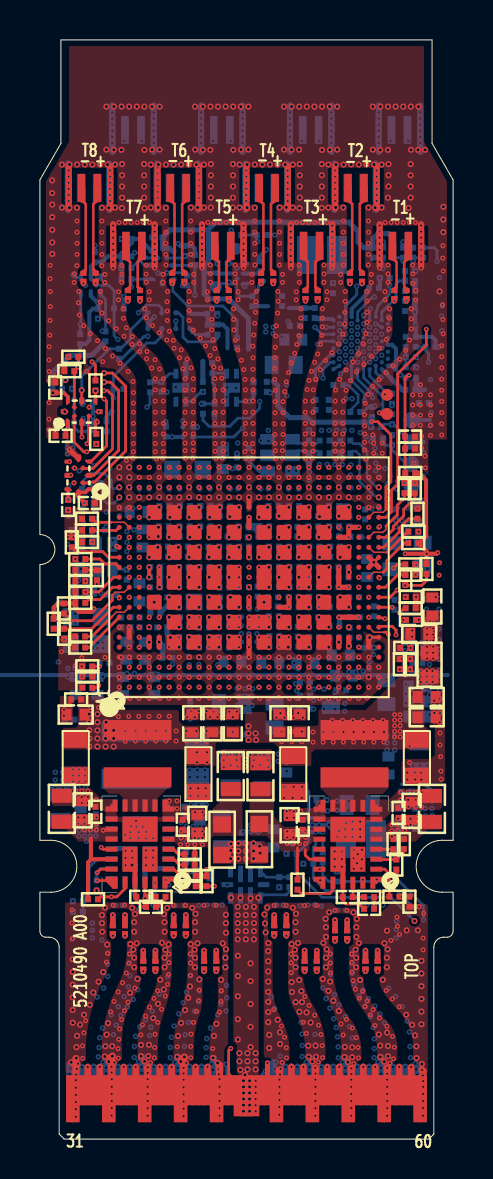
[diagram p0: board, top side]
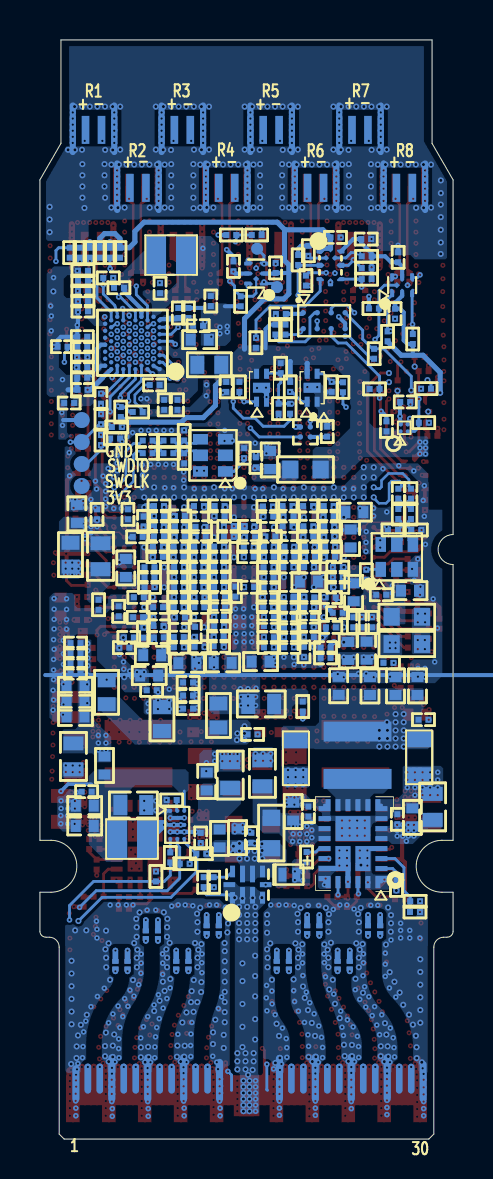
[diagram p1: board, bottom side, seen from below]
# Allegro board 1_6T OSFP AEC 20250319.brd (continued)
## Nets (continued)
LTX_P4: C922.1 U1.T23
LTX_P5: C924.1 U1.N23
LTX_P6: C926.1 U1.K23
LTX_P7: C928.1 U1.G23
LTX_P8: C930.1 U1.D23
LTXN1: C917.2 J2.3
LTXN2: C919.2 J6.3
LTXN3: C921.2 J10.3
LTXN4: C923.2 J14.3
LTXN5: C925.2 J3.3
LTXN6: C927.2 J7.3
LTXN7: C929.2 J11.3
LTXN8: C931.2 J15.3
LTXP1: C916.2 J2.2
LTXP2: C918.2 J6.2
LTXP3: C920.2 J10.2
LTXP4: C922.2 J14.2
LTXP5: C924.2 J3.2
LTXP6: C926.2 J7.2
LTXP7: C928.2 J11.2
LTXP8: C930.2 J15.2
M_INT: R31.2 U2.B4
M_LPWN: R29.2 U2.B6 U24.1
M_RSTN: C60.2 R28.2 R599.2 U2.A5 U4.1
MCU33: C42.2 C43.2 C169.2 C170.2 C173.2 C342.1 C419.2 C476.2 C891.2 C892.2 C933.2 L81.1 U2.A1 U2.A7 U2.B2 U2.B10 U2.G1 U2.H10 U2.R1 U2.R3 U2.T8
MCU_SPI_CLK: R15.2 R41.1 U17.10 U22.C1
MCU_SPI_CSB: R10.2 R40.1 U17.8 U22.A2
MCU_SPI_MISO: R11.2 U17.7 U22.B2
MCU_SPI_MOSI: R12.2 U17.9 U22.D1
MISO_SLV: U2.E5 U46.5
MISO_SLV_18: R829.2 R830.2 U46.7
MODE_SEL0: R404.1 R769.2 U1.C12 U2.N5
MOSI_SLV: U2.F6 U46.4
MOSI_SLV_18: U1.B14 U46.8
NRST: C455.2 R599.1 R603.2 U2.F8
OSFP_SCL: J1.14 R647.2 TP1.1(\TP\) U2.P4 U48.1
OSFP_SDA: J1.47 R648.2 TP2.1(\TP\) U2.C5 U48.3
PHY_I2C_LS_EN: R73.1 U2.J1 U10.8
PHY_I2C_SCL_33: R579.2 U2.E7 U10.1
PHY_I2C_SDA_33: R580.2 U2.C7 U10.3
PHY_INTR_N_18: R583.2 U1.C6 U38.7
PHY_INTR_N_33: R233.1 U2.A3 U38.5
PHY_RST_N_0_18: R856.2 U1.B10 U38.10
PHY_RST_N_0_33: R581.1 U2.R5 U38.2
PHY_RST_N_1_18: R855.2 U1.AF7 U38.9
PHY_RST_N_1_33: R582.1 U2.M4 U38.3
PHY_SELF_INIT_18: R783.1 U1.B8 U38.8
PHY_SELF_INIT_33: R849.1 U2.T6 U38.4
PMIC_SCL: R62.2 U2.G3 U20.20 U26.20 U37.E3
PMIC_SDA: R64.2 U2.F2 U20.19 U26.19 U37.E2
PMIC_SYNC1: U20.17 U21.18
PMIC_SYNC2: R685.1 U21.17
RXN1: C216.1 J1.28
RXN2: C218.1 J1.33
RXN3: C220.1 J1.25
RXN4: C222.1 J1.36
RXN5: C224.1 J1.22
RXN6: C226.1 J1.39
RXN7: C228.1 J1.19
RXN8: C230.1 J1.42
RXP1: C215.1 J1.29
RXP2: C217.1 J1.32
RXP3: C219.1 J1.26
RXP4: C221.1 J1.35
RXP5: C223.1 J1.23
RXP6: C225.1 J1.38
RXP7: C227.1 J1.20
RXP8: C229.1 J1.41
SCK_SLV: U2.C3 U46.2
SCK_SLV_18: U1.A15 U46.10
SPI_OE_DSP_EEPROM: U2.E9 U17.12
SS_N_SLV: U2.D4 U46.3
SS_N_SLV1: U1.AG10 U47.B2(\Y\)
SS_N_SLV_18: U1.C13 U46.9 U47.A1
SWCLK: J18.3 R5.2 R6.2 R648.1 U2.E3
SWDIO: J18.2 R3.1 R4.2 R647.1 U2.F4
TEMP_SENSOR: C40.2 R22.2 R25.1 U2.H6
TXN1: C200.2 J1.58
TXN2: C202.2 J1.3
TXN3: C204.2 J1.55
TXN4: C206.2 J1.6
TXN5: C208.2 J1.52
TXN6: C210.2 J1.9
TXN7: C212.2 J1.49
TXN8: C214.2 J1.12
TXP1: C199.2 J1.59
TXP2: C201.2 J1.2
TXP3: C203.2 J1.56
TXP4: C205.2 J1.5
TXP5: C207.2 J1.53
TXP6: C209.2 J1.8
TXP7: C211.2 J1.50
TXP8: C213.2 J1.11
VCAP: C174.2 C478.2 C479.2 C480.2 L27.2 U2.A9 U2.T2
VLXSMPS: C477.2 L27.1 U2.T4
N16845549: R760.1 R787.2 Y2.5
N16845553: R759.1 R788.2 Y2.4
N17308149: C649.1 C652.1 L95.1 Y2.6(\VCC\)
N17319056: R755.1 U1.A14
N17320165: R718.1 U1.C5
N17320275: R719.1 U1.AF8
N17322132: R770.1 R771.1 U1.C7
N17324604: R75.1 R767.1 U1.A9
N17324668: R105.1 R411.1 U1.C8
N17332280: R693.1 U1.AF12
N17332314: R694.1 U1.A11
N17340476: L4.1 U20.9 U20.10 U20.11 U20.12
N17340636: R46.2 R629.2 U20.3
N17341396: L88.1 U26.9 U26.10 U26.11 U26.12
N17341552: C501.1 R712.1 U26.23
N17341615: R710.2 U26.2
N17342760: L89.1 U37.C1 U37.C2 U37.C3
N17421630: C651.1 R787.1
N17421668: C650.1 R788.1
N17477873: C939.1 R735.2 U32.9
N17495631: C48.1 C49.1 L84.1 Y1.6(\VCC\)
N17495710: R35.1 R789.2 Y1.5
N17495716: C50.1 R789.1
N17495751: R36.1 R790.2 Y1.4
N17495757: C51.1 R790.1
N17508857: R690.1 U1.AE6
N17508860: R691.1 U1.B11
N17522369: R618.2 U20.4(\VSEL\)
N17525795: R711.2 R779.2 U26.3
N17525820: R748.2 U26.4(\VSEL\)
N17538591: R852.2 U37.E1
N17552273: C79.2 R649.1
N17552308: C346.2 R650.1
N17587092: L87.1 U21.9 U21.10 U21.11 U21.12
N17587354: R610.2 R778.2 U21.3
N17609312: R10.1 U2.L3
N17609315: R15.1 U2.M2
N17609318: R11.1 U2.N1
N17609321: R12.1 U2.L1
N17614675: R841.1 R842.1 U2.R9
N17630589: R829.1 U1.A13
N17630592: R830.1 U1.AE12
N17634649: R761.2 U1.P12
N17634729: R762.2 U1.P13
N17634818: R764.1 U1.B9
N17634883: R765.1 U1.AE5
N17635276: R833.1 U1.AF15
N17635432: R834.1 U1.AG15
N17635549: R835.1 U1.A17
N17635552: R838.1 U1.B17
N17635615: R836.1 U1.B15
N17635680: R815.1 U1.AF16
N17635747: R837.1 U1.AG16
N17635816: R839.1 U1.AE10
N17636368: R766.1 U1.A8
N17636718: R758.1 R783.2 U1.AG11
N17636870: R758.2 R854.1 U1.B12
N17689668: R845.2 U21.2
N17728804: C78.1 R608.2
N17738812: C492.1 R712.2
N17896792: R32.1 U22.B1
N17922824: TP3.1(\TP\) U1.AE19 U1.C19
N17922836: TP4.1(\TP\) U1.AE18 U1.C18

Pads without a net: U1 A5 A6 A18 AE7 AE9 AE13 AE14 AE15 AE16 AF9 AF11 AG4 AG5 C9 C10 C11; U2 C9 D10 F10 J9 K6 K10 M10; U26 17; Y1 2; Y2 2

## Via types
v1: diameter 0.254, hole 0.102, TOP to L2_GND, 1555 vias
v2: diameter 0.305, hole 0.152, TOP to BOTTOM, 617 vias
v3: diameter 0.279, hole 0.114, L2_GND to L3_GND, 1317 vias
v4: diameter 0.279, hole 0.114, L3_GND to L4_SIG1, 1273 vias
v5: diameter 0.279, hole 0.114, L4_SIG1 to L5_GND, 1113 vias
v6: diameter 0.279, hole 0.114, L11_GND to BOTTOM, 999 vias
v7: diameter 0.279, hole 0.114, L9_SIG2 to L10_GND, 1309 vias
v8: diameter 0.279, hole 0.114, L10_GND to L11_GND, 933 vias
v9: diameter 0.305, hole 0.152, L4_SIG1 to L9_SIG2, 278 vias
v10: diameter 0.279, hole 0.114, L7_PWR2 to L8_GND, 730 vias
v11: diameter 0.279, hole 0.114, L8_GND to L9_SIG2, 1077 vias
v12: diameter 0.279, hole 0.114, L5_GND to L6_PWR1, 953 vias

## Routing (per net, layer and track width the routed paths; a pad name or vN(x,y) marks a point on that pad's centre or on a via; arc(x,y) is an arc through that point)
3V3_IN_DDM: length 6
  L10_GND w0.081: v6(16.52,40.27) 16.52,40.92 16.83,41.22 16.83,41.42 17.13,41.73 18.3,41.73 18.49,41.92 18.49,42.69 18.39,42.79 18.39,43.6 v6(18.7,43.91)
  BOTTOM w0.14: R600.1 R601.1 v6(18.7,43.91)
AVDDH_1P2:
  vias: v2(6.48,30.11) v2(6.98,30.61) v2(7.48,27.11) v2(7.98,26.61) v2(12.98,27.11) v2(13.48,26.61) v2(13.98,30.11) v2(14.49,30.61) v6(17.39,20.2) v6(17.39,19.82) v6(17.39,19.47) v6(17.77,20.2) v6(17.77,19.82) v6(17.77,19.47) v6(18.3,24.8) v6(18.3,24.44) v6(18.3,24.07) v6(18.3,23.69) v6(18.32,23.22) v6(18.32,22.29) v6(18.33,21.81) v6(18.33,22.75) v7(17.39,20.2) v7(17.39,19.82) v7(17.39,19.47) v7(17.77,20.2) v7(17.77,19.82) v7(17.77,19.47) v7(18.3,24.8) v7(18.3,24.44) v7(18.3,24.07) v7(18.3,23.69) v7(18.32,23.22) v7(18.32,22.29) v7(18.33,21.81) v7(18.33,22.75) v8(17.39,20.2) v8(17.39,19.82) v8(17.39,19.47) v8(17.77,20.2) v8(17.77,19.82) v8(17.77,19.47) v8(18.3,24.8) v8(18.3,24.44) v8(18.3,24.07) v8(18.3,23.69) v8(18.32,23.22) v8(18.32,22.29) v8(18.33,21.81) v8(18.33,22.75)
AVDDLPLL_0P94: length 2.4
  TOP w0.254: U1.E5 v2(5.98,24.87) U1.E6 ; U1.AC6 v2(14.98,24.86) U1.AC5
  BOTTOM w0.203: C866.1 5.88,27.02 v2(5.73,26.86)
  BOTTOM w0.254: v2(5.98,24.87) 6.14,24.71 C786.1 C785.1 ; C819.1 14.99,24.88 v2(14.98,24.86)
  vias: v2(9.54,27.11) v2(9.98,26.61) v2(11.23,26.86) v2(15.04,27.11) v2(15.48,26.61) v6(9.88,22.56) v6(9.89,22.13) v6(9.89,21.7) v6(10.09,26.12) v6(10.09,25.69) v6(10.09,25.28) v6(10.09,24.88) v6(10.27,22.53) v6(10.27,22.15) v6(10.27,21.7) v6(10.49,26.53) v6(10.49,26.12) v6(10.49,25.69) v6(10.47,25.28) v6(10.47,24.88) v6(10.63,22.13) v6(10.63,21.7) v6(10.65,22.53) v6(10.9,26.53) v6(10.9,26.12) v6(10.9,25.69) v6(10.88,25.28) v6(10.88,24.88)
AVDDLPLLLINE_0P94: length 0.7
  BOTTOM w0.14: 16.21,30.1 16.18,30.13 C788.1
  BOTTOM w0.254: v2(15.48,31.61) 15.41,31.68 15,31.68
  vias: v2(5.48,31.11) v2(5.98,31.61) v2(9.51,31.14) v2(9.98,31.61) v2(10.98,31.11) v2(11.41,31.61) v2(14.98,31.17) v6(17.84,30.95) v6(17.84,30.64) v6(18.14,30.95) v6(18.14,30.64) v6(18.14,30.34) v6(18.45,30.95) v6(18.45,30.64) v6(18.45,30.34) v6(18.44,30.04) v7(17.84,30.95) v7(17.84,30.64) v7(18.14,30.95) v7(18.14,30.64) v7(18.14,30.34) v7(18.45,30.95) v7(18.45,30.64) v7(18.45,30.34) v7(18.44,30.04) v8(17.84,30.95) v8(17.84,30.64) v8(18.14,30.95) v8(18.14,30.64) v8(18.14,30.34) v8(18.45,30.95) v8(18.45,30.64) v8(18.45,30.34) v8(18.44,30.04) v10(17.84,30.95) v10(17.84,30.64) v10(18.14,30.95) v10(18.14,30.64) v10(18.14,30.34) v10(18.45,30.95) v10(18.45,30.64) v10(18.45,30.34) v10(18.44,30.04) v11(17.84,30.95) v11(17.84,30.64) v11(18.14,30.95) v11(18.14,30.64) v11(18.14,30.34) v11(18.45,30.95) v11(18.45,30.64) v11(18.45,30.34) v11(18.44,30.04)
AVDDLTXRX_0P94: length 1.1
  BOTTOM w0.203: v2(9.48,25.11) 9.48,24.6 C883.1
  BOTTOM w0.254: v2(11.48,24.61) 11.49,24.63 C881.1 C882.1
  vias: v1(9.98,25.11) v1(9.98,24.61) v1(10.98,25.11) v1(11.48,25.11) v1(19.4,25.86) v1(19.4,25.55) v1(19.4,25.25) v1(19.4,24.94) v1(19.4,24.64) v1(19.4,24.33) v1(19.4,24.05) v1(19.7,25.86) v1(19.7,25.55) v1(19.7,25.25) v1(19.7,24.94) v1(19.7,24.64) v1(19.7,24.33) v1(19.7,24.04) v2(6.48,26.11) v2(6.98,25.61) v2(7.48,25.11) v2(7.97,24.61) v2(8.48,30.11) v2(8.48,26.11) v2(8.98,30.61) v2(8.98,25.61) v2(11.98,30.11) v2(11.98,26.11) v2(12.48,30.61) v2(12.48,25.61) v2(12.98,25.11) v2(13.48,24.61) v2(13.98,26.11) v2(14.48,25.61) v3(9.98,25.11) v3(9.98,24.61) v3(10.98,25.11) v3(11.48,25.11) v3(19.4,25.86) v3(19.4,25.55) v3(19.4,25.25) v3(19.4,24.94) v3(19.4,24.64) v3(19.4,24.33) v3(19.4,24.05) v3(19.7,25.86) v3(19.7,25.55) v3(19.7,25.25) v3(19.7,24.94) v3(19.7,24.64) v3(19.7,24.33) v3(19.7,24.04) v4(9.98,25.11) v4(9.98,24.61) v4(10.98,25.11) v4(11.48,25.11) v4(19.4,25.86) v4(19.4,25.55) v4(19.4,25.25) v4(19.4,24.94) v4(19.4,24.64) v4(19.4,24.33) v4(19.4,24.05) v4(19.7,25.86) v4(19.7,25.55) v4(19.7,25.25) v4(19.7,24.94) v4(19.7,24.64) v4(19.7,24.33) v4(19.7,24.04) v5(9.98,25.11) v5(9.98,24.61) v5(10.98,25.11) v5(11.48,25.11)
AVDDTXDRV_0P94:
  vias: v2(7.48,31.11) v2(7.98,31.61) v2(12.98,31.11) v2(13.48,31.61) v6(10.45,30.66) v6(10.98,30.66) v6(10.98,30.15) v6(13.71,22.51) v6(13.71,21.95) v6(13.71,21.52) v6(14.22,22.51) v6(14.22,21.95) v6(14.22,21.52) v6(14.78,22.36) v6(14.78,21.95) v6(14.79,21.52) v6(15.28,21.79) v6(15.27,21.4)
GND: length 209.7
  TOP w0.127: U26.24 16.18,12.95 16.18,12.95 v1(16.18,12.97)
  TOP w0.14: C78.2 5.11,11.62 4.83,11.9 C81.2 4.77,12.18 U20.22 ; C492.2 16,11.76 15.35,11.76 15.18,11.93 C501.2 15.18,12.11 U26.22
  TOP w0.152: U1.AG6 U1.AF6 ; U1.AG14 v2(16.73,28.86)
  TOP w0.203: v1(2.85,27.77) 2.85,27.77 R404.2 ; R711.1 17.86,13.2 v1(17.85,13.2) ; R715.2 v3(19,11.63) ; v3(8.35,13.48) R635.2 8.32,13.18 R46.1
  TOP w0.254: U20.27 4.52,13.99 4.77,13.74 U20.22 ; v3(18.85,27.13) 18.84,27.12 v3(18.84,26.79) 18.84,26.56 ; U1.P17 v4(10.48,31.11) ; U46.6 v1(1.48,34.51) ; v1(0.77,35.56) 0.77,35.56 0.77,35.19 ; v1(12.48,27.11) v3(12.48,26.61) U1.U9 ; v1(18.27,32.84) 18.78,32.84 v1(18.78,32.83) ; U26.22 15.18,13.74 14.93,13.99 U26.27 ; v2(9.98,30.61) U1.M17 ; v1(14.98,28.61) U1.AC12 v1(14.98,27.61) v1(15.48,27.61) ; U1.AC16 v3(15.48,30.11) v1(15.48,30.61) v1(15.98,30.61) ; v3(10.48,26.61) v1(10.48,27.11) ; v8(10.48,24.11) v3(10.48,24.61) v3(10.48,25.11) ; U1.E11 v1(5.98,28.11) v1(5.98,28.61) ; U1.AG13 v2(16.73,28.86) ; v2(16.73,28.86) U1.AF14 ; v2(16.73,28.86) U1.AF13 ; U1.P15 v2(10.48,29.11) ; U1.B6 v1(4.48,25.61) ; v3(15.98,26.11) U1.AD8 v3(14.98,26.11) ; 1.22,38.43 v1(1.22,38.72) ; 0.77,37.87 0.77,38.13 v1(0.77,38.13) ; U1.AF5 U1.AF6 ; U1.P19 v2(10.48,32.11)
  TOP w0.305: 3.67,45.78 v12(3.67,45.72) v12(3.67,45.41) v12(3.67,45.11) v12(3.67,44.8) J11.4 v12(3.67,44.5) v12(3.67,44.19) v12(3.67,43.89) 3.67,43.66 ; 12.42,48.68 v12(12.42,48.46) v12(12.42,48.16) v12(12.42,47.85) J14.1 v12(12.42,47.55) v12(12.42,47.24) v12(12.42,46.94) 12.42,46.56 ; 16.88,48.68 v12(16.88,48.46) v12(16.88,48.16) v12(16.88,47.85) J6.1 v12(16.88,47.55) v12(16.88,47.24) v12(16.88,46.94) 16.88,46.56 ; 8.12,45.78 v12(8.12,45.72) v12(8.12,45.41) v12(8.12,45.11) v12(8.12,44.8) J3.4 v12(8.12,44.5) v12(8.12,44.19) v12(8.12,43.89) 8.12,43.66 ; 17.02,45.78 v12(17.02,45.72) v12(17.02,45.41) v12(17.02,45.11) v12(17.02,44.8) J2.4 v12(17.02,44.5) v12(17.02,44.19) v12(17.02,43.89) 17.02,43.66 ; 1.45,46.56 v12(1.45,46.94) v12(1.45,47.24) v12(1.45,47.55) J15.4 v12(1.45,47.85) v12(1.45,48.16) v12(1.45,48.46) 1.45,48.68 ; 19.1,43.66 v12(19.1,43.89) v12(19.1,44.19) v12(19.1,44.5) J2.1 v12(19.1,44.8) v12(19.1,45.11) v12(19.1,45.41) v12(19.1,45.72) 19.1,45.78 ; 7.97,48.68 v12(7.97,48.62) v12(7.97,48.31) v12(7.97,48.01) v12(7.97,47.7) J7.1 v12(7.97,47.4) v12(7.97,47.09) 7.97,46.56 ; 14.65,45.78 v12(14.65,45.72) v12(14.65,45.41) v12(14.65,45.11) v12(14.65,44.8) J10.1 v12(14.65,44.5) v12(14.65,44.19) v12(14.65,43.89) 14.65,43.66 ; 14.8,48.68 v12(14.8,48.46) v12(14.8,48.16) v12(14.8,47.85) J6.4 v12(14.8,47.55) v12(14.8,47.24) v12(14.8,46.94) 14.8,46.56 ; 5.9,48.68 v12(5.9,48.62) v12(5.9,48.31) v12(5.9,48.01) v12(5.9,47.7) J7.4 v12(5.9,47.4) v12(5.9,47.09) 5.9,46.56 ; 3.53,48.68 v12(3.53,48.46) v12(3.53,48.16) v12(3.53,47.85) J15.1 v12(3.53,47.55) v12(3.53,47.24) v12(3.53,46.94) 3.53,46.56 ; 10.2,45.78 v12(10.2,45.72) v12(10.2,45.41) v12(10.2,45.11) v12(10.2,44.8) J3.1 v12(10.2,44.5) v12(10.2,44.19) v12(10.2,43.89) 10.2,43.66 ; 5.75,43.66 v12(5.75,43.89) v12(5.75,44.19) v12(5.75,44.5) J11.1 v12(5.75,44.8) v12(5.75,45.11) v12(5.75,45.41) v12(5.75,45.72) 5.75,45.78 ; 12.57,43.66 v12(12.57,43.89) v12(12.57,44.19) v12(12.57,44.5) J10.4 v12(12.57,44.8) v12(12.57,45.11) v12(12.57,45.41) v12(12.57,45.72) 12.57,45.78 ; 10.35,48.68 v12(10.35,48.46) v12(10.35,48.16) v12(10.35,47.85) J14.4 v12(10.35,47.55) v12(10.35,47.24) v12(10.35,46.94) 10.35,46.56
  TOP w0.356: J1.54 15.6,3.53 v12(15.6,3.53) ; 12,3.45 v12(12,2.97) v12(12,2.61) v12(12,2.28) J1.48 ; J1.34 3.6,4.12 v2(3.63,4.15) ; J1.43 v12(9,2.26) v12(9,2.61) v12(9,2.99) 9,3.71 ; J1.40 7.2,4.07 v2(7.24,4.11) ; J1.57 v12(17.4,2.26) v12(17.4,2.61) v12(17.4,2.97) 17.4,3.56 v12(17.4,3.56) ; J1.51 13.8,3.56 ; v12(5.4,3.59) 5.4,3.59 v12(5.4,2.99) v12(5.4,2.61) v12(5.4,2.26) J1.37 ; J1.60 19.2,3.4 v12(19.15,3.45) ; J1.31 1.8,4.03
  L2_GND w0.064: 13.01,8.7 14.15,8.7 ; 14.54,10.23 15.67,10.23 ; 16.06,8.7 17.19,8.7 ; 11.49,10.48 12.62,10.48 ; 6.45,10.48 7.58,10.48 ; 3.4,10.48 4.54,10.48 ; 4.93,8.7 6.06,8.7 ; 7.98,8.7 9.11,8.7
  L2_GND w0.127: v1(5.76,12.83) 5.46,13.14 3.61,13.14 0.93,15.81 0.93,20.33 1.64,21.04 1.64,21.27 v4(1.83,21.46) ; v1(16.18,12.97) 16.43,12.97 19.45,15.99 19.45,18.79 19.12,19.12 18.8,19.12 v1(18.52,18.84) ; v4(5.29,26.88) 5.29,26.97 5.56,27.23 6.11,27.23 6.99,28.11 v2(7.48,28.11)
  L2_GND w0.254: v3(16.48,28.03) 16.48,28.24
  L4_SIG1 w0.127: v4(5.29,26.88) 4.89,26.47 4.89,25.98 4.64,25.73 3.52,25.73 2.91,25.12 2.91,23.22 1.92,22.23 1.92,21.55 v4(1.83,21.46)
  L10_GND w0.254: v6(4.8,15.56) v7(4.95,15.51)
  L11_GND w0.064: 11.49,10.48 12.62,10.48 ; 13.01,8.7 14.15,8.7 ; 6.45,10.48 7.58,10.48 ; 16.06,8.7 17.19,8.7 ; 7.98,8.7 9.11,8.7 ; 14.54,10.23 15.67,10.23 ; 3.4,10.48 4.54,10.48 ; 4.93,8.7 6.06,8.7
  L11_GND w0.203: v6(15.01,40.8) 14.67,40.8 v8(14.67,40.8)
  BOTTOM w0.127: U2.N3 15.3,40.65 15.04,40.81 v6(15.01,40.8) ; v6(16.83,40.8) 16.88,40.8 17.12,40.62 U2.N9 ; R63.1 15.55,36.47 15.94,36.87 15.94,37.24 15.45,37.74 C892.1
  BOTTOM w0.152: v6(17.08,38.1) 16.83,38.36 U2.B8
  BOTTOM w0.178: U37.A1 v6(14.42,16.42)
  BOTTOM w0.196: v6(14.17,16.07) U37.B2 v6(13.47,16.07)
  BOTTOM w0.203: J18.1 19.53,35.98 19.53,35.99 ; v6(18.79,41.38) 18.79,40.76 v6(18.83,40.73) C933.1 19.65,40.14 19.82,39.98 C60.1 v6(20.02,39.65) ; v6(6.92,44.81) 7.03,44.7 R581.2 7.63,44.7 7.76,44.56 R582.2 ; U22.D2 5.41,40.83 v6(5.73,41.15) ; C648.2 v6(12.64,14.76) ; C910.1 11,44.17 v6(11.34,44.51) ; C173.1 C891.1 12.48,41.59 12.47,41.58 ; R601.2 R24.2 ; C477.1 17.03,42.63 v6(17.03,43.09) ; v6(3.61,36.42) 3.34,36.15 C82.1 ; R849.2 v6(7.15,42.71) ; C886.2 C885.2 ; R411.2 v6(11.77,45.24) ; R850.2 v6(14.89,13.39) ; U8.B2 v6(2.17,36.06) ; R840.2 11.43,41.68 ; C425.1 v6(2.75,44.72) ; R73.2 v6(4.22,42.16)
  BOTTOM w0.254: v2(6.54,25.1) 6.37,25.27 C863.2 ; 16.74,24.59 16.73,24.59 v6(16.72,24.58) ; v2(5.99,27.61) 6.04,27.66 v6(6.04,28.11) v6(6.04,28.61) ; v6(8.9,41.2) 8.88,41.21 C45.2 ; v6(11.54,37.34) 11.49,37.39 C172.1 ; C830.2 11.48,30.61 v2(11.48,30.61) 11.48,30.65 C831.2 ; v6(9.88,34.32) 9.88,34.31 9.88,34.13 ; R649.2 7.53,21.03 v6(7.53,21.03) ; U47.B1 7.88,35.63 v6(7.88,35.63) ; 6.31,35.67 6.31,35.89 v6(6.31,35.89) ; v6(18.79,41.91) v6(18.79,41.38) ; v6(14.94,27.63) 14.94,27.61 ; U21.22 5.27,13.79 ; 19.29,37.49 18.85,37.49 18.85,38.1 ; C864.2 v6(15.01,26.11) 15.01,26.11 C805.2 ; U21.19 5.79,13.54 5.68,13.64 ; U4.5 9.35,37.35 U4.2 ; 6.39,26.7 6.39,26.7 C815.2 ; v6(18.2,44.89) 18.2,44.81 18.2,44.81 R24.2 ; 4.12,14.54 U21.4 ; U21.14 6.24,16.04 6.23,16.03 ; v2(11.48,25.61) 11.48,25.66 C855.2 C854.2 ; C857.2 C860.2 C809.2 ; v6(17.19,44.89) 17.19,44.8 R623.1 ; C169.1 v6(17.64,36.7)
  BOTTOM w0.305: 10.15,49.39 v6(10.15,49.85) v6(10.15,50.15) v6(10.15,50.46) J5.1 v6(10.15,50.76) v6(10.15,51.07) v6(10.15,51.37) 10.15,51.72 ; 3.62,51.72 v6(3.62,51.37) v6(3.62,51.07) v6(3.62,50.76) J13.4 v6(3.62,50.46) v6(3.62,50.15) v6(3.62,49.85) 3.62,49.39 ; 14.6,51.72 v6(14.6,51.37) v6(14.6,51.07) v6(14.6,50.76) J12.1 v6(14.6,50.46) v6(14.6,50.15) v6(14.6,49.85) 14.6,49.39 ; 7.93,48.82 v6(7.93,48.47) v6(7.93,48.17) v6(7.93,47.86) J9.1 v6(7.93,47.56) v6(7.93,47.25) v6(7.93,46.95) 7.93,46.49 ; 8.07,49.39 v6(8.07,49.85) v6(8.07,50.15) v6(8.07,50.46) J5.4 v6(8.07,50.76) v6(8.07,51.07) v6(8.07,51.37) 8.07,51.72 ; 5.85,46.49 v6(5.85,46.95) v6(5.85,47.25) v6(5.85,47.56) J9.4 v6(5.85,47.86) v6(5.85,48.17) v6(5.85,48.47) 5.85,48.82 ; 16.83,48.82 v6(16.83,48.47) v6(16.83,48.17) v6(16.83,47.86) J8.1 v6(16.83,47.56) v6(16.83,47.25) v6(16.83,46.95) 16.83,46.49 ; 1.4,46.49 v6(1.4,46.95) v6(1.4,47.25) v6(1.4,47.56) J17.4 v6(1.4,47.86) v6(1.4,48.17) v6(1.4,48.47) 1.4,48.82 ; 19.05,51.72 v6(19.05,51.37) v6(19.05,51.07) v6(19.05,50.76) J4.1 v6(19.05,50.46) v6(19.05,50.15) v6(19.05,49.85) 19.05,49.39 ; 5.7,51.72 v6(5.7,51.37) v6(5.7,51.07) v6(5.7,50.76) J13.1 v6(5.7,50.46) v6(5.7,50.15) v6(5.7,49.85) 5.7,49.39 ; 16.97,51.72 v6(16.97,51.37) v6(16.97,51.07) v6(16.97,50.76) J4.4 v6(16.97,50.46) v6(16.97,50.15) v6(16.97,49.85) 16.97,49.39 ; 10.3,46.49 v6(10.3,46.95) v6(10.3,47.25) v6(10.3,47.56) J16.4 v6(10.3,47.86) v6(10.3,48.17) v6(10.3,48.47) 10.3,48.82 ; 3.48,48.82 v6(3.48,48.47) v6(3.48,48.17) v6(3.48,47.86) J17.1 v6(3.48,47.56) v6(3.48,47.25) v6(3.48,46.95) 3.48,46.49 ; 12.52,51.72 v6(12.52,51.37) v6(12.52,51.07) v6(12.52,50.76) J12.4 v6(12.52,50.46) v6(12.52,50.15) v6(12.52,49.85) 12.52,49.39 ; 14.75,46.49 v6(14.75,46.95) v6(14.75,47.25) v6(14.75,47.56) J8.4 v6(14.75,47.86) v6(14.75,48.17) v6(14.75,48.47) 14.75,48.82 ; 12.38,46.49 v6(12.38,46.95) v6(12.38,47.25) v6(12.38,47.56) J16.1 v6(12.38,47.86) v6(12.38,48.17) v6(12.38,48.47) 12.38,48.82
  BOTTOM w0.356: J1.27 3.3,4.08 ; 17.1,4.06 v6(17.1,2.97) v6(17.1,2.61) v6(17.1,2.26) J1.4 ; J1.21 6.9,4.09 ; J1.24 v6(5.1,2.23) v6(5.1,2.59) v6(5.1,2.97) 5.1,4.11 ; J1.1 18.9,3.52 ; J1.10 13.5,4.09 ; J1.13 v6(11.7,2.28) v6(11.7,2.64) v6(11.7,2.99) 11.7,3.83 ; J1.7 15.3,4.06 ; J1.30 1.5,3.72 ; 8.7,4.04 v6(8.7,2.99) v6(8.7,2.61) v6(8.7,2.26) J1.18
  vias: v1(0.51,43.72) v1(0.51,43.05) v1(0.52,42.41) v1(0.52,41.66) v1(0.5,40.97) v1(0.49,40.23) v1(0.46,39.65) v1(0.46,38.99) v1(0.47,38.41) v1(0.46,37.95) v1(0.46,36.85) v1(0.45,36.02) v1(0.46,35.5) v1(1.08,24.39) v1(1.21,24.99) v1(1.21,21.49) v1(1.2,21.18) v1(1.41,31.47) v1(1.4,30.13) v1(1.49,21.73) v1(1.55,30.39) v1(1.61,11.46) v1(1.6,10.81) v1(1.62,10.01) v1(1.72,42.87) v1(1.69,30.12) v1(1.66,18.5) v1(1.66,18.19) v1(1.66,17.89) v1(1.73,43.3) v1(1.77,23.69) v1(1.79,17.42) v1(1.79,17.11) v1(1.79,16.81) v1(1.82,3.23) v1(1.8,2.94) v1(1.8,2.56) v1(1.8,2.21) v1(1.8,1.85) v1(1.8,1.5) v1(1.8,1.11) v1(1.86,45.94) v1(1.86,45.38) v1(1.86,44.82) v1(1.86,44.27) v1(1.85,43.71) v1(1.93,41.85) v1(1.84,30.38) v1(1.9,3.77) v1(1.85,3.51) v1(1.94,42.41) v1(1.98,41.24) v1(1.96,18.5) v1(1.96,18.19) v1(1.96,17.89) v1(2.09,24.09) v1(2.09,23.65) v1(2.1,17.42) v1(2.1,17.11) v1(2.1,16.81) v1(2.2,40.7) v1(2.2,5.31) v1(2.14,4.66) v1(2.14,4.03) v1(2.27,18.5) v1(2.27,18.19) v1(2.27,17.89) v1(2.29,5.92) v1(2.34,38.42) v1(2.4,17.42) v1(2.4,17.11) v1(2.4,16.81) v1(2.52,40.3) v1(2.77,32.12) v1(2.82,16.99) v1(2.89,39.95) v1(3.03,42.41) v1(3.03,41.87) v1(2.94,36.4) v1(3.1,45.94) v1(3.1,45.38) v1(3.1,44.82) v1(3.1,44.27) v1(3.11,43.7) v1(3.11,41.33) v1(3.15,38.91) v1(3.25,43.27) v1(3.25,42.87) v1(3.28,39.56) v1(3.26,24.11) v1(3.39,9.28) v1(3.34,8.85) v1(3.45,40.95) v1(3.54,6.37) v1(3.59,3.62) v1(3.59,3.33) v1(3.6,2.99) v1(3.6,2.61) v1(3.6,2.26) v1(3.6,1.9) v1(3.6,1.55) v1(3.59,1.17) v1(3.67,43.58) v1(3.64,39.18) v1(3.66,11.7) v1(3.71,6.89) v1(3.73,3.83) v1(3.82,40.55) v1(3.92,7.36) v1(3.92,4.52) v1(3.96,45.87) v1(3.94,42.4) v1(3.94,42) v1(4.02,38.82) v1(3.98,31.61) v1(3.98,30.11) v1(3.98,27.07) v1(3.98,25.61) v1(3.98,23.61) v1(3.98,23.11) v1(3.98,22.61) v1(4,5.51) v1(3.95,4.99) v1(3.93,4.05) v1(4.1,43.72) v1(4.1,43.28) v1(4.09,42.87) v1(4.07,24.11) v1(4.09,5.98) v1(4.17,41.55) v1(4.19,41.07) v1(4.22,40.17) v1(4.15,22.08) v1(4.14,7.82) v1(4.27,45.87) v1(4.33,40.6) v1(4.33,33.96) v1(4.28,15.22) v1(4.29,14.42) v1(4.29,14.06) v1(4.29,13.71) v1(4.24,11.71) v1(4.33,8.31) v1(4.23,6.43) v1(4.42,38.41) v1(4.41,6.85) v1(4.48,31.61) v1(4.48,24.61) v1(4.48,24.11) v1(4.48,23.11) v1(4.51,22.05) v1(4.52,15.35) v1(4.52,15.05) v1(4.5,9.26) v1(4.45,8.79) v1(4.57,45.87) v1(4.61,39.77) v1(4.57,15.65) v1(4.61,14.42) v1(4.62,14.08) v1(4.63,40.16) v1(4.67,37.91) v1(4.69,37.36) v1(4.68,36.83) v1(4.68,36.37) v1(4.68,35.81) v1(4.69,35.28) v1(4.69,34.8) v1(4.69,34.4) v1(4.65,34.08) v1(4.82,15.92) v1(4.76,7.56) v1(4.88,45.87) v1(4.83,15.63) v1(4.99,39.8) v1(5.01,39.41) v1(4.98,33.11) v1(4.98,30.61) v1(4.98,29.11) v1(4.98,24.11) v1(4.98,23.11) v1(4.96,22.05) v1(4.94,15.36) v1(4.94,15.05) v1(5.06,5.21) v1(5.18,45.87) v1(5.15,15.63) v1(5.14,5.71) v1(5.33,43.72) v1(5.32,43.28) v1(5.33,42.87) v1(5.25,41.55) v1(5.33,41.09) v1(5.32,15.37) v1(5.32,15.04) v1(5.31,14.45) v1(5.31,14.09) v1(5.31,13.71) v1(5.3,6.15) v1(5.36,39.41) v1(5.35,39.05) v1(5.4,3.31) v1(5.4,1.9) v1(5.4,1.55) v1(5.4,1.17) v1(5.49,45.87) v1(5.48,42.4) v1(5.48,42) v1(5.48,33.11) v1(5.48,30.11) v1(5.48,27.61) v1(5.48,26.11) v1(5.48,24.11) v1(5.48,23.61) v1(5.48,23.11) v1(5.48,22.61) v1(5.47,22.05) v1(5.49,6.6) v1(5.6,38.58) v1(5.54,3.82) v1(5.64,40.71) v1(5.66,15.05) v1(5.66,14.45) v1(5.66,14.09) v1(5.66,13.71) v1(5.72,7.04) v1(5.75,43.58) v1(5.77,38.99) v1(5.78,38.05) v1(5.78,37.49) v1(5.78,36.93) v1(5.78,36.37) v1(5.78,35.81) v1(5.78,35.28) v1(5.78,34.8) v1(5.78,34.4) v1(5.77,5.24) v1(5.75,4.58) v1(5.74,4.07) v1(5.84,34.05) v1(5.9,7.42) v1(5.9,5.83) v1(5.98,40.35) v1(6,38.54) v1(5.98,33.61) v1(5.98,33.11) v1(5.98,26.11) v1(5.98,25.61) v1(5.98,24.11) v1(5.98,23.11) v1(6.01,22.05) v1(6.09,6.49) v1(6.17,43.27) v1(6.17,42.87) v1(6.18,38.05) v1(6.18,37.49) v1(6.18,36.93) v1(6.18,36.37) v1(6.18,35.81) v1(6.18,35.28) v1(6.18,34.8) v1(6.18,34.4) v1(6.14,34.07) v1(6.31,45.94) v1(6.31,45.38) v1(6.31,44.82) v1(6.31,44.27) v1(6.32,43.74) v1(6.28,7.15) v1(6.39,42.41) v1(6.37,41.9) v1(6.38,41.44) v1(6.38,40.96) v1(6.36,39.99) v1(6.4,7.74) v1(6.48,40.42) v1(6.48,33.11) v1(6.48,24.61) v1(6.48,24.11) v1(6.48,23.11) v1(6.46,22.05) v1(6.49,16.92) v1(6.47,9.26) v1(6.46,8.83) v1(6.45,8.23) v1(6.69,39.97) v1(6.72,39.57) v1(6.68,11.7) v1(6.87,16.92) v1(6.87,16.54) v1(6.88,4.62) v1(6.99,39.1) v1(6.98,33.11) v1(6.98,25.11) v1(6.98,24.11) v1(6.98,23.61) v1(6.98,23.11) v1(6.98,22.61) v1(6.97,22.08) v1(7.08,39.5) v1(7.17,38.54) v1(7.2,3.56) v1(7.2,3.28) v1(7.2,2.97) v1(7.2,2.59) v1(7.2,2.23) v1(7.2,1.88) v1(7.2,1.52) v1(7.2,1.14) v1(7.27,38.05) v1(7.27,37.49) v1(7.27,36.93) v1(7.27,36.37) v1(7.27,35.81) v1(7.28,35.28) v1(7.28,34.83) v1(7.28,34.45) v1(7.3,34.07) v1(7.29,11.7) v1(7.37,39.03) v1(7.38,21.11) v1(7.38,16.54) v1(7.38,16.16) v1(7.33,3.81) v1(7.48,42.41) v1(7.48,41.91) v1(7.47,41.46) v1(7.48,40.96) v1(7.48,33.61) v1(7.48,33.11) v1(7.48,25.61) v1(7.48,24.11) v1(7.48,23.11) v1(7.51,22.05) v1(7.55,45.94) v1(7.55,45.38) v1(7.55,44.82) v1(7.55,44.27) v1(7.55,43.74) v1(7.58,38.59) v1(7.58,21.42) v1(7.55,17.55) v1(7.55,17.17) v1(7.54,9.27) v1(7.55,8.81) v1(7.55,8.19) v1(7.57,5.25) v1(7.55,4.63) v1(7.56,4.07) v1(7.7,43.27) v1(7.7,42.87) v1(7.69,40.48) v1(7.68,38.05) v1(7.68,37.49) v1(7.68,36.93) v1(7.68,36.37) v1(7.68,35.81) v1(7.68,35.28) v1(7.68,34.83) v1(7.68,34.45) v1(7.65,34.08) v1(7.69,5.84) v1(7.76,21.11) v1(7.77,16.36) v1(7.93,17.55) v1(7.93,17.17) v1(7.85,6.39) v1(7.98,33.11) v1(7.98,26.11) v1(7.98,23.11) v1(7.96,22.05) v1(7.96,21.42) v1(7.97,7.45) v1(7.96,6.92) v1(8.12,43.58) v1(8.03,40.08) v1(8.14,21.11) v1(8.15,16.36) v1(8.23,11.7) v1(8.3,39.69) v1(8.31,17.55) v1(8.31,17.17) v1(8.42,45.87) v1(8.39,42.4) v1(8.39,42) v1(8.34,21.42) v1(8.53,39.21) v1(8.48,33.11) v1(8.48,24.61) v1(8.48,24.11) v1(8.48,23.61) v1(8.48,23.11) v1(8.48,22.61) v1(8.5,22.08) v1(8.52,21.11) v1(8.54,43.73) v1(8.54,43.3) v1(8.54,42.87) v1(8.62,41.55) v1(8.61,41.01) v1(8.61,40.5) v1(8.72,45.87) v1(8.67,40) v1(8.71,38.63) v1(8.7,21.39) v1(8.66,4.53) v1(8.76,39.55) v1(8.77,38.05) v1(8.77,37.49) v1(8.77,36.93) v1(8.77,36.37) v1(8.77,35.81) v1(8.77,35.28) v1(8.77,34.8) v1(8.77,34.42) v1(8.82,34.06) v1(8.91,39.04) v1(8.9,21.11) v1(8.84,11.7) v1(8.92,3.49) v1(9.03,45.87) v1(8.98,33.61) v1(8.98,33.11) v1(8.98,25.11) v1(8.98,24.11) v1(8.98,23.11) v1(9.01,22.05) v1(9,6.35) v1(8.97,3.24) v1(9,1.9) v1(9,1.55) v1(9,1.17) v1(9.05,38.58) v1(9.11,38.07) v1(9.08,21.39) v1(9.09,7.43) v1(9.07,6.89) v1(9.18,37.49) v1(9.18,36.93) v1(9.18,36.37) v1(9.18,35.81) v1(9.18,35.28) v1(9.18,34.8) v1(9.18,34.42) v1(9.14,34.08) v1(9.22,19.31) v1(9.22,18.96) v1(9.22,18.62) v1(9.28,21.11) v1(9.33,45.87) v1(9.48,33.11) v1(9.48,25.61) v1(9.48,24.11) v1(9.48,23.11) v1(9.46,22.05) v1(9.49,21.39) v1(9.56,19.26) v1(9.56,18.7) v1(9.64,45.87) v1(9.7,41.55) v1(9.71,41.01) v1(9.72,40.49) v1(9.66,21.11) v1(9.78,43.73) v1(9.78,43.3) v1(9.78,42.87) v1(9.8,39.97) v1(9.93,42.4) v1(9.93,42) v1(9.92,39.49) v1(9.87,21.39) v1(9.85,18.97) v1(9.91,18.65) v1(9.94,45.87) v1(9.98,33.11) v1(9.98,28.61) v1(9.98,28.11) v1(9.98,27.61) v1(9.98,26.11) v1(9.98,25.61) v1(9.98,24.11) v1(9.98,23.61) v1(9.98,23.11) v1(9.98,22.61) v1(9.97,22.1) v1(10.09,38.97) v1(10.05,19.25) v1(10.2,43.58) v1(10.21,38.51) v1(10.28,38.01) v1(10.3,37.49) v1(10.3,36.93) v1(10.3,36.37) v1(10.3,35.81) v1(10.3,35.28) v1(10.3,34.8) v1(10.27,34.4) v1(10.33,34.05) v1(10.3,18.99) v1(10.29,18.65) v1(10.48,33.61) v1(10.48,33.11) v1(10.48,26.11) v1(10.48,25.61) v1(10.48,23.61) v1(10.48,23.11) v1(10.48,22.61) v1(10.48,22.1) v1(10.62,43.27) v1(10.62,42.87) v1(10.54,19.23) v1(10.71,40.24) v1(10.67,39.68) v1(10.67,39.09) v1(10.67,38.52) v1(10.67,38) v1(10.68,37.49) v1(10.68,36.93) v1(10.68,36.37) v1(10.68,35.81) v1(10.68,35.28) v1(10.65,34.8) v1(10.68,34.4) v1(10.63,34.07) v1(10.72,18.96) v1(10.67,18.65) v1(10.76,45.94) v1(10.76,45.38) v1(10.76,44.82) v1(10.76,44.27) v1(10.77,43.74) v1(10.83,41.91) v1(10.81,41.37) v1(10.76,40.82) v1(10.84,42.41) v1(10.98,33.11) v1(10.98,28.61) v1(10.98,26.11) v1(10.98,25.61) v1(10.98,24.11) v1(10.98,23.11) v1(11.01,22.05) v1(11.04,19.23) v1(11.04,18.72) v1(11.48,33.11) v1(11.48,26.11) v1(11.48,24.11) v1(11.48,23.11) v1(11.46,22.05) v1(11.44,19.3) v1(11.44,18.96) v1(11.44,18.62) v1(11.71,6.47) v1(11.82,40.19) v1(11.79,39.62) v1(11.77,39.11) v1(11.77,38.55) v1(11.77,38.02) v1(11.8,37.46) v1(11.78,36.9) v1(11.78,36.34) v1(11.77,35.79) v1(11.77,35.26) v1(11.77,34.8) v1(11.8,34.45) v1(11.82,34.06) v1(11.73,11.69) v1(11.93,42.41) v1(11.91,41.33) v1(11.85,40.7) v1(11.85,21.09) v1(12,45.94) v1(12,45.38) v1(12,44.82) v1(12,44.27) v1(12,43.74) v1(11.94,41.93) v1(11.98,33.61) v1(11.98,33.11) v1(11.98,27.11) v1(11.98,24.61) v1(11.98,24.11) v1(11.98,23.61) v1(11.98,23.11) v1(11.98,22.61) v1(11.98,22.1) v1(12.03,3.23) v1(12,1.95) v1(12,1.6) v1(12,1.22) v1(12.05,21.31) v1(12.1,5.65) v1(12.06,3.51) v1(12.15,43.27) v1(12.15,42.87) v1(12.18,36.9) v1(12.18,36.35) v1(12.18,35.79) v1(12.18,35.26) v1(12.15,34.8) v1(12.15,34.45) v1(12.15,34.08) v1(12.23,17.07) v1(12.13,3.83) v1(12.26,37.4) v1(12.25,21.09) v1(12.25,17.63) v1(12.25,5.09) v1(12.34,37.89) v1(12.36,16.4) v1(12.38,16.07) v1(12.34,11.69) v1(12.34,4.57) v1(12.36,4.06) v1(12.45,38.36) v1(12.48,33.11) v1(12.48,25.11) v1(12.48,24.11) v1(12.48,23.11) v1(12.51,22.05) v1(12.48,21.31) v1(12.57,43.58) v1(12.59,38.84) v1(12.58,9.26) v1(12.59,8.81) v1(12.58,8.34) v1(12.71,21.09) v1(12.71,17.63) v1(12.66,17.07) v1(12.71,16.4) v1(12.76,39.32) v1(12.74,16.08) v1(12.86,45.87) v1(12.84,42.4) v1(12.84,42) v1(12.87,39.76) v1(12.99,43.73) v1(12.99,43.3) v1(12.99,42.87) v1(12.98,40.2) v1(12.98,33.11) v1(12.98,27.61) v1(12.98,24.11) v1(12.98,23.11) v1(12.96,22.05) v1(12.94,21.31) v1(13.07,41.55) v1(13.07,41.08) v1(13.07,40.66) v1(13.12,17.07) v1(13.07,16.4) v1(13.16,45.87) v1(13.17,21.09) v1(13.14,17.63) v1(13.2,5.85) v1(13.29,36.93) v1(13.29,36.37) v1(13.29,35.81) v1(13.3,35.28) v1(13.3,34.78) v1(13.27,34.42) v1(13.31,34.06) v1(13.26,11.69) v1(13.27,7.13) v1(13.39,37.5) v1(13.35,5.29) v1(13.47,45.87) v1(13.48,37.96) v1(13.48,33.61) v1(13.48,33.11) v1(13.48,28.11) v1(13.48,24.11) v1(13.48,23.61) v1(13.48,23.11) v1(13.48,22.61) v1(13.47,22.08) v1(13.49,6.68) v1(13.61,38.42) v1(13.63,34.08) v1(13.7,37.49) v1(13.68,36.93) v1(13.68,36.37) v1(13.68,35.81) v1(13.68,35.28) v1(13.68,34.78) v1(13.68,34.42) v1(13.77,45.87) v1(13.76,38.87) v1(13.82,38) v1(13.77,6.2) v1(13.8,3.56) v1(13.81,3.27) v1(13.8,2.97) v1(13.8,2.61) v1(13.8,2.26) v1(13.8,1.9) v1(13.8,1.55) v1(13.8,1.17) v1(13.92,39.28) v1(13.87,11.69) v1(13.98,33.11) v1(13.98,26.61) v1(13.98,24.11) v1(13.98,23.11) v1(14.01,22.05) v1(13.96,5.7) v1(13.94,3.85) v1(14.08,45.87) v1(14.13,40.22) v1(14.06,39.77) v1(14.04,38.5) v1(14.08,5.23) v1(14.23,43.73) v1(14.23,42.87) v1(14.15,41.55) v1(14.15,41.08) v1(14.15,40.65) v1(14.14,4.68) v1(14.16,4.07) v1(14.24,43.3) v1(14.31,38.96) v1(14.38,45.87) v1(14.38,42.4) v1(14.38,42) v1(14.48,33.11) v1(14.48,24.11) v1(14.48,23.11) v1(14.46,22.05) v1(14.63,39.36) v1(14.55,9.27) v1(14.55,8.82) v1(14.56,8.32) v1(14.65,43.58) v1(14.82,37.48) v1(14.79,36.93) v1(14.79,36.37) v1(14.79,35.81) v1(14.79,35.28) v1(14.79,34.78) v1(14.79,34.42) v1(14.77,14.39) v1(14.77,14.01) v1(14.77,13.63) v1(14.78,11.44) v1(14.84,34.05) v1(14.9,15.12) v1(14.95,39.8) v1(15.01,38.02) v1(14.98,33.61) v1(14.98,33.11) v1(14.98,30.61) v1(14.98,25.61) v1(14.98,24.11) v1(14.98,23.61) v1(14.98,23.11) v1(14.98,22.61) v1(14.97,22.05) v1(14.98,15.41) v1(15.07,43.27) v1(15.07,42.87) v1(15.13,14.39) v1(15.13,14.01) v1(15.13,13.63) v1(15.09,5.76) v1(15.21,45.94) v1(15.21,45.38) v1(15.21,44.82) v1(15.21,44.27) v1(15.22,43.74) v1(15.18,40.28) v1(15.21,36.94) v1(15.17,36.37) v1(15.17,35.81) v1(15.18,35.28) v1(15.18,34.78) v1(15.15,34.42) v1(15.16,34.08) v1(15.19,5.21) v1(15.29,42.41) v1(15.29,41.92) v1(15.28,41.36) v1(15.27,40.79) v1(15.28,15.5) v1(15.28,15.12) v1(15.35,38.49) v1(15.33,37.46) v1(15.35,15.81) v1(15.39,11.44) v1(15.36,5.99) v1(15.48,33.11) v1(15.48,24.11) v1(15.48,23.11) v1(15.51,22.05) v1(15.56,37.95) v1(15.62,9.26) v1(15.61,3.26) v1(15.6,2.97) v1(15.6,2.61) v1(15.6,2.26) v1(15.6,1.9) v1(15.6,1.55) v1(15.6,1.17) v1(15.69,38.89) v1(15.66,15.88) v1(15.66,15.5) v1(15.66,15.12) v1(15.73,14.48) v1(15.72,14.06) v1(15.72,13.52) v1(15.63,8.84) v1(15.64,8.36) v1(15.69,7.93) v1(15.65,5.56) v1(15.72,3.78) v1(15.81,7.5) v1(15.85,38.4) v1(15.92,14.25) v1(15.89,13.8) v1(15.85,5.07) v1(15.97,39.31) v1(15.98,33.11) v1(15.98,32.11) v1(15.98,24.11) v1(15.98,23.11) v1(15.96,22.05) v1(16.01,7.04) v1(15.94,4.59) v1(15.96,4.06) v1(16.04,15.88) v1(16.04,15.5) v1(16.04,15.12) v1(16.11,13.54) v1(16.19,39.81) v1(16.23,38.77) v1(16.13,14.48) v1(16.13,13.99) v1(16.16,7.39) v1(16.33,40.31) v1(16.3,36.82) v1(16.27,36.25) v1(16.26,35.7) v1(16.27,35.29) v1(16.27,34.87) v1(16.27,34.49) v1(16.28,6.62) v1(16.38,42.41) v1(16.38,41.93) v1(16.38,41.38) v1(16.38,40.87) v1(16.33,34.04) v1(16.39,22.08) v1(16.39,6.91) v1(16.46,45.94) v1(16.46,45.38) v1(16.46,44.82) v1(16.46,44.27) v1(16.45,43.74) v1(16.45,37.26) v1(16.48,33.61) v1(16.48,33.11) v1(16.48,32.61) v1(16.48,32.11) v1(16.48,31.61) v1(16.48,27.11) v1(16.48,24.11) v1(16.48,23.61) v1(16.48,22.61) v1(16.6,43.27) v1(16.6,42.87) v1(16.61,39.16) v1(16.55,6.22) v1(16.67,37.66) v1(16.68,35.24) v1(16.72,34.83) v1(16.72,34.32) v1(16.69,6.47) v1(16.79,5.68) v1(17.02,43.58) v1(17.01,39.57) v1(16.99,38) v1(16.98,33.61) v1(16.98,33.11) v1(16.98,31.65) v1(16.98,23.61) v1(16.98,23.11) v1(16.98,22.61) v1(17.01,6.05) v1(17.16,34.83) v1(17.16,34.32) v1(17.29,45.86) v1(17.29,42.4) v1(17.29,42) v1(17.35,40.01) v1(17.35,38.35) v1(17.35,7.43) v1(17.38,5.64) v1(17.4,3.27) v1(17.4,1.9) v1(17.4,1.55) v1(17.4,1.17) v1(17.44,43.73) v1(17.44,43.3) v1(17.44,42.87) v1(17.52,41.55) v1(17.51,41.07) v1(17.5,40.54) v1(17.6,45.86) v1(17.59,9.94) v1(17.53,3.8) v1(17.69,38.69) v1(17.65,7.01) v1(17.66,5.14) v1(17.71,4.01) v1(17.76,4.59) v1(17.9,45.86) v1(17.89,11.1) v1(17.92,10.65) v1(18.03,39.02) v1(18.02,10.24) v1(18,6.61) v1(18.07,17.36) v1(18.07,16.97) v1(18.08,16.63) v1(18.21,45.86) v1(18.14,24.04) v1(18.33,39.47) v1(18.41,18.34) v1(18.41,17.99) v1(18.51,45.86) v1(18.52,39.98) v1(18.45,17.36) v1(18.45,16.97) v1(18.46,16.63) v1(18.6,41.55) v1(18.61,41.04) v1(18.6,40.54) v1(18.54,24.03) v1(18.68,43.73) v1(18.68,43.3) v1(18.68,42.82) v1(18.68,37.24) v1(18.68,36.73) v1(18.68,36.22) v1(18.68,35.72) v1(18.66,25.44) v1(18.65,25.14) v1(18.82,45.86) v1(18.83,42) v1(18.75,33.81) v1(18.79,18.34) v1(18.8,17.99) v1(18.83,17.36) v1(18.83,16.97) v1(18.84,42.46) v1(18.92,31.56) v1(18.84,16.63) v1(18.98,30.4) v1(19.1,43.58) v1(19.06,37.75) v1(19.06,37.24) v1(19.06,36.73) v1(19.06,36.22) v1(19.06,35.72) v1(19.12,35.17) v1(19.13,34.57) v1(19.1,18.33) v1(19.11,17.98) v1(19.12,17.35) v1(19.12,16.97) v1(19.13,16.62) v1(19.23,11.3) v1(19.2,10.05) v1(19.2,9.47) v1(19.19,3.18) v1(19.2,2.9) v1(19.2,2.61) v1(19.2,2.26) v1(19.2,1.9) v1(19.2,1.55) v1(19.2,1.17) v1(19.3,34.18) v1(19.31,33.59) v1(19.57,37.24) v1(19.57,36.73) v1(19.57,36.22) v1(19.57,35.72) v1(19.57,35.21) v1(19.75,21.94) v1(19.74,21.67) v1(19.76,21.32) v1(19.83,27.12) v1(20.02,28.84) v1(20,28.22) v1(20.13,39.71) v1(20.13,39.15) v1(20.13,38.59) v1(20.13,38.03) v1(20.13,37.47) v1(20.13,36.91) v1(20.13,36.35) v1(20.13,35.79) v1(20.13,35.23) v1(20.03,22.04) v1(20.03,21.66) v1(20.05,21.32) v1(20.04,20.85) v1(20.05,20.32) v1(20.05,19.71) v1(20.07,19.14) v1(20.09,18.41) v1(20.1,18.01) v1(20.19,44.7) v1(20.18,44.09) v1(20.2,43.44) v1(20.18,41.75) v1(20.19,41) v1(20.2,40.29) v2(0.61,47.97) v2(0.61,47.34) v2(0.62,46.76) v2(0.62,46.14) v2(0.62,45.5) v2(0.62,44.87) v2(0.62,44.29) v2(1.1,48.77) v2(1.1,46.61) v2(1.48,48.77) v2(1.48,46.6) v2(1.57,3.84) v2(1.64,9) v2(1.64,8.36) v2(1.64,7.73) v2(1.64,7.09) v2(1.64,6.46) v2(1.64,5.82) v2(1.83,4.59) v2(1.82,4.05) v2(1.86,48.77) v2(1.85,46.6) v2(1.86,5.17) v2(2.01,5.72) v2(2.21,6.22) v2(2.25,48.77) v2(2.5,6.72) v2(2.63,48.77) v2(2.68,7.33) v2(3.01,48.77) v2(2.94,7.87) v2(3.1,46.6) v2(3.11,11.21) v2(3.11,10.8) v2(3.12,10.38) v2(3.18,8.35) v2(3.33,51.67) v2(3.33,49.51) v2(3.25,11.59) v2(3.28,4.64) v2(3.25,4.13) v2(3.39,48.77) v2(3.36,9.73) v2(3.41,5.8) v2(3.34,5.23) v2(3.44,46.6) v2(3.45,3.87) v2(3.62,4.64) v2(3.71,51.67) v2(3.7,49.5) v2(3.77,48.77) v2(3.77,46.61) v2(3.98,33.61) v2(3.98,33.11) v2(4.09,51.67) v2(4.08,49.5) v2(4.11,48.79) v2(4.11,48.23) v2(4.11,47.67) v2(4.11,47.11) v2(4.11,46.59) v2(4.47,51.67) v2(4.48,33.61) v2(4.48,33.11) v2(4.48,32.61) v2(4.48,32.11) v2(4.51,7.32) v2(4.62,13.71) v2(4.63,11.57) v2(4.53,9.76) v2(4.72,10.85) v2(4.72,10.37) v2(4.68,9.48) v2(4.72,9.08) v2(4.72,8.6) v2(4.76,11.26) v2(4.85,51.67) v2(4.85,9.79) v2(4.89,8.02) v2(4.98,32.11) v2(5.07,4.71) v2(5.06,4.15) v2(5.22,48.79) v2(5.22,48.23) v2(5.22,47.67) v2(5.22,47.11) v2(5.23,51.67) v2(5.24,49.5) v2(5.24,46.58) v2(5.25,3.89) v2(5.48,32.11) v2(5.47,4.72) v2(5.43,4.15) v2(5.61,51.67) v2(5.62,49.51) v2(5.55,48.77) v2(5.55,46.61) v2(5.68,6.05) v2(5.93,46.62) v2(5.93,30.15) v2(5.92,6.77) v2(5.99,51.67) v2(5.99,49.51) v2(5.93,48.77) v2(5.98,32.61) v2(5.98,32.11) v2(5.94,30.61) v2(6.03,7.97) v2(6.12,9.82) v2(6.22,11.25) v2(6.21,7.48) v2(6.31,48.77) v2(6.31,46.6) v2(6.24,10.85) v2(6.25,10.37) v2(6.29,9.47) v2(6.24,9.08) v2(6.25,8.6) v2(6.37,11.57) v2(6.48,32.11) v2(6.51,31.11) v2(6.48,29.11) v2(6.48,27.11) v2(6.45,9.74) v2(6.7,48.77) v2(6.92,5.16) v2(6.88,4.12) v2(6.98,32.11) v2(6.98,31.61) v2(6.94,29.61) v2(6.98,26.61) v2(6.98,24.61) v2(7.08,48.77) v2(7.08,5.81) v2(7.05,3.88) v2(7.27,6.45) v2(7.46,48.77) v2(7.48,32.61) v2(7.48,32.11) v2(7.51,30.11) v2(7.48,26.11) v2(7.52,7.64) v2(7.43,7.07) v2(7.56,46.61) v2(7.55,9.75) v2(7.64,11.57) v2(7.78,51.67) v2(7.78,49.51) v2(7.79,11.27) v2(7.77,10.85) v2(7.77,10.37) v2(7.74,9.48) v2(7.77,9.08) v2(7.77,8.6) v2(7.84,48.77) v2(7.9,46.62) v2(7.9,9.79) v2(7.98,32.11) v2(7.98,30.61) v2(7.98,28.61) v2(7.98,27.61) v2(7.98,25.61) v2(7.98,24.11) v2(7.99,7.99) v2(8.16,51.67) v2(8.16,49.49) v2(8.22,48.77) v2(8.22,46.61) v2(8.48,32.11) v2(8.51,31.11) v2(8.48,29.11) v2(8.48,27.11) v2(8.48,25.11) v2(8.54,51.67) v2(8.53,49.5) v2(8.56,48.79) v2(8.56,48.23) v2(8.56,47.67) v2(8.56,47.11) v2(8.56,46.61) v2(8.72,5.16) v2(8.68,4.06) v2(8.92,51.67) v2(8.84,5.77) v2(8.9,3.81) v2(8.98,32.61) v2(8.98,32.11) v2(9.01,31.61) v2(8.98,29.61) v2(8.98,26.61) v2(8.98,24.61) v2(9.08,7.97) v2(9.16,9.79) v2(9.3,51.67) v2(9.32,11.23) v2(9.32,10.8) v2(9.32,10.32) v2(9.32,9.49) v2(9.29,9.08) v2(9.29,8.6) v2(9.48,32.11) v2(9.48,30.11) v2(9.48,28.11) v2(9.48,26.11) v2(9.68,51.67) v2(9.69,49.5) v2(9.67,48.79) v2(9.67,48.23) v2(9.67,47.67) v2(9.67,47.11) v2(9.67,46.61) v2(10,48.77) v2(10,46.61) v2(9.98,32.11) v2(10.06,51.67) v2(10.07,49.51) v2(10.38,48.77) v2(10.38,46.61) v2(10.44,51.67) v2(10.44,49.51) v2(10.48,32.61) v2(10.76,48.77) v2(10.76,46.61) v2(10.98,32.11) v2(11.15,48.77) v2(11.25,11.24) v2(11.27,10.79) v2(11.31,10.34) v2(11.39,11.59) v2(11.53,48.77) v2(11.48,32.11) v2(11.48,28.61) v2(11.48,27.61) v2(11.45,9.81) v2(11.44,9.4) v2(11.44,8.89) v2(11.44,8.39) v2(11.44,7.88) v2(11.44,7.37) v2(11.44,6.86) v2(11.44,6.35) v2(11.44,5.85) v2(11.49,5.21) v2(11.49,4.56) v2(11.91,48.77) v2(11.91,5.97) v2(12.01,46.61) v2(11.98,32.61) v2(11.98,32.11) v2(11.98,31.17) v2(11.98,29.11) v2(11.98,25.11) v2(12.03,5.34) v2(12.03,4.75) v2(12.23,51.67) v2(12.23,49.51) v2(12.29,48.77) v2(12.34,46.62) v2(12.48,32.11) v2(12.48,31.61) v2(12.48,29.61) v2(12.44,24.61) v2(12.61,51.67) v2(12.61,49.51) v2(12.61,9.76) v2(12.61,7.85) v2(12.62,7.36) v2(12.67,48.77) v2(12.67,46.61) v2(12.67,11.58) v2(12.83,11.28) v2(12.8,10.85) v2(12.81,10.37) v2(12.76,9.47) v2(12.8,9.08) v2(12.81,8.6) v2(12.81,6.85) v2(12.93,9.81) v2(12.99,51.67) v2(12.98,49.51) v2(13.01,48.79) v2(13.01,48.23) v2(13.01,47.67) v2(13.01,47.11) v2(13.01,46.58) v2(12.98,32.11) v2(12.98,30.11) v2(12.98,28.11) v2(12.98,26.11) v2(12.99,7.96) v2(13,6.37) v2(13.1,7.4) v2(13.13,6.85) v2(13.37,51.67) v2(13.36,6.34) v2(13.48,32.61) v2(13.48,32.11) v2(13.48,30.61) v2(13.48,28.61) v2(13.48,27.61) v2(13.48,25.61) v2(13.45,4.67) v2(13.47,4.12) v2(13.56,5.83) v2(13.65,3.88) v2(13.75,51.67) v2(13.81,4.67) v2(13.83,4.12) v2(13.98,32.11) v2(14.01,31.14) v2(14.01,29.11) v2(13.98,27.11) v2(14.12,48.79) v2(14.12,48.23) v2(14.12,47.67) v2(14.12,47.11) v2(14.12,46.6) v2(14.13,51.67) v2(14.13,49.5) v2(14.2,9.82) v2(14.17,8.01) v2(14.31,11.02) v2(14.33,10.6) v2(14.33,10.12) v2(14.33,9.08) v2(14.33,8.6) v2(14.37,9.49) v2(14.51,51.67) v2(14.52,49.5) v2(14.45,48.77) v2(14.45,46.61) v2(14.48,32.11) v2(14.48,31.61) v2(14.48,29.61) v2(14.48,24.61) v2(14.49,11.35) v2(14.45,7.41) v2(14.54,7.88) v2(14.7,6.92) v2(14.82,46.62) v2(14.89,51.67) v2(14.89,49.51) v2(14.83,48.77) v2(14.98,32.61) v2(14.98,32.11) v2(14.97,6.41) v2(15.21,48.77) v2(15.2,46.61) v2(15.28,4.61) v2(15.25,4.11) v2(15.43,3.84) v2(15.48,32.11) v2(15.6,48.77) v2(15.71,11.34) v2(15.64,4.59) v2(15.65,4.09) v2(15.82,9.48) v2(15.87,11.02) v2(15.85,10.6) v2(15.85,10.12) v2(15.85,9.07) v2(15.84,8.6) v2(15.98,48.77) v2(15.98,9.81) v2(16.04,7.96) v2(16.36,48.77) v2(16.46,46.61) v2(16.52,25.09) v2(16.48,23.11) v2(16.68,51.67) v2(16.68,49.51) v2(16.74,48.77) v2(16.79,46.61) v2(16.98,5.23) v2(17.06,51.67) v2(17.05,49.49) v2(17.12,48.77) v2(17.12,46.61) v2(17.05,4.67) v2(17.05,4.11) v2(17.19,7.97) v2(17.26,9.79) v2(17.26,3.87) v2(17.39,10.43) v2(17.42,9.5) v2(17.38,9.08) v2(17.38,8.6) v2(17.39,5.33) v2(17.44,51.67) v2(17.43,49.5) v2(17.46,48.79) v2(17.46,48.23) v2(17.46,47.67) v2(17.43,47.11) v2(17.44,4.65) v2(17.44,4.14) v2(17.82,51.67) v2(18.2,51.67) v2(18.38,10.44) v2(18.35,6.22) v2(18.47,46.59) v2(18.58,51.67) v2(18.59,49.51) v2(18.57,48.79) v2(18.57,48.23) v2(18.57,47.67) v2(18.57,47.11) v2(18.65,5.71) v2(18.79,5.18) v2(18.86,4.64) v2(18.87,4.06) v2(18.96,51.67) v2(18.95,49.5) v2(18.93,10.44) v2(19.12,8.92) v2(19.12,8.28) v2(19.12,7.65) v2(19.12,7.01) v2(19.12,6.38) v2(19.12,5.74) v2(19.14,3.75) v2(19.29,49.5) v2(20.03,42.42) v2(20.21,46.65) v2(20.21,46.02) v2(20.21,45.38) v3(0.51,43.72) v3(0.51,43.05) v3(0.52,42.41) v3(0.52,41.66) v3(0.5,40.97) v3(0.49,40.23) v3(0.46,39.65) v3(0.46,38.99) v3(0.47,38.41) v3(0.46,37.95) v3(0.46,36.85) v3(0.45,36.02) v3(0.46,35.5) v3(0.45,35.14) v3(0.5,31.21) v3(0.5,28.31) v3(0.5,27.26) v3(0.5,26.32) v3(0.48,25.17) v3(0.5,24.04) v3(0.51,22.91) v3(0.51,21.67) v3(0.47,19.89) v3(0.47,18.99) v3(0.47,18) v3(0.47,17.06) v3(0.48,16.15) v3(0.81,15.41) v3(0.86,30.59) v3(1.21,21.49) v3(1.2,21.18) v3(1.49,21.73) v3(1.72,42.87) v3(1.66,18.5) v3(1.66,18.19) v3(1.66,17.89) v3(1.66,10.06) v3(1.73,43.3) v3(1.77,23.69) v3(1.79,17.42) v3(1.79,17.11) v3(1.79,16.81) v3(1.82,3.23) v3(1.8,2.94) v3(1.8,2.56) v3(1.8,2.21) v3(1.8,1.85) v3(1.8,1.5) v3(1.8,1.11) v3(1.86,45.94) v3(1.86,45.38) v3(1.86,44.82) v3(1.86,44.27) v3(1.85,43.71) v3(1.93,41.85) v3(1.88,30.78) v3(1.92,20.22) v3(1.92,19.71) v3(1.9,3.77) v3(1.85,3.51) v3(1.94,42.41) v3(1.98,41.24) v3(1.97,39.98) v3(1.94,22.19) v3(1.96,18.5) v3(1.96,18.19) v3(1.96,17.89) v3(2.09,24.09) v3(2.09,23.65) v3(2.1,17.42) v3(2.1,17.11) v3(2.1,16.81) v3(2.2,40.7) v3(2.2,5.31) v3(2.14,4.66) v3(2.14,4.03) v3(2.17,1.03) v3(2.31,39.63) v3(2.27,18.5) v3(2.27,18.19) v3(2.27,17.89) v3(2.29,5.92) v3(2.39,22.77) v3(2.4,17.42) v3(2.4,17.11) v3(2.4,16.81) v3(2.52,40.3) v3(2.53,1.03) v3(2.78,37.86) v3(2.8,36.98) v3(2.82,16.99) v3(2.89,39.95) v3(2.89,1.03) v3(3.03,42.41) v3(3.03,41.87) v3(2.96,25.73) v3(3.1,45.94) v3(3.1,45.38) v3(3.1,44.82) v3(3.1,44.27) v3(3.11,43.7) v3(3.11,41.33) v3(3.22,1.03) v3(3.25,43.27) v3(3.25,42.87) v3(3.28,39.56) v3(3.39,9.28) v3(3.34,8.85) v3(3.45,40.95) v3(3.47,25.73) v3(3.54,6.37) v3(3.59,3.62) v3(3.59,3.33) v3(3.6,2.99) v3(3.6,2.61) v3(3.6,2.26) v3(3.6,1.9) v3(3.6,1.55) v3(3.59,1.17) v3(3.67,43.58) v3(3.64,39.18) v3(3.71,6.89) v3(3.73,3.83) v3(3.82,40.55) v3(3.81,30.73) v3(3.77,29.01) v3(3.92,7.36) v3(3.92,4.52) v3(3.96,45.87) v3(3.94,42.4) v3(3.94,42) v3(4.02,38.82) v3(3.98,31.61) v3(3.98,23.61) v3(3.98,23.11) v3(3.98,22.61) v3(4,5.51) v3(3.95,4.99) v3(3.93,4.05) v3(3.97,1.03) v3(4.1,43.72) v3(4.1,43.28) v3(4.09,42.87) v3(4.09,30.39) v3(4.07,24.11) v3(4.09,5.98) v3(4.17,41.55) v3(4.19,41.07) v3(4.22,40.17) v3(4.15,22.08) v3(4.14,7.82) v3(4.27,45.87) v3(4.33,40.6) v3(4.33,33.96) v3(4.28,15.2) v3(4.29,14.4) v3(4.29,14.05) v3(4.29,13.69) v3(4.33,8.31) v3(4.23,6.43) v3(4.33,1.03) v3(4.42,38.41) v3(4.41,6.85) v3(4.48,31.61) v3(4.48,24.61) v3(4.48,24.11) v3(4.48,23.11) v3(4.51,22.05) v3(4.52,15.34) v3(4.52,15.03) v3(4.5,9.26) v3(4.45,8.79) v3(4.57,45.87) v3(4.61,39.77) v3(4.57,15.63) v3(4.61,14.4) v3(4.62,14.06) v3(4.63,40.16) v3(4.67,37.91) v3(4.69,37.36) v3(4.68,36.83) v3(4.68,36.37) v3(4.68,35.81) v3(4.69,35.28) v3(4.69,34.8) v3(4.69,34.4) v3(4.65,34.08) v3(4.69,1.03) v3(4.82,15.9) v3(4.76,7.56) v3(4.88,45.87) v3(4.87,27.52) v3(4.87,26.75) v3(4.83,15.61) v3(4.99,39.8) v3(5.01,39.41) v3(4.98,33.11) v3(4.98,30.61) v3(4.98,29.11) v3(4.98,24.11) v3(4.98,23.11) v3(4.96,22.05) v3(4.94,15.34) v3(4.94,15.04) v3(5.01,1.03) v3(5.06,5.21) v3(5.18,45.87) v3(5.15,15.62) v3(5.14,5.71) v3(5.33,43.72) v3(5.32,43.28) v3(5.33,42.87) v3(5.25,41.55) v3(5.33,41.09) v3(5.32,15.36) v3(5.32,15.03) v3(5.31,14.43) v3(5.31,14.07) v3(5.31,13.69) v3(5.3,6.15) v3(5.36,39.41) v3(5.35,39.05) v3(5.4,3.31) v3(5.4,1.9) v3(5.4,1.55) v3(5.4,1.17) v3(5.49,45.87) v3(5.48,42.4) v3(5.48,42) v3(5.48,33.11) v3(5.48,30.11) v3(5.48,26.11) v3(5.48,24.11) v3(5.48,23.61) v3(5.48,23.11) v3(5.48,22.61) v3(5.47,22.05) v3(5.49,6.6) v3(5.6,38.58) v3(5.54,3.82) v3(5.64,40.71) v3(5.66,15.03) v3(5.66,14.43) v3(5.66,14.07) v3(5.66,13.69) v3(5.72,7.04) v3(5.75,43.58) v3(5.77,38.99) v3(5.78,38.05) v3(5.78,37.49) v3(5.78,36.93) v3(5.78,36.37) v3(5.78,35.81) v3(5.78,35.28) v3(5.78,34.8) v3(5.78,34.4) v3(5.77,5.24) v3(5.75,4.58) v3(5.74,4.07) v3(5.77,1.03) v3(5.84,34.05) v3(5.9,7.42) v3(5.9,5.83) v3(5.98,40.35) v3(6,38.54) v3(5.98,33.61) v3(5.98,33.11) v3(5.98,26.11) v3(5.98,25.61) v3(5.98,24.11) v3(5.98,23.11) v3(6.01,22.05) v3(6.09,6.49) v3(6.13,1.03) v3(6.17,43.27) v3(6.17,42.87) v3(6.18,38.05) v3(6.18,37.49) v3(6.18,36.93) v3(6.18,36.37) v3(6.18,35.81) v3(6.18,35.28) v3(6.18,34.8) v3(6.18,34.4) v3(6.14,34.07) v3(6.17,18.43) v3(6.31,45.94) v3(6.31,45.38) v3(6.31,44.82) v3(6.31,44.27) v3(6.32,43.74) v3(6.28,7.15) v3(6.39,42.41) v3(6.37,41.9) v3(6.38,41.44) v3(6.38,40.96) v3(6.36,39.99) v3(6.42,25.64) v3(6.4,7.74) v3(6.48,40.42) v3(6.48,33.11) v3(6.48,24.61) v3(6.48,24.11) v3(6.48,23.11) v3(6.46,22.05) v3(6.49,18.67) v3(6.47,9.26) v3(6.46,8.83) v3(6.45,8.23) v3(6.49,1.03) v3(6.69,39.97) v3(6.72,39.57) v3(6.82,1.03) v3(6.87,16.92) v3(6.87,16.54) v3(6.88,4.62) v3(6.99,39.1) v3(6.98,33.11) v3(6.98,25.11) v3(6.98,24.11) v3(6.98,23.61) v3(6.98,23.11) v3(6.98,22.61) v3(6.97,22.08) v3(7.08,39.5) v3(7.17,38.54) v3(7.2,3.56) v3(7.2,3.28) v3(7.2,2.97) v3(7.2,2.59) v3(7.2,2.23) v3(7.2,1.88) v3(7.2,1.52) v3(7.2,1.14) v3(7.27,38.05) v3(7.27,37.49) v3(7.27,36.93) v3(7.27,36.37) v3(7.27,35.81) v3(7.28,35.28) v3(7.28,34.83) v3(7.28,34.45) v3(7.3,34.07) v3(7.37,39.03) v3(7.38,21.11) v3(7.33,3.81) v3(7.48,42.41) v3(7.48,41.91) v3(7.47,41.46) v3(7.48,40.96) v3(7.48,33.61) v3(7.48,33.11) v3(7.48,25.61) v3(7.48,24.11) v3(7.48,23.11) v3(7.51,22.05) v3(7.55,45.94) v3(7.55,45.38) v3(7.55,44.82) v3(7.55,44.27) v3(7.55,43.74) v3(7.58,38.59) v3(7.58,21.42) v3(7.54,9.27) v3(7.55,8.81) v3(7.55,8.19) v3(7.57,5.25) v3(7.55,4.63) v3(7.56,4.07) v3(7.57,1.03) v3(7.7,43.27) v3(7.7,42.87) v3(7.69,40.48) v3(7.68,38.05) v3(7.68,37.49) v3(7.68,36.93) v3(7.68,36.37) v3(7.68,35.81) v3(7.68,35.28) v3(7.68,34.83) v3(7.68,34.45) v3(7.65,34.08) v3(7.71,12.25) v3(7.69,5.84) v3(7.76,21.11) v3(7.85,6.39) v3(7.93,1.03) v3(7.98,33.11) v3(7.98,26.11) v3(7.98,23.11) v3(7.96,22.05) v3(7.96,21.42) v3(8.01,18.17) v3(7.97,7.45) v3(7.96,6.92) v3(8.12,43.58) v3(8.03,40.08) v3(8.14,21.11) v3(8.3,39.69) v3(8.29,1.03) v3(8.42,45.87) v3(8.39,42.4) v3(8.39,42) v3(8.34,21.42) v3(8.53,39.21) v3(8.48,33.11) v3(8.48,24.61) v3(8.48,24.11) v3(8.48,23.61) v3(8.48,23.11) v3(8.48,22.61) v3(8.5,22.08) v3(8.52,21.11) v3(8.54,43.73) v3(8.54,43.3) v3(8.54,42.87) v3(8.62,41.55) v3(8.61,41.01) v3(8.61,40.5) v3(8.72,45.87) v3(8.67,40) v3(8.71,38.63) v3(8.7,21.39) v3(8.66,4.53) v3(8.64,1.03) v3(8.76,39.55) v3(8.77,38.05) v3(8.77,37.49) v3(8.77,36.93) v3(8.77,36.37) v3(8.77,35.81) v3(8.77,35.28) v3(8.77,34.8) v3(8.77,34.42) v3(8.82,34.06) v3(8.91,39.04) v3(8.9,21.11) v3(8.92,3.49) v3(9.03,45.87) v3(8.98,33.61) v3(8.98,33.11) v3(8.98,25.11) v3(8.98,24.11) v3(8.98,23.11) v3(9.01,22.05) v3(9,6.35) v3(8.97,3.24) v3(9,1.9) v3(9,1.55) v3(9,1.17) v3(9.05,38.58) v3(9.11,38.07) v3(9.08,21.39) v3(9.05,18.18) v3(9.05,17.57) v3(9.05,16.96) v3(9.09,7.43) v3(9.07,6.89) v3(9.18,37.49) v3(9.18,36.93) v3(9.18,36.37) v3(9.18,35.81) v3(9.18,35.28) v3(9.18,34.8) v3(9.18,34.42) v3(9.14,34.08) v3(9.28,21.11) v3(9.33,45.87) v3(9.43,3.1) v3(9.43,2.6) v3(9.41,2.01) v3(9.41,1.5) v3(9.41,0.99) v3(9.48,33.11) v3(9.48,25.61) v3(9.48,24.11) v3(9.48,23.11) v3(9.46,22.05) v3(9.49,21.39) v3(9.56,19.26) v3(9.56,18.7) v3(9.64,45.87) v3(9.7,41.55) v3(9.71,41.01) v3(9.72,40.49) v3(9.66,21.11) v3(9.78,43.73) v3(9.78,43.3) v3(9.78,42.87) v3(9.8,39.97) v3(9.82,16.01) v3(9.74,15.27) v3(9.93,42.4) v3(9.93,42) v3(9.92,39.49) v3(9.87,21.39) v3(9.85,18.97) v3(9.89,17.99) v3(9.89,17.35) v3(9.87,16.69) v3(9.94,45.87) v3(9.98,33.11) v3(9.98,26.11) v3(9.98,25.61) v3(9.98,24.11) v3(9.98,23.61) v3(9.98,23.11) v3(9.98,22.61) v3(9.97,22.1) v3(10.09,38.97) v3(10.2,43.58) v3(10.21,38.51) v3(10.28,38.01) v3(10.3,37.49) v3(10.3,36.93) v3(10.3,36.37) v3(10.3,35.81) v3(10.3,35.28) v3(10.3,34.8) v3(10.27,34.4) v3(10.33,34.05) v3(10.27,19.38) v3(10.48,33.61) v3(10.48,33.11) v3(10.48,26.11) v3(10.48,25.61) v3(10.48,23.61) v3(10.48,23.11) v3(10.48,22.61) v3(10.48,22.1) v3(10.62,43.27) v3(10.62,42.87) v3(10.58,18.04) v3(10.55,17.3) v3(10.55,16.62) v3(10.55,15.98) v3(10.63,15.29) v3(10.71,40.24) v3(10.67,39.68) v3(10.67,39.09) v3(10.67,38.52) v3(10.67,38) v3(10.68,37.49) v3(10.68,36.93) v3(10.68,36.37) v3(10.68,35.81) v3(10.68,35.28) v3(10.65,34.8) v3(10.68,34.4) v3(10.63,34.07) v3(10.72,18.96) v3(10.76,45.94) v3(10.76,45.38) v3(10.76,44.82) v3(10.76,44.27) v3(10.77,43.74) v3(10.83,41.91) v3(10.81,41.37) v3(10.76,40.82) v3(10.84,42.41) v3(10.98,33.11) v3(10.98,26.11) v3(10.98,25.61) v3(10.98,24.11) v3(10.98,23.11) v3(11.01,22.05) v3(10.98,18.19) v3(11.04,19.23) v3(11.04,18.72) v3(11.48,33.11) v3(11.48,24.11) v3(11.48,23.11) v3(11.46,22.05) v3(11.52,19.11) v3(11.52,18.5) v3(11.52,17.89) v3(11.44,3.03) v3(11.44,2.52) v3(11.44,2.01) v3(11.44,1.5) v3(11.44,0.99) v3(11.71,6.47) v3(11.82,40.19) v3(11.79,39.62) v3(11.77,39.11) v3(11.77,38.55) v3(11.77,38.02) v3(11.8,37.46) v3(11.78,36.9) v3(11.78,36.34) v3(11.77,35.79) v3(11.77,35.26) v3(11.77,34.8) v3(11.8,34.45) v3(11.82,34.06) v3(11.93,42.41) v3(11.91,41.33) v3(11.85,40.7) v3(11.85,21.09) v3(12,45.94) v3(12,45.38) v3(12,44.82) v3(12,44.27) v3(12,43.74) v3(11.94,41.93) v3(11.98,33.61) v3(11.98,33.11) v3(11.98,24.61) v3(11.98,24.11) v3(11.98,23.61) v3(11.98,23.11) v3(11.98,22.61) v3(11.98,22.1) v3(12.03,3.23) v3(12,1.95) v3(12,1.6) v3(12,1.22) v3(12.05,21.31) v3(12.1,5.65) v3(12.06,3.51) v3(12.15,43.27) v3(12.15,42.87) v3(12.18,36.9) v3(12.18,36.35) v3(12.18,35.79) v3(12.18,35.26) v3(12.15,34.8) v3(12.15,34.45) v3(12.15,34.08) v3(12.13,3.83) v3(12.26,37.4) v3(12.25,21.09) v3(12.25,5.09) v3(12.34,37.89) v3(12.34,4.57) v3(12.36,4.06) v3(12.37,1.03) v3(12.45,38.36) v3(12.48,33.11) v3(12.48,25.11) v3(12.48,24.11) v3(12.48,23.11) v3(12.51,22.05) v3(12.48,21.31) v3(12.57,43.58) v3(12.59,38.84) v3(12.58,9.26) v3(12.59,8.81) v3(12.58,8.34) v3(12.71,21.09) v3(12.73,1.03) v3(12.76,39.32) v3(12.86,45.87) v3(12.84,42.4) v3(12.84,42) v3(12.87,39.76) v3(12.99,43.73) v3(12.99,43.3) v3(12.99,42.87) v3(12.98,40.2) v3(12.98,33.11) v3(12.98,24.11) v3(12.98,23.11) v3(12.96,22.05) v3(12.94,21.31) v3(13.07,41.55) v3(13.07,41.08) v3(13.07,40.66) v3(13.05,18.09) v3(13.09,1.03) v3(13.16,45.87) v3(13.17,21.09) v3(13.2,5.85) v3(13.29,36.93) v3(13.29,36.37) v3(13.29,35.81) v3(13.3,35.28) v3(13.3,34.78) v3(13.27,34.42) v3(13.31,34.06) v3(13.27,7.13) v3(13.39,37.5) v3(13.35,5.29) v3(13.42,1.03) v3(13.47,45.87) v3(13.48,37.96) v3(13.48,33.61) v3(13.48,33.11) v3(13.48,24.11) v3(13.48,23.61) v3(13.48,23.11) v3(13.48,22.61) v3(13.47,22.08) v3(13.49,6.68) v3(13.61,38.42) v3(13.63,34.08) v3(13.7,37.49) v3(13.68,36.93) v3(13.68,36.37) v3(13.68,35.81) v3(13.68,35.28) v3(13.68,34.78) v3(13.68,34.42) v3(13.77,45.87) v3(13.76,38.87) v3(13.82,38) v3(13.77,6.2) v3(13.8,3.56) v3(13.81,3.27) v3(13.8,2.97) v3(13.8,2.61) v3(13.8,2.26) v3(13.8,1.9) v3(13.8,1.55) v3(13.8,1.17) v3(13.92,39.28) v3(13.98,33.11) v3(13.98,26.61) v3(13.98,24.11) v3(13.98,23.11) v3(14.01,22.05) v3(13.96,5.7) v3(13.94,3.85) v3(14.08,45.87) v3(14.13,40.22) v3(14.06,39.77) v3(14.04,38.5) v3(14.08,5.23) v3(14.23,43.73) v3(14.23,42.87) v3(14.15,41.55) v3(14.15,41.08) v3(14.15,40.65) v3(14.14,4.68) v3(14.16,4.07) v3(14.17,1.03) v3(14.24,43.3) v3(14.31,38.96) v3(14.38,45.87) v3(14.38,42.4) v3(14.38,42) v3(14.48,33.11) v3(14.48,24.11) v3(14.48,23.11) v3(14.46,22.05) v3(14.53,1.03) v3(14.63,39.36) v3(14.55,18.96) v3(14.57,18.32) v3(14.55,9.27) v3(14.55,8.82) v3(14.56,8.32) v3(14.65,43.58) v3(14.82,37.48) v3(14.79,36.93) v3(14.79,36.37) v3(14.79,35.81) v3(14.79,35.28) v3(14.79,34.78) v3(14.79,34.42) v3(14.8,26.77) v3(14.77,14.37) v3(14.77,13.99) v3(14.77,13.61) v3(14.84,34.05) v3(14.9,15.1) v3(14.89,1.03) v3(14.95,39.8) v3(15.01,38.02) v3(14.98,33.61) v3(14.98,33.11) v3(14.98,25.61) v3(14.98,24.11) v3(14.98,23.61) v3(14.98,23.11) v3(14.98,22.61) v3(14.97,22.05) v3(15.07,43.27) v3(15.07,42.87) v3(15.13,14.37) v3(15.13,13.99) v3(15.13,13.61) v3(15.09,5.76) v3(15.21,45.94) v3(15.21,45.38) v3(15.21,44.82) v3(15.21,44.27) v3(15.22,43.74) v3(15.18,40.28) v3(15.21,36.94) v3(15.17,36.37) v3(15.17,35.81) v3(15.18,35.28) v3(15.18,34.78) v3(15.15,34.42) v3(15.16,34.08) v3(15.19,5.21) v3(15.21,1.02) v3(15.29,42.41) v3(15.29,41.92) v3(15.28,41.36) v3(15.27,40.79) v3(15.28,15.48) v3(15.28,15.1) v3(15.35,38.49) v3(15.33,37.46) v3(15.36,5.99) v3(15.48,33.11) v3(15.48,24.11) v3(15.48,23.11) v3(15.51,22.05) v3(15.56,37.95) v3(15.62,9.26) v3(15.61,3.26) v3(15.6,2.97) v3(15.6,2.61) v3(15.6,2.26) v3(15.6,1.9) v3(15.6,1.55) v3(15.6,1.17) v3(15.69,38.89) v3(15.66,15.87) v3(15.66,15.48) v3(15.66,15.1) v3(15.73,14.46) v3(15.72,14.04) v3(15.72,13.51) v3(15.63,8.84) v3(15.64,8.36) v3(15.69,7.93) v3(15.65,5.56) v3(15.72,3.78) v3(15.81,7.5) v3(15.85,38.4) v3(15.92,14.23) v3(15.89,13.78) v3(15.85,5.07) v3(15.97,39.31) v3(15.98,33.11) v3(15.98,32.11) v3(15.98,24.11) v3(15.98,23.11) v3(15.96,22.05) v3(16.01,7.04) v3(15.94,4.59) v3(15.96,4.06) v3(15.97,1.03) v3(16.09,18.93) v3(16.04,15.87) v3(16.04,15.48) v3(16.04,15.1) v3(16.11,13.52) v3(16.19,39.81) v3(16.23,38.77) v3(16.13,14.46) v3(16.13,13.98) v3(16.16,7.39) v3(16.33,40.31) v3(16.3,36.82) v3(16.27,36.25) v3(16.26,35.7) v3(16.27,35.29) v3(16.27,34.87) v3(16.27,34.49) v3(16.28,6.62) v3(16.33,1.03) v3(16.38,42.41) v3(16.38,41.93) v3(16.38,41.38) v3(16.38,40.87) v3(16.33,34.04) v3(16.39,22.08) v3(16.39,6.91) v3(16.46,45.94) v3(16.46,45.38) v3(16.46,44.82) v3(16.46,44.27) v3(16.45,43.74) v3(16.45,37.26) v3(16.48,33.61) v3(16.48,33.11) v3(16.48,32.61) v3(16.48,32.11) v3(16.48,27.11) v3(16.48,24.11) v3(16.48,23.61) v3(16.48,22.61) v3(16.6,43.27) v3(16.6,42.87) v3(16.61,39.16) v3(16.55,6.22) v3(16.67,37.66) v3(16.71,30.2) v3(16.69,6.47) v3(16.69,1.03) v3(16.79,5.68) v3(16.9,26.27) v3(17.02,43.58) v3(17.01,39.57) v3(16.99,38) v3(16.98,23.61) v3(16.98,23.11) v3(16.98,22.61) v3(17.01,6.05) v3(17,1.03) v3(17.13,18.92) v3(17.19,21.88) v3(17.29,45.86) v3(17.29,42.4) v3(17.29,42) v3(17.35,40.01) v3(17.35,38.35) v3(17.35,7.43) v3(17.38,5.64) v3(17.4,3.27) v3(17.4,1.9) v3(17.4,1.55) v3(17.4,1.17) v3(17.44,43.73) v3(17.44,43.3) v3(17.44,42.87) v3(17.52,41.55) v3(17.51,41.07) v3(17.5,40.54) v3(17.6,45.86) v3(17.61,18.6) v3(17.59,9.94) v3(17.53,3.8) v3(17.69,38.69) v3(17.65,7.01) v3(17.66,5.14) v3(17.71,4.01) v3(17.8,29.71) v3(17.76,4.59) v3(17.77,1.03) v3(17.9,45.86) v3(17.91,22.65) v3(18.03,39.02) v3(18.02,10.24) v3(18,6.61) v3(18.07,17.36) v3(18.07,16.97) v3(18.08,16.63) v3(18.05,9.81) v3(18.13,1.03) v3(18.21,45.86) v3(18.22,24.36) v3(18.2,23.03) v3(18.33,39.47) v3(18.41,18.34) v3(18.43,9.55) v3(18.51,45.86) v3(18.52,39.98) v3(18.49,1.03) v3(18.6,41.55) v3(18.61,41.04) v3(18.6,40.54) v3(18.55,9.94) v3(18.68,43.73) v3(18.68,43.3) v3(18.68,42.82) v3(18.82,45.86) v3(18.83,42) v3(18.81,1.04) v3(18.84,42.46) v3(18.99,25.59) v3(18.94,24.9) v3(18.97,24.08) v3(18.93,9.68) v3(19.1,43.58) v3(19.19,3.18) v3(19.2,2.9) v3(19.2,2.61) v3(19.2,2.26) v3(19.2,1.9) v3(19.2,1.55) v3(19.2,1.17) v3(20.02,28.84) v3(20,28.22) v3(20.13,39.71) v3(20.13,39.15) v3(20.13,38.59) v3(20.13,38.03) v3(20.13,37.47) v3(20.13,36.91) v3(20.13,36.35) v3(20.13,35.79) v3(20.13,35.23) v3(20.19,44.7) v3(20.18,44.09) v3(20.2,43.44) v3(20.18,41.75) v3(20.19,41) v3(20.2,40.29) v4(0.49,40.23) v4(0.51,34.55) v4(0.51,33.87) v4(0.51,33.23) v4(0.51,32.53) v4(0.51,31.81) v4(0.5,31.21) v4(0.61,20.35) v4(0.61,19.45) v4(0.61,18.54) v4(0.61,17.53) v4(0.61,16.64) v4(0.62,15.69) v4(0.68,11.74) v4(0.67,10.82) v4(0.76,28.13) v4(0.76,27.5) v4(0.75,26.89) v4(0.86,30.59) v4(0.89,28.64) v4(0.92,21.73) v4(0.89,21.32) v4(1.03,26.06) v4(1.03,25.43) v4(1.03,24.67) v4(1.03,24.03) v4(1.03,23.4) v4(1,22.76) v4(1.39,15.28) v4(1.72,42.87) v4(1.66,18.5) v4(1.66,18.19) v4(1.66,17.89) v4(1.66,10.06) v4(1.79,17.42) v4(1.79,17.11) v4(1.79,16.81) v4(1.82,3.23) v4(1.8,2.94) v4(1.8,2.56) v4(1.8,2.21) v4(1.8,1.85) v4(1.8,1.5) v4(1.8,1.11) v4(1.92,25.3) v4(1.92,20.22) v4(1.92,19.71) v4(1.9,3.77) v4(1.85,3.51) v4(1.94,42.41) v4(1.96,18.5) v4(1.96,18.19) v4(1.96,17.89) v4(2.1,17.42) v4(2.1,17.11) v4(2.1,16.81) v4(2.07,14.59) v4(2.14,43.22) v4(2.14,4.03) v4(2.17,1.03) v4(2.3,42.4) v4(2.27,18.5) v4(2.27,18.19) v4(2.27,17.89) v4(2.4,23.5) v4(2.4,17.42) v4(2.4,17.11) v4(2.4,16.81) v4(2.34,3.19) v4(2.52,43.22) v4(2.53,1.03) v4(2.65,42.4) v4(2.69,12) v4(2.79,3.19) v4(2.88,43.22) v4(2.89,1.03) v4(3.03,42.41) v4(2.93,18.83) v4(2.93,18.32) v4(2.93,17.68) v4(2.99,14.02) v4(2.99,13.51) v4(2.99,13) v4(3.12,27.73) v4(3.06,16.16) v4(3.06,15.27) v4(3.22,1.03) v4(3.25,43.27) v4(3.25,42.87) v4(3.26,3.19) v4(3.41,13.48) v4(3.43,13.01) v4(3.42,12.53) v4(3.42,12.09) v4(3.44,22.64) v4(3.44,18.83) v4(3.44,18.32) v4(3.53,16.34) v4(3.47,15.74) v4(3.44,15.13) v4(3.45,14.51) v4(3.43,14.02) v4(3.57,24.41) v4(3.57,23.78) v4(3.57,23.27) v4(3.61,16.94) v4(3.57,10.62) v4(3.59,3.62) v4(3.59,3.33) v4(3.6,2.99) v4(3.6,2.61) v4(3.6,2.26) v4(3.6,1.9) v4(3.6,1.55) v4(3.59,1.17) v4(3.67,43.58) v4(3.71,17.55) v4(3.73,3.83) v4(3.77,29.01) v4(3.82,27.2) v4(3.83,18.15) v4(3.77,9.76) v4(3.88,28.23) v4(3.92,10.62) v4(3.96,45.87) v4(3.94,42.4) v4(3.94,42) v4(3.98,23.61) v4(3.98,23.11) v4(3.98,22.61) v4(4.02,19.25) v4(3.94,18.75) v4(3.93,4.05) v4(3.97,1.03) v4(4.1,43.72) v4(4.09,42.87) v4(4.07,24.11) v4(4.12,20.2) v4(4.09,19.74) v4(4.13,9.76) v4(4.17,41.55) v4(4.15,22.08) v4(4.2,21.7) v4(4.19,21.21) v4(4.16,20.71) v4(4.14,3.19) v4(4.27,45.87) v4(4.32,42.4) v4(4.33,33.96) v4(4.28,10.62) v4(4.33,1.03) v4(4.52,41.54) v4(4.48,24.61) v4(4.48,24.11) v4(4.48,23.11) v4(4.52,15.34) v4(4.52,15.03) v4(4.5,14.61) v4(4.49,14.09) v4(4.48,13.28) v4(4.49,12.63) v4(4.49,11.88) v4(4.57,45.87) v4(4.6,16.47) v4(4.55,15.91) v4(4.59,3.19) v4(4.68,42.4) v4(4.69,34.4) v4(4.65,34.08) v4(4.65,16.94) v4(4.69,1.03) v4(4.74,17.44) v4(4.88,45.87) v4(4.88,41.54) v4(4.87,18.04) v4(5.03,42.4) v4(4.98,33.11) v4(4.98,24.11) v4(4.98,23.11) v4(4.97,18.64) v4(4.99,17.1) v4(4.95,16.53) v4(4.95,15.93) v4(4.94,15.34) v4(4.94,15.04) v4(4.95,14.68) v4(4.95,14.2) v4(4.96,13.73) v4(4.96,13.23) v4(4.95,12.66) v4(4.97,11.92) v4(4.96,11.51) v4(4.96,11.04) v4(4.96,10.61) v4(4.96,10.11) v4(5.01,1.03) v4(5.07,34.17) v4(5.07,19.2) v4(5.1,18.31) v4(5.04,17.71) v4(5.09,8.84) v4(5.07,3.19) v4(5.18,45.87) v4(5.22,20.79) v4(5.2,20.3) v4(5.15,19.78) v4(5.2,18.91) v4(5.33,43.72) v4(5.33,42.87) v4(5.25,41.55) v4(5.27,21.72) v4(5.25,21.27) v4(5.3,19.48) v4(5.29,7.98) v4(5.42,34.17) v4(5.43,20) v4(5.4,3.31) v4(5.4,1.9) v4(5.4,1.55) v4(5.4,1.17) v4(5.49,45.87) v4(5.48,42.4) v4(5.48,42) v4(5.48,33.11) v4(5.48,24.11) v4(5.48,23.61) v4(5.48,23.11) v4(5.48,22.61) v4(5.47,22.05) v4(5.52,20.5) v4(5.45,8.84) v4(5.56,30.35) v4(5.6,20.97) v4(5.54,3.82) v4(5.7,21.87) v4(5.67,21.49) v4(5.65,7.98) v4(5.75,43.58) v4(5.78,34.4) v4(5.8,8.84) v4(5.74,4.07) v4(5.77,1.03) v4(5.84,34.05) v4(5.98,33.61) v4(5.98,33.11) v4(5.98,24.11) v4(5.98,23.11) v4(6.01,16.61) v4(6.01,16.01) v4(6.01,15.4) v4(6.01,14.79) v4(5.98,14.38) v4(6.01,13.57) v4(6.01,12.96) v4(6.01,12.35) v4(6.01,11.74) v4(6,11.05) v4(6.01,10.61) v4(6.01,10.14) v4(5.95,3.19) v4(6.1,17.83) v4(6.05,17.22) v4(6.13,1.03) v4(6.17,43.27) v4(6.17,42.87) v4(6.18,34.4) v4(6.14,34.07) v4(6.17,18.43) v4(6.32,43.74) v4(6.26,18.9) v4(6.39,42.41) v4(6.42,25.64) v4(6.35,19.33) v4(6.39,3.19) v4(6.48,33.11) v4(6.48,24.11) v4(6.48,23.11) v4(6.46,19.84) v4(6.51,19.07) v4(6.49,18.67) v4(6.49,18.02) v4(6.49,17.42) v4(6.49,16.81) v4(6.49,16.2) v4(6.49,15.59) v4(6.49,14.98) v4(6.49,14.37) v4(6.46,13.64) v4(6.49,13.15) v4(6.49,12.54) v4(6.49,11.93) v4(6.49,1.03) v4(6.54,43.27) v4(6.54,34.17) v4(6.58,20.35) v4(6.59,19.55) v4(6.62,10.62) v4(6.68,20.89) v4(6.71,20.04) v4(6.75,42.4) v4(6.74,37.62) v4(6.74,37.11) v4(6.75,21.85) v4(6.75,21.39) v4(6.82,9.76) v4(6.82,1.03) v4(6.9,43.27) v4(6.9,34.17) v4(6.87,20.5) v4(6.87,3.19) v4(6.98,33.11) v4(6.98,24.11) v4(6.98,23.61) v4(6.98,23.11) v4(6.98,22.61) v4(6.97,22.08) v4(6.97,10.62) v4(7.1,42.4) v4(7.05,21) v4(7.17,21.59) v4(7.17,9.76) v4(7.2,3.56) v4(7.2,3.28) v4(7.2,2.97) v4(7.2,2.59) v4(7.2,2.23) v4(7.2,1.88) v4(7.2,1.52) v4(7.2,1.14) v4(7.26,43.27) v4(7.28,34.45) v4(7.3,34.07) v4(7.33,10.62) v4(7.33,3.81) v4(7.48,42.41) v4(7.48,33.61) v4(7.48,33.11) v4(7.48,24.11) v4(7.48,23.11) v4(7.53,18.63) v4(7.52,18.02) v4(7.52,17.41) v4(7.52,16.8) v4(7.52,16.19) v4(7.52,15.58) v4(7.52,14.97) v4(7.52,14.37) v4(7.52,13.76) v4(7.52,13.15) v4(7.52,12.54) v4(7.52,11.93) v4(7.55,43.74) v4(7.59,19.24) v4(7.57,5.25) v4(7.56,4.07) v4(7.57,1.03) v4(7.7,43.27) v4(7.7,42.87) v4(7.68,34.45) v4(7.65,34.08) v4(7.69,5.84) v4(7.73,3.19) v4(7.74,19.84) v4(7.85,6.39) v4(7.93,1.03) v4(7.98,33.11) v4(7.98,23.11) v4(7.97,20.4) v4(8,18.91) v4(8.01,18.17) v4(8.01,17.57) v4(8.01,16.96) v4(8.01,16.35) v4(8.01,15.74) v4(8.01,15.13) v4(8.01,14.52) v4(8.01,13.91) v4(8.01,13.3) v4(8.01,12.69) v4(8.01,12.08) v4(7.97,11.66) v4(8.01,11.06) v4(8.01,10.6) v4(8,10.1) v4(7.97,7.45) v4(7.96,6.92) v4(8.12,43.58) v4(8.04,34.17) v4(8.04,19.55) v4(8.15,20.98) v4(8.16,20.06) v4(8.14,8.84) v4(8.17,3.19) v4(8.27,38.13) v4(8.27,37.62) v4(8.27,37.11) v4(8.24,21.59) v4(8.29,1.03) v4(8.42,45.87) v4(8.39,42.4) v4(8.39,42) v4(8.39,34.17) v4(8.39,20.63) v4(8.34,7.98) v4(8.48,33.11) v4(8.48,24.11) v4(8.48,23.61) v4(8.48,23.11) v4(8.48,22.61) v4(8.5,22.08) v4(8.5,8.84) v4(8.54,43.73) v4(8.54,42.87) v4(8.62,41.55) v4(8.6,21.13) v4(8.72,45.87) v4(8.69,21.73) v4(8.7,7.98) v4(8.65,3.19) v4(8.64,1.03) v4(8.77,42.4) v4(8.77,34.42) v4(8.82,34.06) v4(8.85,8.84) v4(8.92,3.49) v4(9.03,45.87) v4(8.97,41.54) v4(8.98,33.61) v4(8.98,33.11) v4(8.98,24.11) v4(8.98,23.11) v4(9,6.35) v4(8.97,3.24) v4(9,1.9) v4(9,1.55) v4(9,1.17) v4(9.13,42.4) v4(9.09,19.38) v4(9.06,18.81) v4(9.05,18.18) v4(9.05,17.57) v4(9.05,16.96) v4(9.05,16.35) v4(9.05,15.74) v4(9.06,15.13) v4(9.05,14.56) v4(9.05,13.91) v4(9.05,13.3) v4(9.05,12.69) v4(9.05,12.08) v4(9.06,11.61) v4(9.06,11.09) v4(9.05,10.6) v4(9.05,10.1) v4(9.09,7.43) v4(9.07,6.89) v4(9.18,34.42) v4(9.14,34.08) v4(9.33,41.54) v4(9.24,19.98) v4(9.33,45.87) v4(9.43,3.1) v4(9.43,2.6) v4(9.41,2.01) v4(9.41,1.5) v4(9.41,0.99) v4(9.48,42.4) v4(9.48,33.11) v4(9.48,24.11) v4(9.48,23.11) v4(9.51,20.53) v4(9.54,34.17) v4(9.54,18.32) v4(9.54,17.68) v4(9.54,17.05) v4(9.54,16.41) v4(9.54,15.65) v4(9.64,45.87) v4(9.7,41.55) v4(9.66,38.13) v4(9.66,37.62) v4(9.66,37.11) v4(9.69,21.11) v4(9.66,13.36) v4(9.66,12.6) v4(9.78,43.73) v4(9.78,42.87) v4(9.76,21.72) v4(9.79,19.97) v4(9.93,42.4) v4(9.93,42) v4(9.89,34.17) v4(9.94,45.87) v4(9.98,33.11) v4(9.98,24.11) v4(9.98,23.61) v4(9.98,23.11) v4(9.98,22.61) v4(9.97,22.1) v4(10.2,43.58) v4(10.17,18.32) v4(10.17,17.68) v4(10.17,16.92) v4(10.17,16.29) v4(10.17,15.65) v4(10.27,34.4) v4(10.33,34.05) v4(10.3,13.36) v4(10.3,12.6) v4(10.43,18.7) v4(10.48,33.61) v4(10.48,33.11) v4(10.48,23.61) v4(10.48,23.11) v4(10.48,22.61) v4(10.48,22.1) v4(10.62,43.27) v4(10.62,42.87) v4(10.68,34.4) v4(10.63,34.07) v4(10.7,21.84) v4(10.73,21.46) v4(10.77,43.74) v4(10.83,21.06) v4(10.81,13.36) v4(10.81,12.6) v4(10.84,42.41) v4(11,43.27) v4(10.98,33.11) v4(10.98,24.11) v4(10.98,23.11) v4(11,20.66) v4(10.93,17.68) v4(10.93,16.92) v4(10.93,16.29) v4(10.93,15.65) v4(10.96,8.36) v4(10.93,7.32) v4(10.93,6.15) v4(10.96,5.13) v4(11.04,34.17) v4(11.2,42.4) v4(11.19,38.13) v4(11.19,37.62) v4(11.19,37.11) v4(11.3,20.18) v4(11.35,43.27) v4(11.39,34.17) v4(11.48,33.11) v4(11.48,24.11) v4(11.48,23.11) v4(11.49,19.7) v4(11.52,19.11) v4(11.52,18.5) v4(11.52,17.89) v4(11.52,17.28) v4(11.52,16.67) v4(11.52,16.06) v4(11.52,15.45) v4(11.52,14.84) v4(11.52,14.23) v4(11.52,13.62) v4(11.52,13.01) v4(11.52,12.46) v4(11.51,11.93) v4(11.44,3.03) v4(11.44,2.52) v4(11.44,2.01) v4(11.44,1.5) v4(11.44,0.99) v4(11.55,42.4) v4(11.71,43.27) v4(11.67,10.62) v4(11.8,34.45) v4(11.82,34.06) v4(11.75,21.85) v4(11.93,42.41) v4(11.85,21.4) v4(11.87,9.76) v4(12,43.74) v4(11.98,33.61) v4(11.98,33.11) v4(11.98,24.11) v4(11.98,23.61) v4(11.98,23.11) v4(11.98,22.61) v4(11.98,22.1) v4(12.03,10.62) v4(12.03,3.23) v4(12,1.95) v4(12,1.6) v4(12,1.22) v4(12.06,3.51) v4(12.15,43.27) v4(12.15,42.87) v4(12.15,34.45) v4(12.15,34.08) v4(12.22,21.6) v4(12.15,20.82) v4(12.23,9.76) v4(12.13,3.83) v4(12.31,21.13) v4(12.43,20.29) v4(12.38,10.62) v4(12.36,4.06) v4(12.37,1.03) v4(12.48,33.11) v4(12.48,24.11) v4(12.48,23.11) v4(12.49,20.66) v4(12.57,43.58) v4(12.56,34.19) v4(12.53,19.7) v4(12.56,19.11) v4(12.56,18.5) v4(12.56,17.89) v4(12.56,17.28) v4(12.56,16.67) v4(12.56,16.06) v4(12.56,15.45) v4(12.56,14.84) v4(12.56,14.23) v4(12.56,13.62) v4(12.56,13.01) v4(12.56,12.46) v4(12.57,11.93) v4(12.55,3.19) v4(12.71,38.13) v4(12.71,37.62) v4(12.71,37.11) v4(12.73,1.03) v4(12.78,20.09) v4(12.86,45.87) v4(12.84,42.4) v4(12.84,42) v4(12.91,34.19) v4(12.99,43.73) v4(12.99,42.87) v4(12.98,33.11) v4(12.98,24.11) v4(12.98,23.11) v4(12.99,19.49) v4(13.03,18.74) v4(13,3.19) v4(13.07,41.55) v4(13.05,18.09) v4(13.05,17.48) v4(13.05,16.87) v4(13.05,16.26) v4(13.05,15.71) v4(13.05,15.04) v4(13.05,14.43) v4(13.05,13.82) v4(13.05,13.21) v4(13.05,12.6) v4(13.05,12.12) v4(13.04,11.64) v4(13.04,11.05) v4(13.04,10.58) v4(13.04,10.14) v4(13.09,1.03) v4(13.16,45.87) v4(13.22,42.4) v4(13.18,8.84) v4(13.27,34.42) v4(13.31,34.06) v4(13.27,21.59) v4(13.42,41.54) v4(13.38,7.98) v4(13.42,1.03) v4(13.47,45.87) v4(13.48,33.61) v4(13.48,33.11) v4(13.48,24.11) v4(13.48,23.61) v4(13.48,23.11) v4(13.48,22.61) v4(13.47,22.08) v4(13.52,21) v4(13.53,8.84) v4(13.47,3.19) v4(13.58,42.4) v4(13.63,34.08) v4(13.68,34.42) v4(13.71,21.84) v4(13.77,45.87) v4(13.78,41.54) v4(13.76,21.34) v4(13.76,20.49) v4(13.73,7.98) v4(13.8,3.56) v4(13.81,3.27) v4(13.8,2.97) v4(13.8,2.61) v4(13.8,2.26) v4(13.8,1.9) v4(13.8,1.55) v4(13.8,1.17) v4(13.93,42.4) v4(13.89,8.84) v4(13.98,33.11) v4(13.98,24.11) v4(13.98,23.11) v4(13.94,20.84) v4(13.97,19.91) v4(13.94,3.85) v4(14.08,45.87) v4(14.06,34.19) v4(14.07,19.31) v4(14.09,18.7) v4(14.08,18.09) v4(14.08,17.48) v4(14.08,16.87) v4(14.08,16.26) v4(14.08,15.65) v4(14.08,15.06) v4(14.08,14.43) v4(14.08,13.83) v4(14.08,13.22) v4(14.08,12.61) v4(14.09,12.12) v4(14.08,11.64) v4(14.08,11.25) v4(14.08,10.77) v4(14.08,10.33) v4(14.23,43.73) v4(14.23,42.87) v4(14.15,41.55) v4(14.16,4.07) v4(14.17,1.03) v4(14.24,38.13) v4(14.24,37.62) v4(14.24,37.11) v4(14.25,20.35) v4(14.33,3.19) v4(14.38,45.87) v4(14.38,42.4) v4(14.38,42) v4(14.41,34.19) v4(14.48,33.11) v4(14.48,24.11) v4(14.48,23.11) v4(14.48,19.71) v4(14.53,1.03) v4(14.55,18.96) v4(14.57,18.32) v4(14.57,17.71) v4(14.57,17.1) v4(14.57,16.49) v4(14.55,15.88) v4(14.55,15.27) v4(14.57,14.66) v4(14.57,14.05) v4(14.57,13.44) v4(14.57,12.83) v4(14.57,12.28) v4(14.57,11.73) v4(14.65,43.58) v4(14.79,34.42) v4(14.75,21.75) v4(14.74,10.37) v4(14.78,3.19) v4(14.84,34.05) v4(14.93,21.22) v4(14.9,9.48) v4(14.89,1.03) v4(14.98,33.61) v4(14.98,33.11) v4(14.98,24.11) v4(14.98,23.61) v4(14.98,23.11) v4(14.98,22.61) v4(14.97,22.05) v4(15.07,43.27) v4(15.07,42.87) v4(15.1,10.37) v4(15.22,43.74) v4(15.15,34.42) v4(15.16,34.08) v4(15.2,21.57) v4(15.21,1.02) v4(15.29,42.41) v4(15.32,21.08) v4(15.24,20.7) v4(15.25,9.48) v4(15.25,3.19) v4(15.45,43.27) v4(15.48,33.11) v4(15.48,24.11) v4(15.48,23.11) v4(15.46,20.13) v4(15.45,10.37) v4(15.56,34.22) v4(15.57,20.52) v4(15.59,19.54) v4(15.61,18.93) v4(15.61,18.32) v4(15.61,17.71) v4(15.61,17.1) v4(15.61,16.49) v4(15.62,15.86) v4(15.62,15.25) v4(15.62,14.64) v4(15.62,14.03) v4(15.61,13.44) v4(15.62,12.83) v4(15.61,12.28) v4(15.61,11.75) v4(15.61,3.26) v4(15.6,2.97) v4(15.6,2.61) v4(15.6,2.26) v4(15.6,1.9) v4(15.6,1.55) v4(15.6,1.17) v4(15.69,42.42) v4(15.72,3.78) v4(15.8,43.27) v4(15.81,7.5) v4(15.91,34.19) v4(15.86,19.98) v4(15.92,14.23) v4(15.89,13.78) v4(16.02,42.41) v4(15.98,33.11) v4(15.98,32.11) v4(15.98,24.11) v4(15.98,23.11) v4(16.01,19.47) v4(16.01,7.04) v4(15.96,4.06) v4(15.97,1.03) v4(16.09,18.93) v4(16.09,18.32) v4(16.09,17.71) v4(16.09,17.1) v4(16.09,16.49) v4(16.08,15.85) v4(16.08,15.24) v4(16.08,14.63) v4(16.09,14) v4(16.08,13.43) v4(16.08,12.81) v4(16.09,12.22) v4(16.08,11.64) v4(16.1,11.27) v4(16.1,10.81) v4(16.09,10.32) v4(16.16,43.27) v4(16.22,8.84) v4(16.13,3.19) v4(16.32,21.64) v4(16.28,6.62) v4(16.33,1.03) v4(16.38,42.41) v4(16.33,34.04) v4(16.39,22.08) v4(16.43,7.98) v4(16.45,43.74) v4(16.48,33.61) v4(16.48,33.11) v4(16.48,32.61) v4(16.48,32.11) v4(16.48,24.11) v4(16.48,23.61) v4(16.48,22.61) v4(16.43,21.15) v4(16.6,43.27) v4(16.6,42.87) v4(16.58,8.84) v4(16.58,3.19) v4(16.7,20.66) v4(16.69,1.03) v4(16.78,7.98) v4(16.92,20.1) v4(17.02,43.58) v4(16.98,23.61) v4(16.98,23.11) v4(16.98,22.61) v4(16.94,8.84) v4(17,1.03) v4(17.07,19.54) v4(17.13,18.92) v4(17.13,18.31) v4(17.13,17.71) v4(17.13,17.1) v4(17.13,16.49) v4(17.13,15.88) v4(17.13,15.27) v4(17.13,14.66) v4(17.13,14.05) v4(17.13,13.44) v4(17.13,12.83) v4(17.13,12.22) v4(17.13,10.62) v4(17.05,3.19) v4(17.15,11.64) v4(17.13,11.06) v4(17.13,10.1) v4(17.29,45.86) v4(17.29,42.4) v4(17.29,42) v4(17.4,3.27) v4(17.4,1.9) v4(17.4,1.55) v4(17.4,1.17) v4(17.44,43.73) v4(17.44,42.87) v4(17.52,41.55) v4(17.6,45.86) v4(17.53,3.8) v4(17.69,42.44) v4(17.71,4.01) v4(17.77,18.14) v4(17.77,17.53) v4(17.77,16.92) v4(17.77,16.31) v4(17.77,15.7) v4(17.77,14.96) v4(17.77,1.03) v4(17.9,45.86) v4(17.87,41.54) v4(17.91,22.65) v4(17.96,3.19) v4(18.07,42.44) v4(18.05,9.81) v4(18.13,1.03) v4(18.21,45.86) v4(18.23,41.54) v4(18.3,16.92) v4(18.27,16.23) v4(18.27,15.62) v4(18.39,42.44) v4(18.43,9.55) v4(18.41,3.19) v4(18.51,45.86) v4(18.49,1.03) v4(18.6,41.55) v4(18.55,9.94) v4(18.68,43.73) v4(18.82,45.86) v4(18.83,42) v4(18.81,1.04) v4(18.88,3.19) v4(18.93,9.68) v4(19.1,43.58) v4(19.19,3.18) v4(19.2,2.9) v4(19.2,2.61) v4(19.2,2.26) v4(19.2,1.9) v4(19.2,1.55) v4(19.2,1.17) v4(20.13,39.71) v4(20.13,39.15) v4(20.13,38.59) v4(20.13,38.03) v4(20.13,37.47) v4(20.13,36.91) v4(20.13,36.35) v4(20.13,35.79) v4(20.13,35.23) v4(20.12,10.77) v4(20.19,44.7) v4(20.18,44.09) v4(20.2,43.44) v4(20.18,41.75) v4(20.19,41) v4(20.2,40.29) v4(20.14,34.57) v4(20.13,33.99) v4(20.15,11.75) v4(20.25,28.69) v5(0.51,36.63) v5(0.51,35.49) v5(0.51,34.55) v5(0.51,33.87) v5(0.51,33.23) v5(0.51,32.53) v5(0.51,31.81) v5(0.76,28.13) v5(0.76,27.5) v5(0.75,26.89) v5(0.89,28.64) v5(0.92,21.73) v5(0.89,21.32) v5(0.95,41.96) v5(1.03,26.57) v5(1.03,26.06) v5(1.03,25.43) v5(1.03,24.67) v5(1.03,24.03) v5(1.03,23.4) v5(1,22.76) v5(1.15,32.16) v5(1.15,31.53) v5(1.36,27.84) v5(1.72,42.87) v5(1.67,39) v5(1.66,18.5) v5(1.66,18.19) v5(1.66,17.89) v5(1.83,39.72) v5(1.79,37.88) v5(1.79,17.42) v5(1.79,17.11) v5(1.79,16.81) v5(1.82,3.23) v5(1.8,2.94) v5(1.8,2.56) v5(1.8,2.21) v5(1.8,1.85) v5(1.8,1.5) v5(1.8,1.11) v5(1.92,26.57) v5(1.92,25.94) v5(1.92,25.3) v5(1.92,20.22) v5(1.92,19.71) v5(1.9,3.77) v5(1.85,3.51) v5(1.94,42.41) v5(1.96,18.5) v5(1.96,18.19) v5(1.96,17.89) v5(2.09,35.79) v5(2.13,30.67) v5(2.1,17.42) v5(2.1,17.11) v5(2.1,16.81) v5(2.14,43.22) v5(2.17,29.84) v5(2.14,4.03) v5(2.25,42.82) v5(2.3,42.4) v5(2.3,26.32) v5(2.27,18.5) v5(2.27,18.19) v5(2.27,17.89) v5(2.42,42.19) v5(2.42,41.69) v5(2.42,27.08) v5(2.42,25.81) v5(2.4,24.41) v5(2.4,23.5) v5(2.4,17.42) v5(2.4,17.11) v5(2.4,16.81) v5(2.52,43.22) v5(2.53,28.68) v5(2.49,3.61) v5(2.65,42.4) v5(2.67,40.7) v5(2.67,37.98) v5(2.68,19.21) v5(2.74,42.82) v5(2.81,22.13) v5(2.88,43.22) v5(2.88,34.74) v5(2.92,3.61) v5(3.03,42.41) v5(2.93,18.83) v5(2.93,18.32) v5(2.93,17.68) v5(2.99,14.02) v5(2.99,13.51) v5(2.99,13) v5(3.09,41.58) v5(3.07,39.78) v5(3.04,33.91) v5(3.06,27.08) v5(3.06,16.16) v5(3.06,15.27) v5(3.14,28.63) v5(3.19,22.13) v5(3.19,19.21) v5(3.22,1.03) v5(3.25,43.27) v5(3.25,42.87) v5(3.31,26.7) v5(3.41,13.48) v5(3.43,13.01) v5(3.42,12.53) v5(3.42,12.09) v5(3.44,22.64) v5(3.44,18.83) v5(3.53,16.34) v5(3.47,15.74) v5(3.44,15.13) v5(3.45,14.51) v5(3.43,14.02) v5(3.44,6.38) v5(3.62,38.22) v5(3.57,24.41) v5(3.57,23.78) v5(3.57,23.27) v5(3.62,21.9) v5(3.61,16.94) v5(3.57,10.62) v5(3.59,3.62) v5(3.59,3.33) v5(3.6,2.99) v5(3.6,2.61) v5(3.6,2.26) v5(3.6,1.9) v5(3.6,1.55) v5(3.59,1.17) v5(3.67,43.58) v5(3.71,17.55) v5(3.72,10.18) v5(3.73,3.83) v5(3.82,28.68) v5(3.82,24.92) v5(3.82,21.49) v5(3.83,18.15) v5(3.77,9.76) v5(3.83,40.01) v5(3.89,37.62) v5(3.92,10.62) v5(3.96,45.87) v5(3.94,42.4) v5(3.94,42) v5(3.94,39.38) v5(3.95,34.32) v5(4.02,19.25) v5(3.94,18.75) v5(3.93,4.05) v5(4.1,43.72) v5(4.09,42.87) v5(4.12,20.2) v5(4.09,19.74) v5(4.13,9.76) v5(4.08,5.87) v5(4.17,41.55) v5(4.2,21.7) v5(4.19,21.21) v5(4.16,20.71) v5(4.21,10.18) v5(4.27,45.87) v5(4.32,42.4) v5(4.33,33.96) v5(4.28,10.62) v5(4.29,3.61) v5(4.47,41.95) v5(4.52,41.54) v5(4.46,28.99) v5(4.48,23.11) v5(4.52,15.34) v5(4.52,15.03) v5(4.5,14.61) v5(4.49,14.09) v5(4.48,13.28) v5(4.49,12.63) v5(4.49,11.88) v5(4.57,45.87) v5(4.6,16.47) v5(4.55,15.91) v5(4.68,42.4) v5(4.69,34.4) v5(4.65,34.08) v5(4.65,16.94) v5(4.72,3.61) v5(4.74,17.44) v5(4.88,45.87) v5(4.88,41.54) v5(4.87,18.04) v5(5.03,42.4) v5(4.97,41.95) v5(4.96,39.16) v5(4.99,37.84) v5(4.98,33.11) v5(4.96,25.05) v5(4.96,24.54) v5(4.98,23.11) v5(4.97,18.64) v5(4.99,17.1) v5(4.95,16.53) v5(4.95,15.93) v5(4.94,15.34) v5(4.94,15.04) v5(4.95,14.68) v5(4.95,14.2) v5(4.96,13.73) v5(4.96,13.23) v5(4.95,12.66) v5(4.97,11.92) v5(4.96,11.51) v5(4.96,11.04) v5(4.96,10.61) v5(4.96,10.11) v5(5.01,1.03) v5(5.07,34.17) v5(5.07,19.2) v5(5.1,18.31) v5(5.04,17.71) v5(5.09,8.84) v5(5.09,7.4) v5(5.18,45.87) v5(5.14,40.95) v5(5.18,36.01) v5(5.22,20.79) v5(5.2,20.3) v5(5.15,19.78) v5(5.2,18.91) v5(5.33,43.72) v5(5.33,42.87) v5(5.25,41.55) v5(5.27,21.72) v5(5.25,21.27) v5(5.3,19.48) v5(5.24,8.4) v5(5.29,7.98) v5(5.42,34.17) v5(5.43,20) v5(5.4,3.31) v5(5.4,1.9) v5(5.4,1.55) v5(5.4,1.17) v5(5.49,45.87) v5(5.48,42.4) v5(5.48,42) v5(5.48,33.11) v5(5.52,20.5) v5(5.45,8.84) v5(5.6,20.97) v5(5.54,3.82) v5(5.7,21.87) v5(5.67,21.49) v5(5.65,7.98) v5(5.75,43.58) v5(5.76,36) v5(5.78,34.4) v5(5.8,8.84) v5(5.74,8.4) v5(5.74,4.07) v5(5.84,34.05) v5(5.98,23.11) v5(6.01,16.61) v5(6.01,16.01) v5(6.01,15.4) v5(6.01,14.79) v5(5.98,14.38) v5(6.01,13.57) v5(6.01,12.96) v5(6.01,12.35) v5(6.01,11.74) v5(6,11.05) v5(6.01,10.61) v5(6.01,10.14) v5(6.1,17.83) v5(6.05,17.22) v5(6.09,3.61) v5(6.17,43.27) v5(6.17,42.87) v5(6.16,39.02) v5(6.18,34.4) v5(6.14,34.07) v5(6.17,18.43) v5(6.32,43.74) v5(6.26,18.9) v5(6.39,42.41) v5(6.41,41.33) v5(6.4,36) v5(6.35,19.33) v5(6.48,33.11) v5(6.48,23.11) v5(6.46,19.84) v5(6.51,19.07) v5(6.49,18.67) v5(6.49,18.02) v5(6.49,17.42) v5(6.49,16.81) v5(6.49,16.2) v5(6.49,15.59) v5(6.49,14.98) v5(6.49,14.37) v5(6.46,13.64) v5(6.49,13.15) v5(6.49,12.54) v5(6.49,11.93) v5(6.52,3.61) v5(6.54,43.27) v5(6.54,34.17) v5(6.58,20.35) v5(6.59,19.55) v5(6.62,10.62) v5(6.72,42.81) v5(6.69,40.57) v5(6.68,20.89) v5(6.71,20.04) v5(6.75,42.4) v5(6.74,38.13) v5(6.74,37.62) v5(6.74,37.11) v5(6.75,21.85) v5(6.75,21.39) v5(6.77,10.18) v5(6.82,9.76) v5(6.82,1.03) v5(6.9,43.27) v5(6.9,34.17) v5(6.87,20.5) v5(6.98,33.11) v5(6.97,10.62) v5(7.1,42.4) v5(7.03,36) v5(7.05,21) v5(7.15,42.8) v5(7.17,21.59) v5(7.17,9.76) v5(7.2,3.56) v5(7.2,3.28) v5(7.2,2.97) v5(7.2,2.59) v5(7.2,2.23) v5(7.2,1.88) v5(7.2,1.52) v5(7.2,1.14) v5(7.26,43.27) v5(7.28,34.45) v5(7.3,34.07) v5(7.33,10.62) v5(7.26,10.18) v5(7.33,3.81) v5(7.48,42.41) v5(7.48,23.11) v5(7.53,18.63) v5(7.52,18.02) v5(7.52,17.41) v5(7.52,16.8) v5(7.52,16.19) v5(7.52,15.58) v5(7.52,14.97) v5(7.52,14.37) v5(7.52,13.76) v5(7.52,13.15) v5(7.52,12.54) v5(7.52,11.93) v5(7.55,43.74) v5(7.59,19.24) v5(7.57,5.25) v5(7.56,4.07) v5(7.7,43.27) v5(7.7,42.87) v5(7.67,36) v5(7.68,34.45) v5(7.65,34.08) v5(7.69,5.84) v5(7.74,19.84) v5(7.85,6.39) v5(7.89,3.61) v5(7.98,33.11) v5(7.98,23.11) v5(7.97,20.4) v5(8,18.91) v5(8.01,18.17) v5(8.01,17.57) v5(8.01,16.96) v5(8.01,16.35) v5(8.01,15.74) v5(8.01,15.13) v5(8.01,14.52) v5(8.01,13.91) v5(8.01,13.3) v5(8.01,12.69) v5(8.01,12.08) v5(7.97,11.66) v5(8.01,11.06) v5(8.01,10.6) v5(8,10.1) v5(7.97,7.45) v5(7.96,6.92) v5(8.12,43.58) v5(8.11,41.51) v5(8.04,34.17) v5(8.04,19.55) v5(8.17,40.62) v5(8.15,20.98) v5(8.16,20.06) v5(8.14,8.84) v5(8.27,38.13) v5(8.27,37.62) v5(8.27,37.11) v5(8.3,36) v5(8.24,21.59) v5(8.29,8.4) v5(8.32,3.61) v5(8.42,45.87) v5(8.39,42.4) v5(8.39,42) v5(8.39,34.17) v5(8.39,20.63) v5(8.34,7.98) v5(8.48,33.11) v5(8.5,8.84) v5(8.54,43.73) v5(8.54,42.87) v5(8.62,41.55) v5(8.6,21.13) v5(8.72,45.87) v5(8.69,21.73) v5(8.7,7.98) v5(8.64,1.03) v5(8.77,42.4) v5(8.77,34.42) v5(8.82,34.06) v5(8.79,8.4) v5(8.92,41.95) v5(8.85,8.84) v5(8.92,3.49) v5(9.03,45.87) v5(8.97,41.54) v5(8.94,36) v5(8.98,23.11) v5(9,6.35) v5(8.97,3.24) v5(9,1.9) v5(9,1.55) v5(9,1.17) v5(9.13,42.4) v5(9.09,19.38) v5(9.06,18.81) v5(9.05,18.18) v5(9.05,17.57) v5(9.05,16.96) v5(9.05,16.35) v5(9.05,15.74) v5(9.06,15.13) v5(9.05,14.56) v5(9.05,13.91) v5(9.05,13.3) v5(9.05,12.69) v5(9.05,12.08) v5(9.06,11.61) v5(9.06,11.09) v5(9.05,10.6) v5(9.05,10.1) v5(9.09,7.43) v5(9.07,6.89) v5(9.18,34.42) v5(9.14,34.08) v5(9.33,41.54) v5(9.24,19.98) v5(9.33,45.87) v5(9.42,41.95) v5(9.41,12.98) v5(9.43,3.1) v5(9.43,2.6) v5(9.41,2.01) v5(9.41,1.5) v5(9.41,0.99) v5(9.48,42.4) v5(9.48,33.11) v5(9.48,23.11) v5(9.51,20.53) v5(9.57,36) v5(9.54,34.17) v5(9.54,19.46) v5(9.54,18.7) v5(9.64,45.87) v5(9.7,41.55) v5(9.71,40.57) v5(9.66,38.13) v5(9.66,37.62) v5(9.66,37.11) v5(9.69,21.11) v5(9.66,13.36) v5(9.66,12.6) v5(9.78,43.73) v5(9.78,42.87) v5(9.76,21.72) v5(9.79,19.08) v5(9.79,16.03) v5(9.93,42.4) v5(9.93,42) v5(9.89,34.17) v5(9.92,20.48) v5(9.92,18.7) v5(9.92,18.06) v5(9.92,17.3) v5(9.92,16.67) v5(9.92,12.98) v5(9.94,45.87) v5(9.98,33.11) v5(10.2,43.58) v5(10.21,36) v5(10.17,21.62) v5(10.17,21.11) v5(10.27,34.4) v5(10.33,34.05) v5(10.3,13.36) v5(10.3,12.6) v5(10.43,19.33) v5(10.43,15.27) v5(10.62,43.27) v5(10.62,42.87) v5(10.55,17.94) v5(10.55,17.3) v5(10.55,16.54) v5(10.55,15.9) v5(10.55,12.98) v5(10.68,34.4) v5(10.63,34.07) v5(10.7,21.84) v5(10.73,21.46) v5(10.77,43.74) v5(10.83,21.06) v5(10.81,13.36) v5(10.81,12.6) v5(10.84,42.41) v5(10.85,35.98) v5(10.88,18.25) v5(11,43.27) v5(10.98,33.11) v5(10.98,23.11) v5(11,20.66) v5(10.93,19.08) v5(10.93,15.27) v5(11.04,34.17) v5(11.06,12.98) v5(11.15,42.81) v5(11.2,42.4) v5(11.19,38.13) v5(11.19,37.62) v5(11.19,37.11) v5(11.19,12.6) v5(11.24,40.64) v5(11.3,20.18) v5(11.35,43.27) v5(11.39,34.17) v5(11.48,35.98) v5(11.48,33.11) v5(11.48,23.11) v5(11.49,19.7) v5(11.52,19.11) v5(11.52,18.5) v5(11.52,17.89) v5(11.52,17.28) v5(11.52,16.67) v5(11.52,16.06) v5(11.52,15.45) v5(11.52,14.84) v5(11.52,14.23) v5(11.52,13.62) v5(11.52,13.01) v5(11.52,12.46) v5(11.51,11.93) v5(11.44,3.03) v5(11.44,2.52) v5(11.44,2.01) v5(11.44,1.5) v5(11.44,0.99) v5(11.55,42.4) v5(11.71,43.27) v5(11.64,42.81) v5(11.67,10.62) v5(11.8,34.45) v5(11.82,34.06) v5(11.75,21.85) v5(11.8,10.18) v5(11.93,42.41) v5(11.85,21.4) v5(11.87,9.76) v5(12,43.74) v5(12.03,10.62) v5(12.03,3.23) v5(12,1.95) v5(12,1.6) v5(12,1.22) v5(12.12,35.98) v5(12.08,6.25) v5(12.06,3.51) v5(12.15,43.27) v5(12.15,42.87) v5(12.15,34.45) v5(12.15,34.08) v5(12.22,21.6) v5(12.15,20.82) v5(12.23,9.76) v5(12.13,3.83) v5(12.31,21.13) v5(12.3,10.18) v5(12.43,20.29) v5(12.38,10.62) v5(12.36,4.06) v5(12.48,33.11) v5(12.48,23.11) v5(12.49,20.66) v5(12.57,43.58) v5(12.56,34.19) v5(12.53,19.7) v5(12.56,19.11) v5(12.56,18.5) v5(12.56,17.89) v5(12.56,17.28) v5(12.56,16.67) v5(12.56,16.06) v5(12.56,15.45) v5(12.56,14.84) v5(12.56,14.23) v5(12.56,13.62) v5(12.56,13.01) v5(12.56,12.46) v5(12.57,11.93) v5(12.71,38.13) v5(12.71,37.62) v5(12.71,37.11) v5(12.69,3.61) v5(12.75,35.98) v5(12.78,20.09) v5(12.86,45.87) v5(12.84,42.4) v5(12.84,42) v5(12.89,40.69) v5(12.91,34.19) v5(12.99,43.73) v5(12.99,42.87) v5(12.98,33.11) v5(12.98,23.11) v5(12.99,19.49) v5(13.03,18.74) v5(13.07,41.55) v5(13.05,18.09) v5(13.05,17.48) v5(13.05,16.87) v5(13.05,16.26) v5(13.05,15.71) v5(13.05,15.04) v5(13.05,14.43) v5(13.05,13.82) v5(13.05,13.21) v5(13.05,12.6) v5(13.05,12.12) v5(13.04,11.64) v5(13.04,11.05) v5(13.04,10.58) v5(13.04,10.14) v5(13.12,3.61) v5(13.16,45.87) v5(13.22,42.4) v5(13.18,8.84) v5(13.27,34.42) v5(13.31,34.06) v5(13.27,21.59) v5(13.33,8.4) v5(13.37,41.95) v5(13.42,41.54) v5(13.39,35.98) v5(13.38,7.98) v5(13.42,1.03) v5(13.47,45.87) v5(13.48,23.11) v5(13.52,21) v5(13.53,8.84) v5(13.58,42.4) v5(13.63,34.08) v5(13.68,34.42) v5(13.71,21.84) v5(13.64,7.25) v5(13.77,45.87) v5(13.78,41.54) v5(13.76,21.34) v5(13.76,20.49) v5(13.82,8.4) v5(13.73,7.98) v5(13.8,3.56) v5(13.81,3.27) v5(13.8,2.97) v5(13.8,2.61) v5(13.8,2.26) v5(13.8,1.9) v5(13.8,1.55) v5(13.8,1.17) v5(13.93,42.4) v5(13.87,41.95) v5(13.89,8.84) v5(14.02,35.98) v5(13.98,33.11) v5(13.98,23.11) v5(13.94,20.84) v5(13.97,19.91) v5(13.94,3.85) v5(14.08,45.87) v5(14.06,34.19) v5(14.07,19.31) v5(14.09,18.7) v5(14.08,18.09) v5(14.08,17.48) v5(14.08,16.87) v5(14.08,16.26) v5(14.08,15.65) v5(14.08,15.06) v5(14.08,14.43) v5(14.08,13.83) v5(14.08,13.22) v5(14.08,12.61) v5(14.09,12.12) v5(14.08,11.64) v5(14.08,11.25) v5(14.08,10.77) v5(14.08,10.33) v5(14.11,6.14) v5(14.23,43.73) v5(14.23,42.87) v5(14.15,41.55) v5(14.16,4.07) v5(14.24,38.13) v5(14.24,37.62) v5(14.24,37.11) v5(14.25,20.35) v5(14.38,45.87) v5(14.38,42.4) v5(14.38,42) v5(14.41,34.19) v5(14.51,41.65) v5(14.48,33.11) v5(14.48,23.11) v5(14.48,19.71) v5(14.49,3.61) v5(14.55,18.96) v5(14.57,18.32) v5(14.57,17.71) v5(14.57,17.1) v5(14.57,16.49) v5(14.55,15.88) v5(14.55,15.27) v5(14.57,14.66) v5(14.57,14.05) v5(14.57,13.44) v5(14.57,12.83) v5(14.57,12.28) v5(14.57,11.73) v5(14.65,43.58) v5(14.66,35.98) v5(14.74,40.8) v5(14.79,34.42) v5(14.75,21.75) v5(14.74,10.37) v5(14.84,34.05) v5(14.93,21.22) v5(14.85,9.92) v5(14.9,9.48) v5(14.92,3.61) v5(15.07,43.27) v5(15.07,42.87) v5(15.1,10.37) v5(15.12,7.01) v5(15.22,43.74) v5(15.15,34.42) v5(15.16,34.08) v5(15.2,21.57) v5(15.21,1.02) v5(15.29,42.41) v5(15.29,35.98) v5(15.32,21.08) v5(15.24,20.7) v5(15.25,9.48) v5(15.35,9.92) v5(15.45,43.27) v5(15.48,33.11) v5(15.48,23.11) v5(15.46,20.13) v5(15.45,10.37) v5(15.61,42.82) v5(15.53,38.62) v5(15.56,34.22) v5(15.57,20.52) v5(15.59,19.54) v5(15.61,18.93) v5(15.61,18.32) v5(15.61,17.71) v5(15.61,17.1) v5(15.61,16.49) v5(15.62,15.86) v5(15.62,15.25) v5(15.62,14.64) v5(15.62,14.03) v5(15.61,13.44) v5(15.62,12.83) v5(15.61,12.28) v5(15.61,11.75) v5(15.59,6.39) v5(15.61,3.26) v5(15.6,2.97) v5(15.6,2.61) v5(15.6,2.26) v5(15.6,1.9) v5(15.6,1.55) v5(15.6,1.17) v5(15.69,42.42) v5(15.72,3.78) v5(15.8,43.27) v5(15.81,7.5) v5(15.91,34.19) v5(15.86,19.98) v5(15.92,14.23) v5(15.89,13.78) v5(16.02,42.41) v5(15.98,33.11) v5(15.98,23.11) v5(16.01,19.47) v5(16.01,7.04) v5(15.96,4.06) v5(16.07,42.8) v5(16.09,18.93) v5(16.09,18.32) v5(16.09,17.71) v5(16.09,17.1) v5(16.09,16.49) v5(16.08,15.85) v5(16.08,15.24) v5(16.08,14.63) v5(16.09,14) v5(16.08,13.43) v5(16.08,12.81) v5(16.09,12.22) v5(16.08,11.64) v5(16.1,11.27) v5(16.1,10.81) v5(16.09,10.32) v5(16.16,43.27) v5(16.22,8.84) v5(16.32,21.64) v5(16.28,6.62) v5(16.29,3.61) v5(16.38,42.41) v5(16.42,36.72) v5(16.33,34.04) v5(16.37,8.4) v5(16.43,7.98) v5(16.45,43.74) v5(16.43,21.15) v5(16.6,43.27) v5(16.6,42.87) v5(16.58,8.84) v5(16.7,20.66) v5(16.72,3.61) v5(16.78,41.97) v5(16.79,41.08) v5(16.78,7.98) v5(16.9,31.53) v5(16.92,20.1) v5(16.87,8.4) v5(17.02,43.58) v5(16.99,38.3) v5(16.97,37.45) v5(16.98,23.61) v5(16.98,23.11) v5(16.98,22.61) v5(16.94,8.84) v5(17.03,6.63) v5(17.03,5.87) v5(17,1.03) v5(17.07,19.54) v5(17.13,18.92) v5(17.13,18.31) v5(17.13,17.71) v5(17.13,17.1) v5(17.13,16.49) v5(17.13,15.88) v5(17.13,15.27) v5(17.13,14.66) v5(17.13,14.05) v5(17.13,13.44) v5(17.13,12.83) v5(17.13,12.22) v5(17.13,10.62) v5(17.15,11.64) v5(17.13,11.06) v5(17.13,10.1) v5(17.29,45.86) v5(17.29,42.4) v5(17.29,42) v5(17.4,3.27) v5(17.4,1.9) v5(17.4,1.55) v5(17.4,1.17) v5(17.44,43.73) v5(17.44,42.87) v5(17.52,41.55) v5(17.48,39.86) v5(17.6,45.86) v5(17.53,3.8) v5(17.69,42.44) v5(17.71,4.01) v5(17.82,41.95) v5(17.77,18.14) v5(17.77,17.53) v5(17.77,16.92) v5(17.77,16.31) v5(17.77,15.7) v5(17.77,14.96) v5(17.82,6.82) v5(17.9,45.86) v5(17.87,41.54) v5(17.91,22.65) v5(17.84,7.88) v5(18.07,42.44) v5(18.09,3.61) v5(18.21,45.86) v5(18.23,41.54) v5(18.18,34.78) v5(18.32,41.95) v5(18.3,16.92) v5(18.27,16.23) v5(18.27,15.62) v5(18.39,42.44) v5(18.51,45.86) v5(18.52,3.61) v5(18.6,41.55) v5(18.57,40.07) v5(18.55,32.67) v5(18.55,32.03) v5(18.55,31.53) v5(18.68,43.73) v5(18.82,45.86) v5(18.83,42) v5(18.81,1.04) v5(19.1,43.58) v5(19.19,32.67) v5(19.19,32.03) v5(19.19,3.18) v5(19.2,2.9) v5(19.2,2.61) v5(19.2,2.26) v5(19.2,1.9) v5(19.2,1.55) v5(19.2,1.17) v5(19.32,34.07) v5(19.6,37.5) v5(19.7,31.4) v5(19.84,34.64) v5(20.13,39.71) v5(20.13,39.15) v5(20.13,38.59) v5(20.13,38.03) v5(20.13,37.47) v5(20.13,36.91) v5(20.13,36.35) v5(20.13,35.79) v5(20.13,35.23) v5(20.19,44.7) v5(20.18,44.09) v5(20.2,43.44) v5(20.18,41.75) v5(20.19,41) v5(20.2,40.29) v5(20.14,34.57) v5(20.13,33.99) v5(20.25,23.53) v5(20.24,23.06) v5(20.24,22.55) v5(20.24,22.04) v5(20.24,21.53) v5(20.24,21.03) v5(20.24,20.39) v5(20.24,19.88) v5(20.24,19.37) v5(20.24,18.86) v5(20.24,18.36) v6(0.78,25.57) v6(0.77,18.35) v6(0.77,17.97) v6(0.77,17.59) v6(0.77,17.21) v6(0.92,23.87) v6(1,27.03) v6(1.2,35.85) v6(1.22,20.98) v6(1.15,18.35) v6(1.15,17.97) v6(1.15,17.59) v6(1.15,17.21) v6(1.39,29.76) v6(1.41,23.55) v6(1.41,23.12) v6(1.44,32.7) v6(1.5,31.96) v6(1.44,31.16) v6(1.53,18.35) v6(1.53,17.97) v6(1.53,17.59) v6(1.53,17.21) v6(1.52,3.54) v6(1.48,3.26) v6(1.47,2.97) v6(1.47,2.59) v6(1.47,2.23) v6(1.47,1.88) v6(1.47,1.52) v6(1.47,1.17) v6(1.58,30.48) v6(1.64,27.64) v6(1.66,27.23) v6(1.66,11.36) v6(1.66,10.06) v6(1.77,29.03) v6(1.76,23.55) v6(1.76,23.14) v6(1.91,18.35) v6(1.91,17.97) v6(1.91,17.59) v6(1.91,17.21) v6(1.97,33.43) v6(1.95,27.96) v6(2.05,28.53) v6(2.14,36.76) v6(2.17,10.44) v6(2.17,10.06) v6(2.28,42.73) v6(2.29,18.35) v6(2.29,17.97) v6(2.29,17.59) v6(2.63,10.8) v6(2.63,10.44) v6(2.63,10.06) v6(2.72,33.69) v6(2.91,41.04) v6(2.87,7.11) v6(2.93,4.11) v6(2.97,23.83) v6(3,5.07) v6(2.96,4.58) v6(3.11,9.96) v6(3.16,23.14) v6(3.19,7.56) v6(3.14,5.55) v6(3.16,3.84) v6(3.32,31.38) v6(3.33,30.64) v6(3.31,3.57) v6(3.31,3.28) v6(3.31,3) v6(3.31,2.67) v6(3.31,2.32) v6(3.31,1.93) v6(3.31,1.58) v6(3.31,1.22) v6(3.4,9.31) v6(3.4,8.75) v6(3.4,8.14) v6(3.51,33.54) v6(3.44,12.98) v6(3.58,6.22) v6(3.68,5.22) v6(3.77,11.7) v6(3.82,5.71) v6(3.99,31.57) v6(3.98,31.18) v6(3.98,23.11) v6(3.93,6.63) v6(4.09,45.04) v6(4.06,26.12) v6(4.07,24.11) v6(4.13,11.7) v6(4.05,6.18) v6(4.22,7.12) v6(4.29,14.44) v6(4.29,14.06) v6(4.29,13.68) v6(4.27,12.85) v6(4.35,30.4) v6(4.36,29.86) v6(4.37,29.4) v6(4.36,23.3) v6(4.42,15.94) v6(4.42,15.56) v6(4.42,15.18) v6(4.37,6.61) v6(4.48,24.11) v6(4.5,9.27) v6(4.5,8.82) v6(4.51,8.18) v6(4.43,7.62) v6(4.57,26.13) v6(4.66,31.56) v6(4.71,30.49) v6(4.68,14.44) v6(4.68,14.06) v6(4.68,6.99) v6(4.73,4.09) v6(4.74,23.3) v6(4.8,15.94) v6(4.8,15.18) v6(4.79,5.14) v6(4.74,4.63) v6(4.9,7.47) v6(4.99,32.54) v6(4.98,24.11) v6(4.96,11.51) v6(5.01,5.61) v6(4.94,3.87) v6(5.1,3.6) v6(5.1,3.31) v6(5.1,1.88) v6(5.1,1.52) v6(5.19,15.94) v6(5.19,15.56) v6(5.19,15.18) v6(5.32,14.44) v6(5.32,14.06) v6(5.32,13.68) v6(5.27,12.87) v6(5.32,11.71) v6(5.29,5.96) v6(5.47,32.54) v6(5.48,24.11) v6(5.48,23.11) v6(5.49,5.18) v6(5.61,45.12) v6(5.58,30.48) v6(5.57,15.94) v6(5.57,15.56) v6(5.57,15.18) v6(5.63,6.4) v6(5.57,5.6) v6(5.7,14.44) v6(5.7,14.06) v6(5.7,13.68) v6(5.68,11.71) v6(5.78,23.27) v6(6,11.49) v6(5.98,7.25) v6(6.14,42.87) v6(6.36,37.38) v6(6.39,13.03) v6(6.39,8.12) v6(6.49,32.54) v6(6.45,12.73) v6(6.46,9.26) v6(6.45,8.83) v6(6.59,5.09) v6(6.54,4.58) v6(6.54,4.07) v6(6.65,23.77) v6(6.72,5.66) v6(6.81,37.63) v6(6.74,11.69) v6(6.75,3.84) v6(6.9,3.57) v6(6.9,3.28) v6(6.9,2.99) v6(6.9,2.61) v6(6.9,2.26) v6(6.9,1.9) v6(6.9,1.55) v6(6.9,1.19) v6(7,32.54) v6(6.96,6.27) v6(7.18,6.82) v6(7.3,37.63) v6(7.25,11.69) v6(7.27,5.22) v6(7.24,4.64) v6(7.35,7.35) v6(7.48,24.11) v6(7.48,23.73) v6(7.51,18.47) v6(7.51,18.11) v6(7.51,17.74) v6(7.53,8.18) v6(7.45,5.84) v6(7.57,17.09) v6(7.57,16.73) v6(7.54,13.37) v6(7.54,12.94) v6(7.54,9.26) v6(7.54,8.81) v6(7.75,6.4) v6(7.89,18.47) v6(7.89,18.11) v6(7.89,17.74) v6(7.93,13.39) v6(7.93,12.96) v6(8.01,32.54) v6(7.96,23.75) v6(7.95,17.09) v6(7.95,16.73) v6(7.96,11.69) v6(7.99,7.42) v6(7.94,6.88) v6(8.27,18.47) v6(8.27,18.11) v6(8.27,17.74) v6(8.33,4.09) v6(8.33,17.09) v6(8.33,16.73) v6(8.37,11.71) v6(8.36,5.03) v6(8.33,4.57) v6(8.52,32.54) v6(8.48,24.11) v6(8.55,5.55) v6(8.6,3.75) v6(8.72,11.71) v6(8.67,3.46) v6(8.7,1.9) v6(8.7,1.55) v6(8.7,1.19) v6(8.89,43.79) v6(8.9,23.73) v6(8.91,6.22) v6(8.98,24.11) v6(8.99,3.51) v6(9.13,11.71) v6(9.08,7.4) v6(9.07,6.76) v6(9.14,19.28) v6(9.14,18.93) v6(9.32,6.42) v6(9.37,37.6) v6(9.35,37.13) v6(9.34,34.76) v6(9.35,34.31) v6(9.39,12.73) v6(9.34,7.69) v6(9.36,7.07) v6(9.52,19.28) v6(9.52,18.93) v6(9.54,32.54) v6(9.82,37.59) v6(9.79,20.25) v6(9.87,43.58) v6(9.92,34.83) v6(9.92,32.54) v6(9.9,19.28) v6(9.9,18.93) v6(10.18,15.38) v6(10.54,15.71) v6(10.54,15.38) v6(10.8,19.27) v6(10.8,18.91) v6(10.94,15.69) v6(10.94,15.37) v6(11.06,34.95) v6(11.06,32.54) v6(11.18,19.27) v6(11.18,18.91) v6(11.31,40.67) v6(11.31,40.39) v6(11.44,35.46) v6(11.45,34.93) v6(11.44,32.54) v6(11.56,19.27) v6(11.56,18.91) v6(11.6,7.11) v6(11.68,40.62) v6(11.68,40.3) v6(11.7,1.9) v6(11.67,1.55) v6(11.67,1.17) v6(11.76,6.53) v6(11.78,3.5) v6(11.85,11.71) v6(11.84,3.85) v6(11.98,24.11) v6(11.98,23.61) v6(11.94,19.27) v6(11.94,18.91) v6(11.98,12.59) v6(12.11,40.15) v6(12.04,4.14) v6(12.2,11.71) v6(12.35,37.74) v6(12.37,37.19) v6(12.36,18.83) v6(12.37,18.41) v6(12.43,40.9) v6(12.46,32.54) v6(12.44,27.11) v6(12.48,24.11) v6(12.58,9.26) v6(12.59,8.82) v6(12.59,8.32) v6(12.74,23.83) v6(12.81,22.79) v6(12.8,21.59) v6(12.86,22.43) v6(12.86,22.05) v6(12.97,32.54) v6(12.98,24.11) v6(12.93,23.54) v6(13.04,11.67) v6(13.09,5.83) v6(13.14,5.26) v6(13.15,4.68) v6(13.14,4.13) v6(13.42,11.71) v6(13.35,3.85) v6(13.47,35.47) v6(13.5,33.38) v6(13.5,32.97) v6(13.51,3.59) v6(13.5,3.3) v6(13.5,2.99) v6(13.5,2.64) v6(13.5,2.28) v6(13.5,1.9) v6(13.47,1.55) v6(13.47,1.17) v6(13.77,11.72) v6(13.79,5.24) v6(14.01,33.76) v6(14.01,32.59) v6(14.11,35.46) v6(14.1,11.65) v6(14.18,7.56) v6(14.39,33.76) v6(14.36,16.97) v6(14.34,7.03) v6(14.49,35.46) v6(14.44,32.59) v6(14.53,6.55) v6(14.56,9.26) v6(14.55,8.8) v6(14.55,8.24) v6(14.7,42.85) v6(14.72,6.02) v6(14.77,33.76) v6(14.76,7.22) v6(14.87,35.46) v6(14.9,16.92) v6(14.9,16.44) v6(14.9,11.46) v6(14.85,5.58) v6(14.91,5.11) v6(15.01,39.75) v6(15.01,39.05) v6(14.98,6.71) v6(14.94,4.61) v6(14.95,4.07) v6(15.06,30.53) v6(15.15,33.76) v6(15.16,3.84) v6(15.25,35.46) v6(15.33,11.46) v6(15.3,6.13) v6(15.31,3.55) v6(15.31,3.26) v6(15.3,2.97) v6(15.3,2.61) v6(15.3,2.26) v6(15.3,1.88) v6(15.27,1.52) v6(15.27,1.14) v6(15.51,30.61) v6(15.48,23.37) v6(15.48,16.92) v6(15.48,16.44) v6(15.52,5.62) v6(15.58,33.74) v6(15.56,33.23) v6(15.58,32.59) v6(15.63,9.26) v6(15.63,8.8) v6(15.63,35.46) v6(15.66,23.15) v6(15.64,8.29) v6(15.65,5.06) v6(15.75,7.72) v6(15.84,23.37) v6(15.99,7.15) v6(16.05,35.35) v6(16.1,23.13) v6(16.04,11.71) v6(16.2,23.42) v6(16.19,7.45) v6(16.29,6.64) v6(16.35,35.15) v6(16.37,11.71) v6(16.51,23.88) v6(16.5,23.52) v6(16.45,7.02) v6(16.58,34.9) v6(16.62,31.55) v6(16.55,6.13) v6(16.71,24.25) v6(16.7,5.58) v6(16.78,34.57) v6(16.83,34.21) v6(16.83,33.83) v6(16.83,33.44) v6(16.78,11.71) v6(16.79,6.65) v6(16.75,5.01) v6(16.75,4.53) v6(16.74,4.07) v6(17,33.13) v6(17,31.55) v6(16.94,3.86) v6(17.13,39.57) v6(17.04,6.26) v6(17.09,3.56) v6(17.09,3.27) v6(17.1,1.88) v6(17.07,1.52) v6(17.07,1.14) v6(17.18,11.71) v6(17.28,33.56) v6(17.26,5.82) v6(17.41,32.8) v6(17.41,32.41) v6(17.41,32.03) v6(17.41,31.65) v6(17.47,7.55) v6(17.54,33.18) v6(17.82,7.13) v6(17.92,32.92) v6(17.86,32.53) v6(17.92,31.59) v6(17.87,10.9) v6(17.84,10.49) v6(17.84,10.06) v6(18.15,32.01) v6(18.14,6.62) v6(18.41,31.59) v6(18.4,5.9) v6(18.51,5.36) v6(18.53,31.92) v6(18.54,4.63) v6(18.57,4.07) v6(18.71,18.69) v6(18.71,18.36) v6(18.83,43.45) v6(18.8,3.78) v6(18.85,39.12) v6(18.87,17.35) v6(18.84,3.49) v6(18.89,3.21) v6(18.89,2.93) v6(18.88,2.62) v6(18.91,2.26) v6(18.91,1.91) v6(18.9,1.55) v6(18.9,1.17) v6(18.93,32.01) v6(19.01,31.59) v6(18.94,16.92) v6(18.94,16.54) v6(18.96,16.18) v6(18.96,15.77) v6(19.06,18.69) v6(19.06,18.36) v6(19.21,33.19) v6(19.23,34.35) v6(19.26,31.98) v6(19.29,16.92) v6(19.29,16.54) v6(19.31,16.18) v6(19.31,15.77) v6(19.37,27.04) v6(19.37,26.5) v6(19.37,26) v6(19.37,25.51) v6(19.4,18.7) v6(19.4,18.37) v6(19.53,24.95) v6(19.52,24.29) v6(19.52,23.75) v6(19.52,23.24) v6(19.52,22.76) v6(19.52,22.23) v6(19.52,21.75) v6(19.57,38) v6(19.6,36.36) v6(19.57,35.72) v6(19.54,21.24) v6(19.64,16.93) v6(19.64,16.54) v6(19.65,16.19) v6(19.65,15.78) v6(20.02,43.11) v6(19.99,27.05) v6(19.99,26.51) v6(19.99,26.01) v6(19.99,25.52) v6(20.02,24.99) v6(19.99,24.51) v6(20.02,24) v6(20.02,23.47) v6(20.02,22.99) v6(20.02,21.97) v6(20.13,41.19) v6(20.04,22.46) v6(20.04,21.47) v6(20.16,41.69) v6(20.13,40.44) v7(0.68,11.74) v7(0.67,10.82) v7(1.46,38.47) v7(1.52,3.54) v7(1.48,3.26) v7(1.47,2.97) v7(1.47,2.59) v7(1.47,2.23) v7(1.47,1.88) v7(1.47,1.52) v7(1.47,1.17) v7(1.68,12.19) v7(1.66,10.06) v7(1.79,41.89) v7(1.76,23.55) v7(1.76,23.14) v7(1.92,14.92) v7(1.87,3.18) v7(1.83,1.03) v7(1.99,45.94) v7(2.09,9.67) v7(2.14,12.74) v7(2.17,1.03) v7(2.3,45.51) v7(2.33,44.72) v7(2.32,3.18) v7(2.47,9.29) v7(2.53,1.03) v7(2.65,45.18) v7(2.69,12) v7(2.78,3.18) v7(2.89,8.86) v7(2.89,1.03) v7(3.01,44.8) v7(3.11,9.96) v7(3.22,46.15) v7(3.19,18.7) v7(3.19,17.68) v7(3.19,17.05) v7(3.21,7.83) v7(3.16,3.84) v7(3.31,3.57) v7(3.31,3.28) v7(3.31,3) v7(3.31,2.67) v7(3.31,2.32) v7(3.31,1.93) v7(3.31,1.58) v7(3.31,1.22) v7(3.41,44.42) v7(3.37,22.02) v7(3.41,14.71) v7(3.42,14.11) v7(3.41,13.52) v7(3.42,12.98) v7(3.41,12.43) v7(3.42,11.91) v7(3.52,16.33) v7(3.47,15.81) v7(3.44,15.27) v7(3.54,45.83) v7(3.58,16.86) v7(3.59,10.6) v7(3.64,17.36) v7(3.67,3.18) v7(3.64,1.05) v7(3.83,44.01) v7(3.82,26.7) v7(3.74,21.04) v7(3.75,17.89) v7(3.77,9.76) v7(3.89,45.47) v7(3.92,18.87) v7(3.86,18.37) v7(3.92,10.6) v7(3.98,23.61) v7(3.98,23.11) v7(3.98,22.61) v7(4.03,19.43) v7(3.97,1.03) v7(4.07,24.11) v7(4.13,20.37) v7(4.1,19.89) v7(4.12,3.18) v7(4.21,46.02) v7(4.21,22.89) v7(4.21,22.42) v7(4.15,22.08) v7(4.18,21.52) v7(4.15,20.93) v7(4.15,9.76) v7(4.17,5.79) v7(4.17,5) v7(4.28,45.08) v7(4.26,43.57) v7(4.33,27.59) v7(4.33,26.7) v7(4.28,10.6) v7(4.33,1.03) v7(4.36,45.58) v7(4.48,28.11) v7(4.48,24.61) v7(4.48,24.11) v7(4.51,15.12) v7(4.49,14.56) v7(4.5,13.99) v7(4.48,13.41) v7(4.48,13) v7(4.48,12.6) v7(4.48,11.96) v7(4.6,45.15) v7(4.58,39.27) v7(4.58,38.64) v7(4.58,38) v7(4.58,37.37) v7(4.58,36.73) v7(4.59,16.23) v7(4.53,15.63) v7(4.58,3.18) v7(4.71,44.79) v7(4.63,43.2) v7(4.72,34.29) v7(4.66,33.84) v7(4.68,33.35) v7(4.71,27.21) v7(4.73,17.3) v7(4.64,16.78) v7(4.69,1.03) v7(4.77,34.73) v7(4.87,35.2) v7(4.85,17.88) v7(4.93,15.02) v7(4.93,13.94) v7(4.98,35.69) v7(4.96,26.7) v7(4.98,24.11) v7(5.02,17.55) v7(4.99,17.03) v7(4.96,16.52) v7(4.95,16) v7(4.94,14.46) v7(4.94,13.45) v7(4.96,13.05) v7(4.96,12.63) v7(4.96,11.92) v7(4.96,11.51) v7(4.96,11.04) v7(4.95,10.63) v7(4.96,10.11) v7(4.94,3.87) v7(5.13,44.38) v7(5.05,42.77) v7(5.09,40.67) v7(5.09,40.03) v7(5.09,38.64) v7(5.09,38) v7(5.09,37.37) v7(5.13,36.19) v7(5.12,18.72) v7(5.04,18.29) v7(5.08,8.89) v7(5.1,3.6) v7(5.1,3.31) v7(5.1,1.88) v7(5.1,1.52) v7(5.21,20.25) v7(5.2,19.22) v7(5.16,5.34) v7(5.29,36.68) v7(5.25,22.87) v7(5.24,22.33) v7(5.26,21.84) v7(5.26,21.35) v7(5.27,20.87) v7(5.24,19.67) v7(5.29,7.98) v7(5.35,46.04) v7(5.35,27.59) v7(5.51,43.97) v7(5.44,42.33) v7(5.43,37.17) v7(5.48,24.11) v7(5.48,23.61) v7(5.48,23.11) v7(5.48,22.61) v7(5.47,22.05) v7(5.51,20.47) v7(5.45,20.07) v7(5.44,8.89) v7(5.47,3.18) v7(5.43,1.03) v7(5.61,45.59) v7(5.58,41.79) v7(5.6,41.26) v7(5.61,40.7) v7(5.6,40.07) v7(5.6,39.45) v7(5.6,38.85) v7(5.59,38.26) v7(5.56,37.71) v7(5.62,20.86) v7(5.69,22.87) v7(5.7,22.33) v7(5.7,21.88) v7(5.65,21.39) v7(5.68,7.98) v7(5.82,34.42) v7(5.77,33.89) v7(5.77,33.36) v7(5.8,8.89) v7(5.77,1.03) v7(5.91,43.58) v7(5.91,34.94) v7(5.92,3.18) v7(5.94,45.24) v7(5.98,33.61) v7(5.98,33.11) v7(5.98,24.11) v7(6.02,16.35) v7(6.01,15.85) v7(6.01,15.31) v7(6.02,14.86) v7(6.01,14.41) v7(6.03,12.97) v7(6.02,12.48) v7(6,11.94) v7(6,11.49) v7(6,11.04) v7(6.01,10.63) v7(6.01,10.12) v7(6.04,35.46) v7(6.08,17.39) v7(6.04,16.88) v7(6.05,13.54) v7(6.13,1.03) v7(6.2,35.94) v7(6.2,33.89) v7(6.18,33.37) v7(6.16,17.91) v7(6.31,43.14) v7(6.31,34.42) v7(6.26,18.5) v7(6.34,46.09) v7(6.34,44.83) v7(6.39,36.49) v7(6.42,35) v7(6.41,19.28) v7(6.38,3.18) v7(6.5,45.54) v7(6.48,24.11) v7(6.44,18.83) v7(6.46,18.16) v7(6.45,17.6) v7(6.46,17.07) v7(6.46,16.51) v7(6.46,15.95) v7(6.46,15.39) v7(6.47,14.89) v7(6.44,14.43) v7(6.46,13.69) v7(6.48,13.2) v7(6.47,12.67) v7(6.48,12.08) v7(6.49,1.03) v7(6.58,42.63) v7(6.59,36.94) v7(6.55,35.59) v7(6.59,19.74) v7(6.62,10.6) v7(6.66,44.5) v7(6.72,42.11) v7(6.72,41.51) v7(6.72,40.92) v7(6.72,40.36) v7(6.72,39.75) v7(6.72,39.12) v7(6.73,38.54) v7(6.73,37.95) v7(6.68,37.44) v7(6.64,36.13) v7(6.69,20.83) v7(6.73,20.29) v7(6.79,45.08) v7(6.73,36.63) v7(6.75,22.87) v7(6.74,22.36) v7(6.75,21.81) v7(6.74,21.37) v7(6.82,9.76) v7(6.75,3.84) v7(6.9,3.57) v7(6.9,3.28) v7(6.9,2.99) v7(6.9,2.61) v7(6.9,2.26) v7(6.9,1.9) v7(6.9,1.55) v7(6.9,1.19) v7(7.01,44.11) v7(6.98,24.11) v7(6.98,23.61) v7(6.98,23.11) v7(6.98,22.61) v7(6.97,22.08) v7(6.97,10.6) v7(7.1,44.7) v7(7.05,21.06) v7(7.2,22.87) v7(7.21,22.34) v7(7.17,21.64) v7(7.2,9.76) v7(7.23,1.03) v7(7.3,43.74) v7(7.31,33.91) v7(7.27,33.34) v7(7.33,10.6) v7(7.27,3.18) v7(7.43,44.24) v7(7.4,34.37) v7(7.33,5.53) v7(7.46,46.14) v7(7.51,34.91) v7(7.48,33.61) v7(7.48,33.11) v7(7.48,24.11) v7(7.53,12.47) v7(7.53,12.06) v7(7.57,43.26) v7(7.62,19.3) v7(7.55,18.81) v7(7.54,18.26) v7(7.54,17.71) v7(7.54,17.15) v7(7.54,16.59) v7(7.54,16.03) v7(7.54,15.47) v7(7.54,14.89) v7(7.54,14.37) v7(7.53,13.86) v7(7.54,13.37) v7(7.54,12.94) v7(7.6,6.13) v7(7.57,1.03) v7(7.72,45.69) v7(7.64,35.46) v7(7.7,34.01) v7(7.69,33.35) v7(7.72,3.18) v7(7.75,43.75) v7(7.8,36.21) v7(7.83,35.77) v7(7.78,35.15) v7(7.75,34.59) v7(7.75,19.8) v7(7.9,43.26) v7(7.84,42.72) v7(7.89,42.24) v7(7.87,41.66) v7(7.88,41.04) v7(7.88,40.44) v7(7.88,39.83) v7(7.88,39.22) v7(7.87,38.7) v7(7.87,38.16) v7(7.87,37.7) v7(7.89,37.18) v7(7.87,36.69) v7(7.93,13.39) v7(7.93,12.96) v7(7.93,1.03) v7(7.94,20.3) v7(8.02,19.34) v7(8,18.79) v7(7.98,18.27) v7(7.98,17.71) v7(7.98,17.15) v7(7.98,16.59) v7(7.98,16.03) v7(7.98,15.48) v7(8,14.91) v7(7.96,14.33) v7(7.96,13.82) v7(8,12.48) v7(8,12.05) v7(7.96,11.69) v7(8,11.05) v7(8,10.61) v7(8,10.09) v7(8.04,45.28) v7(8.13,20.9) v7(8.11,19.84) v7(8.16,8.9) v7(8.18,3.18) v7(8.25,22.86) v7(8.24,22.36) v7(8.25,21.86) v7(8.25,21.5) v7(8.29,20.4) v7(8.29,1.03) v7(8.35,44.85) v7(8.34,7.98) v7(8.48,24.11) v7(8.48,23.61) v7(8.48,23.11) v7(8.48,22.61) v7(8.5,22.08) v7(8.52,20.96) v7(8.51,8.9) v7(8.57,46.02) v7(8.62,45.51) v7(8.65,44.38) v7(8.71,22.86) v7(8.7,22.35) v7(8.71,21.86) v7(8.65,21.47) v7(8.72,7.98) v7(8.67,3.46) v7(8.7,1.9) v7(8.7,1.55) v7(8.7,1.19) v7(8.77,45) v7(8.82,34.08) v7(8.77,33.36) v7(8.91,35.62) v7(8.89,35.1) v7(8.85,34.64) v7(8.87,8.9) v7(8.95,44.53) v7(8.94,44.09) v7(9,43.64) v7(9.03,42.68) v7(9.03,42.12) v7(9.03,41.53) v7(9.03,40.9) v7(9.03,40.29) v7(8.98,33.61) v7(8.98,33.11) v7(8.98,24.11) v7(9.04,43.16) v7(9.04,39.59) v7(9.04,38.99) v7(9.04,38.38) v7(9.05,37.77) v7(9.05,37.19) v7(9.08,36.61) v7(9.04,36.04) v7(9.1,19.35) v7(9.05,18.82) v7(9.06,18.27) v7(9.06,17.71) v7(9.06,17.15) v7(9.06,16.59) v7(9.06,16.03) v7(9.06,15.48) v7(9.06,14.87) v7(9.08,14.25) v7(9.05,13.69) v7(9.06,13.17) v7(9.07,12.63) v7(9.06,12.11) v7(9.13,11.71) v7(9.06,11.05) v7(9.07,10.57) v7(9.07,10.11) v7(9.08,7.4) v7(9.14,35.34) v7(9.15,34.85) v7(9.16,34.41) v7(9.17,33.9) v7(9.18,33.37) v7(9.24,19.88) v7(9.32,6.42) v7(9.28,2.9) v7(9.28,2.52) v7(9.28,2.14) v7(9.28,1.76) v7(9.28,1.38) v7(9.28,0.99) v7(9.42,20.36) v7(9.34,7.69) v7(9.36,7.07) v7(9.48,24.11) v7(9.46,16.77) v7(9.49,16.03) v7(9.44,15.17) v7(9.59,17.76) v7(9.66,46.03) v7(9.7,21.36) v7(9.64,20.9) v7(9.74,45.53) v7(9.74,22.85) v7(9.76,22.36) v7(9.76,21.86) v7(9.79,13.36) v7(9.79,12.86) v7(9.92,45.08) v7(9.98,24.11) v7(9.98,23.61) v7(9.98,23.11) v7(9.98,22.61) v7(9.97,22.1) v7(10.02,16.82) v7(9.99,15.22) v7(10.08,44.61) v7(10.07,16.08) v7(10.14,44.07) v7(10.2,43.57) v7(10.16,43.03) v7(10.16,42.5) v7(10.2,41.84) v7(10.17,41.15) v7(10.17,40.59) v7(10.17,39.96) v7(10.17,39.35) v7(10.17,38.71) v7(10.17,38.08) v7(10.2,37.44) v7(10.22,36.78) v7(10.21,22.85) v7(10.21,22.37) v7(10.32,36.28) v7(10.25,35.81) v7(10.25,35.3) v7(10.26,34.86) v7(10.26,34.38) v7(10.27,33.9) v7(10.26,33.36) v7(10.25,21.31) v7(10.3,13.36) v7(10.3,12.86) v7(10.38,44.34) v7(10.35,17.78) v7(10.53,35.53) v7(10.48,33.61) v7(10.48,33.11) v7(10.48,23.61) v7(10.48,23.11) v7(10.48,22.61) v7(10.48,22.1) v7(10.58,44.85) v7(10.6,35.05) v7(10.63,16.84) v7(10.6,16.05) v7(10.58,15.24) v7(10.73,45.41) v7(10.64,34.51) v7(10.67,33.94) v7(10.69,33.36) v7(10.7,22.86) v7(10.7,22.35) v7(10.72,21.82) v7(10.8,45.98) v7(10.76,21.34) v7(10.81,13.36) v7(10.81,12.86) v7(10.98,24.11) v7(10.96,20.78) v7(10.96,17.55) v7(11.19,2.14) v7(11.19,1.76) v7(11.19,1.38) v7(11.19,0.99) v7(11.31,43.48) v7(11.29,42.93) v7(11.31,41.96) v7(11.31,41.46) v7(11.32,40.92) v7(11.31,40.39) v7(11.31,39.86) v7(11.31,39.35) v7(11.31,38.79) v7(11.31,38.28) v7(11.31,37.79) v7(11.24,20.25) v7(11.39,42.5) v7(11.35,37.3) v7(11.37,19.82) v7(11.44,44.05) v7(11.44,36.81) v7(11.48,24.11) v7(11.49,19.31) v7(11.51,18.74) v7(11.51,18.18) v7(11.51,17.62) v7(11.51,17.06) v7(11.51,16.5) v7(11.52,15.94) v7(11.51,15.46) v7(11.51,14.97) v7(11.51,14.36) v7(11.51,13.75) v7(11.51,13.14) v7(11.51,12.53) v7(11.51,11.92) v7(11.62,44.54) v7(11.55,43.15) v7(11.54,36.3) v7(11.6,35.83) v7(11.67,35.28) v7(11.73,34.76) v7(11.67,10.6) v7(11.7,1.9) v7(11.67,1.55) v7(11.67,1.17) v7(11.76,45.01) v7(11.77,43.62) v7(11.77,34.28) v7(11.77,33.85) v7(11.78,33.35) v7(11.75,22.83) v7(11.77,22.38) v7(11.78,3.5) v7(11.89,46.01) v7(11.86,45.52) v7(11.89,35.59) v7(11.85,21.67) v7(11.87,9.76) v7(11.84,3.85) v7(12.03,35.1) v7(11.98,33.61) v7(11.98,33.11) v7(11.98,24.11) v7(11.98,23.61) v7(11.98,23.11) v7(11.98,22.61) v7(11.98,22.1) v7(12,21.14) v7(12.03,10.6) v7(12.03,44.05) v7(12.11,34.62) v7(12.04,4.14) v7(12.07,3.18) v7(12.03,1.03) v7(12.17,34.08) v7(12.18,33.36) v7(12.22,22.82) v7(12.18,22.38) v7(12.23,21.85) v7(12.23,20.68) v7(12.24,21.5) v7(12.25,9.76) v7(12.35,44.49) v7(12.42,40.63) v7(12.43,39.48) v7(12.42,38.91) v7(12.42,38.28) v7(12.34,21.07) v7(12.42,20.16) v7(12.38,10.6) v7(12.37,1.03) v7(12.48,41.84) v7(12.43,41.23) v7(12.43,40.06) v7(12.45,37.74) v7(12.52,37.24) v7(12.48,24.11) v7(12.52,20.5) v7(12.51,19.65) v7(12.52,3.18) v7(12.61,45.02) v7(12.58,42.37) v7(12.56,19.19) v7(12.57,18.74) v7(12.57,18.18) v7(12.57,17.62) v7(12.57,17.06) v7(12.57,16.5) v7(12.56,15.94) v7(12.56,15.46) v7(12.58,14.97) v7(12.58,14.36) v7(12.58,13.75) v7(12.58,13.14) v7(12.58,12.53) v7(12.58,12.12) v7(12.58,9.26) v7(12.59,8.82) v7(12.59,8.32) v7(12.65,36.78) v7(12.71,19.95) v7(12.73,1.03) v7(12.81,45.5) v7(12.77,42.91) v7(12.81,36.3) v7(12.83,19.45) v7(12.91,18.98) v7(12.95,46.01) v7(12.97,35.86) v7(12.98,24.11) v7(13.01,18.37) v7(13.03,17.76) v7(13.03,17.15) v7(13.03,16.55) v7(13.03,15.94) v7(13.03,15.33) v7(13.03,14.72) v7(13.03,14.11) v7(13.03,13.5) v7(13.03,12.89) v7(13.02,10.6) v7(13.03,10.09) v7(12.98,3.18) v7(13.03,43.41) v7(13.11,35.46) v7(13.04,12.53) v7(13.05,12.14) v7(13.04,11.67) v7(13.03,11.06) v7(13.09,5.83) v7(13.09,1.03) v7(13.17,34.98) v7(13.21,8.91) v7(13.14,5.26) v7(13.15,4.68) v7(13.14,4.13) v7(13.32,43.88) v7(13.33,35.24) v7(13.24,34.52) v7(13.28,34.2) v7(13.26,33.83) v7(13.27,33.35) v7(13.29,22.88) v7(13.28,22.37) v7(13.32,21.66) v7(13.38,7.98) v7(13.35,3.85) v7(13.51,34.81) v7(13.48,33.61) v7(13.48,33.11) v7(13.48,24.11) v7(13.48,23.61) v7(13.47,23.17) v7(13.48,22.61) v7(13.47,22.08) v7(13.51,3.59) v7(13.5,3.3) v7(13.5,2.99) v7(13.5,2.64) v7(13.5,2.28) v7(13.5,1.9) v7(13.47,1.55) v7(13.47,1.17) v7(13.59,41.37) v7(13.56,40.85) v7(13.56,40.33) v7(13.55,39.79) v7(13.57,39.28) v7(13.55,38.7) v7(13.57,38.18) v7(13.6,34.39) v7(13.6,20.97) v7(13.57,8.91) v7(13.64,44.32) v7(13.68,41.88) v7(13.64,37.6) v7(13.73,37.17) v7(13.65,33.89) v7(13.69,33.35) v7(13.69,22.88) v7(13.71,22.36) v7(13.7,21.77) v7(13.7,21.37) v7(13.73,20.4) v7(13.76,44.86) v7(13.76,7.98) v7(13.79,5.24) v7(13.86,42.4) v7(13.87,36.7) v7(13.88,19.82) v7(13.93,8.91) v7(13.87,3.18) v7(13.83,1.03) v7(13.96,45.46) v7(14,44.71) v7(13.98,24.11) v7(14.01,19.21) v7(14.08,46.02) v7(14.08,42.82) v7(14.06,36.31) v7(14.08,18.6) v7(14.13,18) v7(14.13,17.39) v7(14.13,16.78) v7(14.13,16.17) v7(14.13,15.56) v7(14.13,14.95) v7(14.13,14.34) v7(14.13,13.73) v7(14.13,13.12) v7(14.13,12.51) v7(14.1,11.65) v7(14.08,11.23) v7(14.08,10.79) v7(14.08,10.33) v7(14.13,12.09) v7(14.18,4.07) v7(14.17,1.03) v7(14.27,35.87) v7(14.29,18.29) v7(14.32,3.18) v7(14.35,45.03) v7(14.35,43.24) v7(14.41,17.71) v7(14.45,35.45) v7(14.48,24.11) v7(14.49,17.17) v7(14.52,16.77) v7(14.53,16.16) v7(14.53,15.55) v7(14.53,14.94) v7(14.53,14.33) v7(14.53,13.72) v7(14.53,13.12) v7(14.53,12.51) v7(14.52,6.25) v7(14.53,1.03) v7(14.62,35.04) v7(14.54,12.09) v7(14.57,4.07) v7(14.72,45.33) v7(14.71,43.69) v7(14.66,40.32) v7(14.67,39.82) v7(14.66,39.21) v7(14.66,38.7) v7(14.67,38.18) v7(14.71,34.36) v7(14.69,10.34) v7(14.73,41.52) v7(14.75,37.66) v7(14.77,33.83) v7(14.77,33.35) v7(14.73,22.85) v7(14.76,22.34) v7(14.79,21.53) v7(14.78,3.18) v7(14.85,34.71) v7(14.84,20.9) v7(14.9,9.5) v7(14.89,1.03) v7(14.94,42.04) v7(14.94,37.19) v7(15.03,34.14) v7(14.98,33.61) v7(14.98,33.11) v7(14.98,24.11) v7(14.98,23.61) v7(14.98,23.11) v7(14.98,22.61) v7(14.97,22.05) v7(14.97,20.3) v7(15.06,45.63) v7(15.08,44.07) v7(15.09,19.61) v7(15.05,10.34) v7(15.17,42.41) v7(15.19,36.66) v7(15.16,33.36) v7(15.17,22.85) v7(15.2,22.35) v7(15.2,21.77) v7(15.22,21.26) v7(15.21,20.7) v7(15.21,20.02) v7(15.23,19.13) v7(15.16,3.84) v7(15.23,46.05) v7(15.33,18.67) v7(15.28,9.5) v7(15.31,3.55) v7(15.31,3.26) v7(15.3,2.97) v7(15.3,2.61) v7(15.3,2.26) v7(15.3,1.88) v7(15.27,1.52) v7(15.27,1.14) v7(15.4,36.22) v7(15.4,10.34) v7(15.48,44.43) v7(15.44,42.72) v7(15.48,24.11) v7(15.45,18.21) v7(15.52,17.75) v7(15.61,35.77) v7(15.56,17.2) v7(15.59,16.66) v7(15.63,16.1) v7(15.63,1.03) v7(15.65,15.49) v7(15.65,14.88) v7(15.65,14.27) v7(15.65,13.66) v7(15.65,13.05) v7(15.65,12.44) v7(15.68,12.07) v7(15.67,3.18) v7(15.84,44.75) v7(15.86,43.12) v7(15.84,35.27) v7(15.85,17.3) v7(16,34.81) v7(15.98,32.11) v7(15.98,24.11) v7(15.99,16.75) v7(16.03,16.28) v7(16.03,15.67) v7(15.97,1.03) v7(16.07,45.19) v7(16.12,34.31) v7(16.06,15.06) v7(16.06,14.45) v7(16.06,13.84) v7(16.06,13.23) v7(16.06,12.62) v7(16.06,12.09) v7(16.04,11.71) v7(16.08,11.29) v7(16.1,10.81) v7(16.09,10.33) v7(16.04,4.07) v7(16.12,3.18) v7(16.18,43.5) v7(16.23,33.85) v7(16.23,22.34) v7(16.27,45.6) v7(16.32,45.05) v7(16.27,33.34) v7(16.23,22.86) v7(16.25,21.77) v7(16.26,21.22) v7(16.26,20.71) v7(16.26,20.14) v7(16.3,19.58) v7(16.28,8.92) v7(16.33,1.03) v7(16.34,46.08) v7(16.39,22.08) v7(16.39,19) v7(16.43,7.98) v7(16.42,4.07) v7(16.53,43.81) v7(16.48,33.61) v7(16.48,33.11) v7(16.48,32.61) v7(16.48,32.11) v7(16.48,24.11) v7(16.48,23.61) v7(16.48,22.61) v7(16.57,18.44) v7(16.58,3.18) v7(16.66,45.4) v7(16.64,8.92) v7(16.69,1.03) v7(16.8,17.91) v7(16.81,7.98) v7(16.75,6.33) v7(16.97,45.81) v7(16.95,44.15) v7(16.98,17.35) v7(16.99,8.92) v7(16.95,5.93) v7(16.94,3.86) v7(17.13,39.57) v7(17.11,16.77) v7(17.09,3.56) v7(17.09,3.27) v7(17.1,1.88) v7(17.07,1.52) v7(17.07,1.14) v7(17.22,46.3) v7(17.16,16.16) v7(17.15,15.56) v7(17.15,14.95) v7(17.15,14.34) v7(17.15,13.73) v7(17.15,13.12) v7(17.15,12.51) v7(17.16,12.07) v7(17.18,11.71) v7(17.14,11.09) v7(17.15,10.65) v7(17.15,10.09) v7(17.28,33.56) v7(17.35,44.53) v7(17.47,3.18) v7(17.43,1.03) v7(17.54,33.18) v7(17.68,44.92) v7(17.72,38.58) v7(17.77,1.03) v7(17.92,45.3) v7(17.92,32.92) v7(17.86,32.53) v7(17.84,4.07) v7(17.92,3.18) v7(18.12,45.67) v7(18.13,6.98) v7(18.13,1.03) v7(18.22,4.07) v7(18.3,46.07) v7(18.43,9.55) v7(18.38,3.18) v7(18.49,1.03) v7(18.55,14.75) v7(18.83,43.45) v7(18.8,3.78) v7(18.84,3.49) v7(18.89,3.21) v7(18.89,2.93) v7(18.88,2.62) v7(18.91,2.26) v7(18.91,1.91) v7(18.9,1.55) v7(18.9,1.17) v7(18.93,9.68) v7(19.19,36.35) v7(19.19,35.72) v7(20.02,43.11) v7(20.12,10.77) v7(20.15,11.75) v8(0.53,38.48) v8(0.52,28.26) v8(0.56,36.54) v8(0.58,35.37) v8(0.58,31.17) v8(0.55,27.28) v8(0.98,40.53) v8(0.94,39.26) v8(1.03,28.6) v8(1.03,27.84) v8(1,27.03) v8(1.12,41.98) v8(1.08,30.37) v8(1.28,42.87) v8(1.44,32.7) v8(1.44,31.16) v8(1.52,3.54) v8(1.48,3.26) v8(1.47,2.97) v8(1.47,2.59) v8(1.47,2.23) v8(1.47,1.88) v8(1.47,1.52) v8(1.47,1.17) v8(1.54,31.78) v8(1.54,31.02) v8(1.54,30.26) v8(1.54,29.49) v8(1.66,27.23) v8(1.66,10.06) v8(1.76,23.55) v8(1.76,23.14) v8(1.83,1.03) v8(1.97,33.43) v8(2.09,9.67) v8(2.22,43.94) v8(2.14,36.76) v8(2.17,29.49) v8(2.17,28.86) v8(2.17,10.44) v8(2.17,10.06) v8(2.17,1.03) v8(2.33,44.72) v8(2.28,42.73) v8(2.3,31.78) v8(2.3,31.02) v8(2.3,30.26) v8(2.37,28.09) v8(2.45,41.74) v8(2.45,41.28) v8(2.49,34.59) v8(2.47,9.29) v8(2.53,1.03) v8(2.63,10.8) v8(2.63,10.44) v8(2.63,10.06) v8(2.67,45.08) v8(2.81,29.49) v8(2.81,28.86) v8(2.75,9.73) v8(2.89,8.86) v8(2.87,7.11) v8(2.93,4.11) v8(2.89,1.03) v8(3.01,33.92) v8(2.97,23.83) v8(3,5.07) v8(2.96,4.58) v8(3.09,43.98) v8(3.06,32.54) v8(3.06,31.78) v8(3.06,31.02) v8(3.11,9.96) v8(3.03,9.48) v8(3.14,36.49) v8(3.16,23.14) v8(3.19,7.56) v8(3.14,5.55) v8(3.16,3.84) v8(3.31,42.18) v8(3.31,3.57) v8(3.31,3.28) v8(3.31,3) v8(3.31,2.67) v8(3.31,2.32) v8(3.31,1.93) v8(3.31,1.58) v8(3.31,1.22) v8(3.4,9.31) v8(3.4,8.75) v8(3.4,8.14) v8(3.44,38.8) v8(3.58,6.22) v8(3.68,5.22) v8(3.64,1.05) v8(3.75,34.62) v8(3.77,11.7) v8(3.82,5.71) v8(4,38.52) v8(3.95,30.64) v8(3.98,23.61) v8(3.98,23.11) v8(3.93,6.63) v8(3.97,1.03) v8(4.06,26.12) v8(4.07,24.11) v8(4.13,11.7) v8(4.05,6.18) v8(4.22,7.12) v8(4.29,14.44) v8(4.29,14.06) v8(4.29,13.68) v8(4.33,1.03) v8(4.42,15.94) v8(4.42,15.56) v8(4.42,15.18) v8(4.37,6.61) v8(4.49,44.03) v8(4.48,24.11) v8(4.51,23.04) v8(4.5,9.27) v8(4.5,8.82) v8(4.51,8.18) v8(4.43,7.62) v8(4.57,26.13) v8(4.68,14.44) v8(4.68,14.06) v8(4.68,6.99) v8(4.73,4.09) v8(4.69,1.03) v8(4.8,15.94) v8(4.8,15.18) v8(4.79,5.14) v8(4.74,4.63) v8(4.86,39) v8(4.84,31.4) v8(4.84,30.64) v8(4.84,29.87) v8(4.84,29.24) v8(4.9,7.47) v8(4.96,33.18) v8(4.98,24.11) v8(4.96,23.04) v8(4.96,11.51) v8(5.01,5.61) v8(4.94,3.87) v8(5.13,44.94) v8(5.1,3.6) v8(5.1,3.31) v8(5.1,1.88) v8(5.1,1.52) v8(5.14,34.65) v8(5.19,15.94) v8(5.19,15.56) v8(5.19,15.18) v8(5.27,35.73) v8(5.32,14.44) v8(5.32,14.06) v8(5.32,13.68) v8(5.32,11.71) v8(5.29,5.96) v8(5.47,33.18) v8(5.48,24.11) v8(5.48,23.61) v8(5.48,23.11) v8(5.49,5.18) v8(5.43,1.03) v8(5.57,15.94) v8(5.57,15.56) v8(5.57,15.18) v8(5.63,6.4) v8(5.57,5.6) v8(5.7,14.44) v8(5.7,14.06) v8(5.7,13.68) v8(5.68,11.71) v8(5.77,1.03) v8(5.98,24.11) v8(6.01,23.04) v8(6,11.49) v8(5.98,7.25) v8(6.13,1.03) v8(6.19,34.68) v8(6.36,37.38) v8(6.39,8.12) v8(6.49,33.18) v8(6.48,24.11) v8(6.46,23.04) v8(6.46,9.26) v8(6.45,8.83) v8(6.49,1.03) v8(6.59,5.09) v8(6.54,4.58) v8(6.54,4.07) v8(6.72,5.66) v8(6.81,37.63) v8(6.74,11.69) v8(6.75,3.84) v8(6.9,3.57) v8(6.9,3.28) v8(6.9,2.99) v8(6.9,2.61) v8(6.9,2.26) v8(6.9,1.9) v8(6.9,1.55) v8(6.9,1.19) v8(6.98,44.9) v8(6.94,34.35) v8(7,33.18) v8(6.98,24.11) v8(6.98,23.61) v8(6.98,23.11) v8(6.96,6.27) v8(7.07,41.31) v8(7.18,6.82) v8(7.23,1.03) v8(7.3,37.63) v8(7.25,11.69) v8(7.27,5.22) v8(7.24,4.64) v8(7.35,7.35) v8(7.52,41.85) v8(7.48,24.11) v8(7.5,23.04) v8(7.51,18.47) v8(7.51,18.11) v8(7.51,17.74) v8(7.53,8.18) v8(7.45,5.84) v8(7.57,17.09) v8(7.57,16.73) v8(7.54,13.37) v8(7.54,12.94) v8(7.54,9.26) v8(7.54,8.81) v8(7.57,1.03) v8(7.75,6.4) v8(7.9,43.26) v8(7.89,33.18) v8(7.89,18.47) v8(7.89,18.11) v8(7.89,17.74) v8(7.93,13.39) v8(7.93,12.96) v8(7.93,1.03) v8(7.96,23.04) v8(7.95,17.09) v8(7.95,16.73) v8(7.96,11.69) v8(7.99,7.42) v8(7.94,6.88) v8(8.11,40.79) v8(8.27,18.47) v8(8.27,18.11) v8(8.27,17.74) v8(8.33,4.09) v8(8.29,1.03) v8(8.39,33.18) v8(8.33,17.09) v8(8.33,16.73) v8(8.37,11.71) v8(8.36,5.03) v8(8.33,4.57) v8(8.48,24.11) v8(8.48,23.61) v8(8.48,23.11) v8(8.55,5.55) v8(8.6,3.75) v8(8.72,11.71) v8(8.67,3.46) v8(8.7,1.9) v8(8.7,1.55) v8(8.7,1.19) v8(8.91,6.22) v8(8.98,24.11) v8(9,23.04) v8(8.99,3.51) v8(9.13,11.71) v8(9.08,7.4) v8(9.07,6.76) v8(9.14,19.28) v8(9.14,18.93) v8(9.28,39.38) v8(9.32,6.42) v8(9.28,2.9) v8(9.28,2.52) v8(9.28,2.14) v8(9.28,1.76) v8(9.28,1.38) v8(9.28,0.99) v8(9.37,37.6) v8(9.35,37.13) v8(9.34,34.76) v8(9.35,34.31) v8(9.39,12.73) v8(9.34,7.69) v8(9.36,7.07) v8(9.48,24.11) v8(9.51,23.04) v8(9.52,19.28) v8(9.52,18.93) v8(9.54,13.11) v8(9.66,17.2) v8(9.66,16.43) v8(9.82,37.59) v8(9.79,20.25) v8(9.85,36.06) v8(9.9,19.28) v8(9.9,18.93) v8(9.99,39.62) v8(9.98,24.11) v8(9.98,23.61) v8(9.98,23.11) v8(10.04,13.11) v8(10.2,43.57) v8(10.3,16.43) v8(10.43,17.32) v8(10.48,23.61) v8(10.48,23.11) v8(10.55,13.11) v8(10.8,19.27) v8(10.8,18.91) v8(10.92,34.21) v8(10.98,24.11) v8(11.06,23.04) v8(11.06,13.11) v8(11.18,19.27) v8(11.18,18.91) v8(11.19,2.14) v8(11.19,1.76) v8(11.19,1.38) v8(11.19,0.99) v8(11.31,40.67) v8(11.31,40.39) v8(11.31,38.28) v8(11.31,37.79) v8(11.48,24.11) v8(11.47,23.04) v8(11.56,19.27) v8(11.56,18.91) v8(11.6,7.11) v8(11.68,40.62) v8(11.68,40.3) v8(11.7,1.9) v8(11.67,1.55) v8(11.67,1.17) v8(11.76,6.53) v8(11.78,3.5) v8(11.85,11.71) v8(11.84,3.85) v8(11.98,24.11) v8(11.98,23.61) v8(11.98,23.11) v8(11.94,19.27) v8(11.94,18.91) v8(12.04,43.82) v8(12.11,40.15) v8(12.04,4.14) v8(12.03,1.03) v8(12.2,11.71) v8(12.42,38.28) v8(12.35,37.74) v8(12.37,37.19) v8(12.36,18.83) v8(12.37,18.41) v8(12.37,1.03) v8(12.43,40.9) v8(12.43,40.06) v8(12.44,27.11) v8(12.48,24.11) v8(12.53,23.07) v8(12.58,9.26) v8(12.59,8.82) v8(12.59,8.32) v8(12.73,1.03) v8(12.98,24.11) v8(13.02,23.07) v8(13.11,35.46) v8(13.04,11.67) v8(13.09,5.83) v8(13.09,1.03) v8(13.17,34.98) v8(13.14,5.26) v8(13.15,4.68) v8(13.14,4.13) v8(13.3,40.52) v8(13.33,35.24) v8(13.24,34.52) v8(13.28,34.2) v8(13.4,38.4) v8(13.42,11.71) v8(13.35,3.85) v8(13.51,34.81) v8(13.48,24.11) v8(13.48,23.61) v8(13.51,3.59) v8(13.5,3.3) v8(13.5,2.99) v8(13.5,2.64) v8(13.5,2.28) v8(13.5,1.9) v8(13.47,1.55) v8(13.47,1.17) v8(13.6,34.39) v8(13.73,37.17) v8(13.77,11.72) v8(13.79,5.24) v8(13.83,1.03) v8(13.98,33.18) v8(13.98,24.11) v8(13.98,23.07) v8(14.1,11.65) v8(14.18,7.56) v8(14.17,1.03) v8(14.42,39.74) v8(14.36,16.97) v8(14.34,7.03) v8(14.49,33.18) v8(14.48,24.11) v8(14.46,23.07) v8(14.53,6.55) v8(14.53,1.03) v8(14.56,9.26) v8(14.55,8.8) v8(14.55,8.24) v8(14.7,42.85) v8(14.72,6.02) v8(14.76,7.22) v8(14.85,34.71) v8(14.9,16.92) v8(14.9,16.44) v8(14.9,11.46) v8(14.85,5.58) v8(14.91,5.11) v8(14.89,1.03) v8(15.01,39.75) v8(15.01,39.05) v8(15.03,34.14) v8(14.98,24.11) v8(14.98,23.61) v8(14.98,23.11) v8(14.98,6.71) v8(14.94,4.61) v8(14.95,4.07) v8(15.06,30.53) v8(15.16,3.84) v8(15.33,11.46) v8(15.3,6.13) v8(15.31,3.55) v8(15.31,3.26) v8(15.3,2.97) v8(15.3,2.61) v8(15.3,2.26) v8(15.3,1.88) v8(15.27,1.52) v8(15.27,1.14) v8(15.51,30.61) v8(15.48,24.11) v8(15.48,16.92) v8(15.48,16.44) v8(15.52,5.62) v8(15.56,33.23) v8(15.58,23.04) v8(15.63,9.26) v8(15.63,8.8) v8(15.63,1.03) v8(15.64,8.29) v8(15.65,5.06) v8(15.75,7.72) v8(15.91,33.23) v8(15.98,24.11) v8(16.01,23.04) v8(15.99,7.15) v8(15.97,1.03) v8(16.12,34.31) v8(16.04,11.71) v8(16.19,7.45) v8(16.29,6.64) v8(16.33,1.03) v8(16.37,11.71) v8(16.48,32.61) v8(16.48,24.11) v8(16.48,23.61) v8(16.45,7.02) v8(16.62,31.55) v8(16.55,6.13) v8(16.71,24.25) v8(16.7,5.58) v8(16.69,1.03) v8(16.78,20.35) v8(16.78,19.84) v8(16.78,11.71) v8(16.79,6.65) v8(16.75,5.01) v8(16.75,4.53) v8(16.74,4.07) v8(16.9,19.21) v8(17,31.55) v8(16.94,3.86) v8(17.13,39.57) v8(17.04,6.26) v8(17.09,3.56) v8(17.09,3.27) v8(17.1,1.88) v8(17.07,1.52) v8(17.07,1.14) v8(17.21,40.8) v8(17.16,20.73) v8(17.16,18.44) v8(17.18,11.71) v8(17.28,33.56) v8(17.26,5.82) v8(17.41,32.8) v8(17.41,32.41) v8(17.41,32.03) v8(17.41,31.65) v8(17.41,17.81) v8(17.47,7.55) v8(17.43,1.03) v8(17.54,38.87) v8(17.56,38.15) v8(17.54,33.18) v8(17.54,17.17) v8(17.66,16.41) v8(17.66,15.78) v8(17.66,15.02) v8(17.66,14.38) v8(17.66,13.62) v8(17.66,12.98) v8(17.66,12.35) v8(17.66,11.71) v8(17.82,7.13) v8(17.77,1.03) v8(17.92,32.92) v8(17.86,32.53) v8(17.92,18.7) v8(17.87,10.9) v8(17.84,10.49) v8(17.84,10.06) v8(18.05,17.94) v8(18.13,1.03) v8(18.19,35.73) v8(18.17,34.8) v8(18.15,32.01) v8(18.17,17.17) v8(18.14,6.62) v8(18.3,19.11) v8(18.3,16.54) v8(18.3,15.9) v8(18.3,15.02) v8(18.3,14.38) v8(18.3,13.62) v8(18.3,12.98) v8(18.3,12.35) v8(18.3,11.71) v8(18.43,9.55) v8(18.4,5.9) v8(18.48,38.17) v8(18.51,5.36) v8(18.49,1.03) v8(18.53,31.92) v8(18.54,4.63) v8(18.57,4.07) v8(18.71,18.69) v8(18.71,18.36) v8(18.83,43.45) v8(18.8,3.78) v8(18.85,39.12) v8(18.91,30.23) v8(18.87,17.35) v8(18.84,3.49) v8(18.89,3.21) v8(18.89,2.93) v8(18.88,2.62) v8(18.91,2.26) v8(18.91,1.91) v8(18.9,1.55) v8(18.9,1.17) v8(18.93,32.01) v8(18.94,16.92) v8(18.94,16.54) v8(18.96,16.18) v8(18.96,15.77) v8(18.93,9.68) v8(19.06,18.69) v8(19.06,18.36) v8(19.19,36.35) v8(19.19,35.72) v8(19.19,33.94) v8(19.19,33.3) v8(19.19,32.67) v8(19.19,31.27) v8(19.19,30.64) v8(19.26,31.98) v8(19.29,16.92) v8(19.29,16.54) v8(19.31,16.18) v8(19.31,15.77) v8(19.37,27.04) v8(19.37,26.5) v8(19.37,26) v8(19.37,25.51) v8(19.4,18.7) v8(19.4,18.37) v8(19.53,24.95) v8(19.52,24.29) v8(19.52,23.75) v8(19.52,23.24) v8(19.52,22.76) v8(19.52,22.23) v8(19.52,21.75) v8(19.64,16.93) v8(19.64,16.54) v8(19.65,16.19) v8(19.65,15.78) v8(20.02,43.11) v8(20.13,41.19) v8(20.16,41.69) v8(20.13,40.44) v9(0.56,39.56) v9(0.56,38.98) v9(0.57,38.29) v9(0.68,11.74) v9(0.67,10.82) v9(1.43,11.44) v9(1.66,10.06) v9(1.78,10.59) v9(2.09,9.67) v9(2.09,2.98) v9(2.17,1.03) v9(2.47,9.29) v9(2.53,1.03) v9(2.55,2.98) v9(2.69,12) v9(2.89,8.86) v9(2.89,1.03) v9(3.01,2.98) v9(3.9,2.98) v9(3.98,23.61) v9(3.98,23.11) v9(3.98,22.61) v9(3.97,1.03) v9(4.07,24.11) v9(4.15,22.08) v9(4.33,1.03) v9(4.36,2.98) v9(4.48,24.61) v9(4.48,24.11) v9(4.69,1.03) v9(4.81,2.98) v9(4.98,24.11) v9(5.29,39.07) v9(5.26,38.33) v9(5.48,24.11) v9(5.48,23.61) v9(5.48,23.11) v9(5.48,22.61) v9(5.47,22.05) v9(5.7,2.98) v9(5.77,1.03) v9(5.98,33.61) v9(5.98,33.11) v9(5.98,24.11) v9(6.13,1.03) v9(6.16,2.98) v9(6.48,24.11) v9(6.49,1.03) v9(6.62,2.98) v9(6.98,24.11) v9(6.98,23.61) v9(6.98,23.11) v9(6.98,22.61) v9(6.97,22.08) v9(7.48,33.61) v9(7.48,33.11) v9(7.48,24.11) v9(7.48,2.98) v9(7.57,1.03) v9(7.86,41.34) v9(7.93,1.03) v9(7.94,2.98) v9(8.29,1.03) v9(8.39,2.98) v9(8.48,24.11) v9(8.48,23.61) v9(8.48,23.11) v9(8.48,22.61) v9(8.5,22.08) v9(9.03,40.6) v9(8.98,33.61) v9(8.98,33.11) v9(8.98,24.11) v9(9.03,41.21) v9(9.04,38.08) v9(9.04,37.48) v9(9.48,24.11) v9(9.98,24.11) v9(9.98,23.61) v9(9.98,23.11) v9(9.98,22.61) v9(9.97,22.1) v9(10.18,41.51) v9(10.19,40.29) v9(10.18,37.77) v9(10.21,37.1) v9(10.48,33.61) v9(10.48,33.11) v9(10.48,23.61) v9(10.48,23.11) v9(10.48,22.61) v9(10.48,22.1) v9(10.98,24.11) v9(11.48,24.11) v9(11.98,33.61) v9(11.98,33.11) v9(11.98,24.11) v9(11.98,23.61) v9(11.98,23.11) v9(11.98,22.61) v9(11.98,22.1) v9(12.31,2.98) v9(12.37,1.03) v9(12.43,41.54) v9(12.44,40.93) v9(12.48,24.11) v9(12.73,1.03) v9(12.76,2.98) v9(12.98,24.11) v9(13.09,1.03) v9(13.22,2.98) v9(13.48,33.61) v9(13.48,33.11) v9(13.48,24.11) v9(13.48,23.61) v9(13.48,22.61) v9(13.47,22.08) v9(13.58,37.89) v9(13.98,24.11) v9(14.08,2.98) v9(14.17,1.03) v9(14.48,24.11) v9(14.53,1.03) v9(14.54,2.98) v9(14.89,1.03) v9(14.98,33.61) v9(14.98,33.11) v9(14.98,24.11) v9(14.98,23.61) v9(14.98,23.11) v9(14.98,22.61) v9(14.97,22.05) v9(15,2.98) v9(15.48,24.11) v9(15.89,2.98) v9(15.98,32.11) v9(15.98,24.11) v9(15.97,1.03) v9(16.33,1.03) v9(16.39,22.08) v9(16.34,2.98) v9(16.48,33.61) v9(16.48,33.11) v9(16.48,32.61) v9(16.48,32.11) v9(16.48,24.11) v9(16.48,23.61) v9(16.48,22.61) v9(16.69,1.03) v9(16.8,2.98) v9(17.72,2.98) v9(17.77,1.03) v9(18.13,1.03) v9(18.17,2.98) v9(18.43,9.55) v9(18.49,1.03) v9(18.63,2.98) v9(18.9,16.85) v9(18.92,16.21) v9(18.93,15.54) v9(18.93,9.68) v9(19.92,31) v9(19.93,17.11) v9(19.96,16.56) v9(19.96,15.99) v9(20.12,10.77) v9(20.15,11.75) v10(0.51,17.69) v10(0.98,17.68) v10(1.18,33.81) v10(1.28,29.78) v10(1.41,32.39) v10(1.46,38.47) v10(1.43,31.14) v10(1.47,2.97) v10(1.47,2.59) v10(1.47,2.23) v10(1.47,1.88) v10(1.47,1.52) v10(1.47,1.17) v10(1.54,17.68) v10(1.71,39.96) v10(1.71,34.37) v10(1.68,12.19) v10(1.79,41.89) v10(1.99,45.94) v10(1.94,41.61) v10(2.18,17.68) v10(2.14,12.74) v10(2.19,3.59) v10(2.3,45.51) v10(2.33,44.72) v10(2.25,35.79) v10(2.4,33.63) v10(2.53,34.57) v10(2.58,42.35) v10(2.58,40.16) v10(2.65,45.18) v10(2.68,36.53) v10(2.65,3.59) v10(2.75,39.25) v10(2.82,17.68) v10(3.01,44.8) v10(2.98,41.38) v10(2.93,33.15) v10(3.01,31.27) v10(3.22,46.15) v10(3.18,30.48) v10(3.24,42.73) v10(3.24,33.74) v10(3.31,3) v10(3.31,2.67) v10(3.31,2.32) v10(3.31,1.93) v10(3.31,1.58) v10(3.31,1.22) v10(3.41,44.42) v10(3.39,36.83) v10(3.36,34.62) v10(3.45,17.68) v10(3.54,45.83) v10(3.83,44.01) v10(3.77,11.64) v10(3.89,45.47) v10(3.99,3.59) v10(4.09,17.68) v10(4.21,46.02) v10(4.15,11.64) v10(4.28,45.08) v10(4.26,43.57) v10(4.36,45.58) v10(4.48,28.11) v10(4.45,3.59) v10(4.6,45.15) v10(4.58,39.27) v10(4.58,38.64) v10(4.58,38) v10(4.58,37.37) v10(4.58,36.73) v10(4.71,44.79) v10(4.63,43.2) v10(4.72,34.29) v10(4.66,33.84) v10(4.68,33.35) v10(4.72,17.68) v10(4.72,6.45) v10(4.7,5.49) v10(4.77,34.73) v10(4.87,35.2) v10(4.98,35.69) v10(5.13,44.38) v10(5.05,42.77) v10(5.09,40.67) v10(5.09,40.03) v10(5.09,38.64) v10(5.09,38) v10(5.09,37.37) v10(5.13,36.19) v10(5.1,1.88) v10(5.1,1.52) v10(5.29,36.68) v10(5.25,22.87) v10(5.24,22.33) v10(5.27,11.64) v10(5.3,9.9) v10(5.35,46.04) v10(5.36,17.68) v10(5.51,43.97) v10(5.44,42.33) v10(5.43,37.17) v10(5.61,45.59) v10(5.58,41.79) v10(5.6,41.26) v10(5.61,40.7) v10(5.6,40.07) v10(5.6,39.45) v10(5.6,38.85) v10(5.59,38.26) v10(5.56,37.71) v10(5.69,22.87) v10(5.7,22.33) v10(5.65,11.64) v10(5.69,9.9) v10(5.82,34.42) v10(5.77,33.89) v10(5.77,33.36) v10(5.79,3.59) v10(5.91,43.58) v10(5.91,34.94) v10(5.94,45.24) v10(5.99,17.68) v10(6.04,35.46) v10(6.2,35.94) v10(6.2,33.89) v10(6.18,33.37) v10(6.31,43.14) v10(6.31,34.42) v10(6.25,3.59) v10(6.34,46.09) v10(6.34,44.83) v10(6.39,36.49) v10(6.42,35) v10(6.5,45.54) v10(6.58,42.63) v10(6.59,36.94) v10(6.55,35.59) v10(6.63,17.68) v10(6.66,44.5) v10(6.72,42.11) v10(6.72,41.51) v10(6.72,40.92) v10(6.72,40.36) v10(6.72,39.75) v10(6.72,39.12) v10(6.73,38.54) v10(6.73,37.95) v10(6.68,37.44) v10(6.64,36.13) v10(6.79,45.08) v10(6.73,36.63) v10(6.75,22.87) v10(6.74,22.36) v10(6.87,11.64) v10(6.9,2.99) v10(6.9,2.61) v10(6.9,2.26) v10(6.9,1.9) v10(6.9,1.55) v10(6.9,1.19) v10(7.01,44.11) v10(7.1,44.7) v10(7.2,22.87) v10(7.21,22.34) v10(7.3,43.74) v10(7.31,33.91) v10(7.27,33.34) v10(7.26,17.68) v10(7.25,11.64) v10(7.43,44.24) v10(7.4,34.37) v10(7.46,46.14) v10(7.51,34.91) v10(7.45,4.84) v10(7.57,43.26) v10(7.59,3.59) v10(7.72,45.69) v10(7.64,35.46) v10(7.7,34.01) v10(7.69,33.35) v10(7.75,43.75) v10(7.8,36.21) v10(7.83,35.77) v10(7.78,35.15) v10(7.75,34.59) v10(7.9,43.26) v10(7.84,42.72) v10(7.89,42.24) v10(7.87,41.66) v10(7.88,41.04) v10(7.88,40.44) v10(7.88,39.83) v10(7.88,39.22) v10(7.87,38.7) v10(7.87,38.16) v10(7.87,37.7) v10(7.89,37.18) v10(7.87,36.69) v10(7.9,17.68) v10(8.04,45.28) v10(8.05,3.59) v10(8.25,22.86) v10(8.24,22.36) v10(8.31,7.03) v10(8.35,44.85) v10(8.37,11.64) v10(8.34,9.87) v10(8.33,6.16) v10(8.57,46.02) v10(8.62,45.51) v10(8.65,44.38) v10(8.71,22.86) v10(8.7,22.35) v10(8.72,17.67) v10(8.72,9.87) v10(8.7,1.9) v10(8.7,1.55) v10(8.7,1.19) v10(8.77,45) v10(8.82,34.08) v10(8.77,33.36) v10(8.75,11.64) v10(8.91,35.62) v10(8.89,35.1) v10(8.85,34.64) v10(8.95,44.53) v10(8.94,44.09) v10(9,43.64) v10(9.03,42.68) v10(9.03,42.12) v10(9.03,41.53) v10(9.03,40.9) v10(9.03,40.29) v10(9.04,43.16) v10(9.04,39.59) v10(9.04,38.99) v10(9.04,38.38) v10(9.05,37.77) v10(9.05,37.19) v10(9.08,36.61) v10(9.04,36.04) v10(9.14,35.34) v10(9.15,34.85) v10(9.16,34.41) v10(9.17,33.9) v10(9.18,33.37) v10(9.36,17.67) v10(9.66,46.03) v10(9.74,45.53) v10(9.74,22.85) v10(9.76,22.36) v10(9.92,45.08) v10(9.99,17.67) v10(10.08,44.61) v10(10.14,44.07) v10(10.2,43.57) v10(10.16,43.03) v10(10.16,42.5) v10(10.2,41.84) v10(10.17,41.15) v10(10.17,40.59) v10(10.17,39.96) v10(10.17,39.35) v10(10.17,38.71) v10(10.17,38.08) v10(10.2,37.44) v10(10.22,36.78) v10(10.21,22.85) v10(10.21,22.37) v10(10.32,36.28) v10(10.25,35.81) v10(10.25,35.3) v10(10.26,34.86) v10(10.26,34.38) v10(10.27,33.9) v10(10.26,33.36) v10(10.38,44.34) v10(10.53,35.53) v10(10.58,44.85) v10(10.6,35.05) v10(10.63,17.67) v10(10.73,45.41) v10(10.64,34.51) v10(10.67,33.94) v10(10.69,33.36) v10(10.7,22.86) v10(10.7,22.35) v10(10.8,45.98) v10(11.31,43.48) v10(11.29,42.93) v10(11.31,41.96) v10(11.31,41.46) v10(11.32,40.92) v10(11.31,40.39) v10(11.31,39.86) v10(11.31,39.35) v10(11.31,38.79) v10(11.31,38.28) v10(11.31,37.79) v10(11.26,17.67) v10(11.39,42.5) v10(11.35,37.3) v10(11.44,44.05) v10(11.44,36.81) v10(11.62,44.54) v10(11.55,43.15) v10(11.54,36.3) v10(11.6,35.83) v10(11.67,35.28) v10(11.73,34.76) v10(11.7,1.9) v10(11.67,1.55) v10(11.67,1.17) v10(11.76,45.01) v10(11.77,43.62) v10(11.77,34.28) v10(11.77,33.85) v10(11.78,33.35) v10(11.75,22.83) v10(11.77,22.38) v10(11.77,11.69) v10(11.89,46.01) v10(11.86,45.52) v10(11.89,35.59) v10(11.9,17.67) v10(12.03,35.1) v10(12.03,44.05) v10(12.11,34.62) v10(12.17,34.08) v10(12.18,33.36) v10(12.22,22.82) v10(12.18,22.38) v10(12.18,11.69) v10(12.35,44.49) v10(12.42,40.63) v10(12.43,39.48) v10(12.42,38.91) v10(12.42,38.28) v10(12.39,3.59) v10(12.48,41.84) v10(12.43,41.23) v10(12.43,40.06) v10(12.45,37.74) v10(12.52,37.24) v10(12.53,17.67) v10(12.61,45.02) v10(12.58,42.37) v10(12.58,14.97) v10(12.58,14.36) v10(12.58,13.75) v10(12.58,13.14) v10(12.58,12.53) v10(12.65,36.78) v10(12.81,45.5) v10(12.77,42.91) v10(12.81,36.3) v10(12.85,3.59) v10(12.95,46.01) v10(12.97,35.86) v10(13.03,17.15) v10(13.03,16.55) v10(13.03,15.94) v10(13.03,15.33) v10(13.03,14.72) v10(13.03,14.11) v10(13.03,13.5) v10(13.03,12.89) v10(13.03,43.41) v10(13.11,35.46) v10(13.17,34.98) v10(13.17,17.67) v10(13.32,43.88) v10(13.33,35.24) v10(13.24,34.52) v10(13.28,34.2) v10(13.26,33.83) v10(13.27,33.35) v10(13.29,22.88) v10(13.28,22.37) v10(13.4,11.69) v10(13.38,9.9) v10(13.51,34.81) v10(13.5,2.99) v10(13.5,2.64) v10(13.5,2.28) v10(13.5,1.9) v10(13.47,1.55) v10(13.47,1.17) v10(13.59,41.37) v10(13.56,40.85) v10(13.56,40.33) v10(13.55,39.79) v10(13.57,39.28) v10(13.55,38.7) v10(13.57,38.18) v10(13.6,34.39) v10(13.64,44.32) v10(13.68,41.88) v10(13.64,37.6) v10(13.73,37.17) v10(13.65,33.89) v10(13.69,33.35) v10(13.69,22.88) v10(13.71,22.36) v10(13.76,44.86) v10(13.8,17.67) v10(13.8,11.69) v10(13.77,9.9) v10(13.86,42.4) v10(13.87,36.7) v10(13.96,45.46) v10(14,44.71) v10(14.08,46.02) v10(14.08,42.82) v10(14.06,36.31) v10(14.13,17.39) v10(14.13,16.78) v10(14.13,16.17) v10(14.13,15.56) v10(14.13,14.95) v10(14.13,14.34) v10(14.13,13.73) v10(14.13,13.12) v10(14.13,12.51) v10(14.19,3.59) v10(14.27,35.87) v10(14.35,45.03) v10(14.35,43.24) v10(14.45,35.45) v10(14.44,17.67) v10(14.52,16.77) v10(14.53,16.16) v10(14.53,15.55) v10(14.53,14.94) v10(14.53,14.33) v10(14.53,13.72) v10(14.53,13.12) v10(14.53,12.51) v10(14.62,35.04) v10(14.72,45.33) v10(14.71,43.69) v10(14.66,40.32) v10(14.67,39.82) v10(14.66,39.21) v10(14.66,38.7) v10(14.67,38.18) v10(14.71,34.36) v10(14.65,3.59) v10(14.73,41.52) v10(14.75,37.66) v10(14.77,33.83) v10(14.77,33.35) v10(14.73,22.85) v10(14.76,22.34) v10(14.85,34.71) v10(14.9,11.46) v10(14.94,42.04) v10(14.94,37.19) v10(15.03,34.14) v10(15,8.67) v10(14.98,5.84) v10(15.06,45.63) v10(15.08,44.07) v10(15.12,8.16) v10(15.12,7.01) v10(15.12,3.97) v10(15.17,42.41) v10(15.19,36.66) v10(15.16,33.36) v10(15.17,22.85) v10(15.2,22.35) v10(15.23,46.05) v10(15.28,11.46) v10(15.3,2.97) v10(15.3,2.61) v10(15.3,2.26) v10(15.3,1.88) v10(15.27,1.52) v10(15.27,1.14) v10(15.4,36.22) v10(15.48,44.43) v10(15.44,42.72) v10(15.51,6.4) v10(15.61,35.77) v10(15.56,17.2) v10(15.59,16.66) v10(15.63,16.1) v10(15.65,15.49) v10(15.65,14.88) v10(15.65,14.27) v10(15.65,13.66) v10(15.65,13.05) v10(15.65,12.44) v10(15.63,1.05) v10(15.84,44.75) v10(15.86,43.12) v10(15.84,35.27) v10(15.85,17.3) v10(16,34.81) v10(15.99,16.75) v10(16.03,16.28) v10(16.03,15.67) v10(15.99,3.59) v10(16.07,45.19) v10(16.12,34.31) v10(16.06,15.06) v10(16.06,14.45) v10(16.06,13.84) v10(16.06,13.23) v10(16.06,12.62) v10(16.18,43.5) v10(16.23,33.85) v10(16.23,22.34) v10(16.16,5.53) v10(16.27,45.6) v10(16.32,45.05) v10(16.24,41.84) v10(16.27,33.34) v10(16.23,22.86) v10(16.34,46.08) v10(16.42,11.69) v10(16.53,43.81) v10(16.44,9.91) v10(16.45,3.59) v10(16.57,39.81) v10(16.57,37.55) v10(16.66,45.4) v10(16.63,36.06) v10(16.64,7.53) v10(16.8,11.69) v10(16.82,9.91) v10(16.75,6.33) v10(16.85,42.37) v10(16.85,40.54) v10(16.89,33.51) v10(16.97,45.81) v10(16.95,44.15) v10(16.95,5.93) v10(17.13,39.73) v10(17.1,1.88) v10(17.07,1.52) v10(17.07,1.14) v10(17.22,46.3) v10(17.18,38.87) v10(17.35,44.53) v10(17.56,43.11) v10(17.6,35.84) v10(17.68,44.92) v10(17.64,36.86) v10(17.79,17.81) v10(17.79,16.92) v10(17.79,15.52) v10(17.79,14.76) v10(17.79,13.36) v10(17.79,12.6) v10(17.77,3.59) v10(17.92,45.3) v10(17.85,7.32) v10(18.01,44.04) v10(18.12,45.67) v10(18.13,6.98) v10(18.22,3.59) v10(18.3,46.07) v10(18.47,37.02) v10(18.45,35.59) v10(18.51,32.33) v10(18.64,34.3) v10(18.73,12.34) v10(18.86,15) v10(18.89,3.21) v10(18.89,2.93) v10(18.88,2.62) v10(18.91,2.26) v10(18.91,1.91) v10(18.9,1.55) v10(18.9,1.17) v10(19.06,18.44) v10(19.06,17.68) v10(19.2,35.84) v10(19.43,39.39) v10(19.36,15.34) v10(19.37,12) v10(19.57,18.7) v10(19.57,17.43) v10(19.57,16.79) v10(19.57,16.29) v10(19.57,15.78) v10(19.65,17.94) v10(20.18,18.75) v10(20.18,15.58) v11(1.46,38.47) v11(1.52,3.54) v11(1.48,3.26) v11(1.47,2.97) v11(1.47,2.59) v11(1.47,2.23) v11(1.47,1.88) v11(1.47,1.52) v11(1.47,1.17) v11(1.68,12.19) v11(1.66,10.06) v11(1.79,41.89) v11(1.76,23.55) v11(1.76,23.14) v11(1.83,1.03) v11(1.99,45.94) v11(2.09,9.67) v11(2.14,12.74) v11(2.19,3.59) v11(2.3,45.51) v11(2.33,44.72) v11(2.47,9.29) v11(2.65,45.18) v11(2.65,3.59) v11(2.89,8.86) v11(3.01,44.8) v11(3.22,46.15) v11(3.16,3.84) v11(3.31,3.57) v11(3.31,3.28) v11(3.31,3) v11(3.31,2.67) v11(3.31,2.32) v11(3.31,1.93) v11(3.31,1.58) v11(3.31,1.22) v11(3.41,44.42) v11(3.37,22.02) v11(3.41,14.71) v11(3.42,14.11) v11(3.41,13.52) v11(3.42,12.98) v11(3.41,12.43) v11(3.42,11.91) v11(3.52,16.33) v11(3.47,15.81) v11(3.44,15.27) v11(3.54,45.83) v11(3.58,16.86) v11(3.59,10.6) v11(3.64,17.36) v11(3.64,1.05) v11(3.83,44.01) v11(3.82,26.7) v11(3.74,21.04) v11(3.75,17.89) v11(3.82,10.19) v11(3.77,9.76) v11(3.89,45.47) v11(3.92,18.87) v11(3.86,18.37) v11(3.92,10.6) v11(3.86,6.74) v11(4.03,19.43) v11(3.99,3.59) v11(4.13,20.37) v11(4.1,19.89) v11(4.21,46.02) v11(4.21,22.89) v11(4.21,22.42) v11(4.18,21.52) v11(4.15,20.93) v11(4.2,10.19) v11(4.15,9.76) v11(4.17,5.79) v11(4.17,5) v11(4.28,45.08) v11(4.26,43.57) v11(4.33,27.59) v11(4.33,26.7) v11(4.28,10.6) v11(4.36,45.58) v11(4.48,28.11) v11(4.51,15.12) v11(4.49,14.56) v11(4.5,13.99) v11(4.48,13.41) v11(4.48,13) v11(4.48,12.6) v11(4.48,11.96) v11(4.45,3.59) v11(4.6,45.15) v11(4.58,39.27) v11(4.58,38.64) v11(4.58,38) v11(4.58,37.37) v11(4.58,36.73) v11(4.59,16.23) v11(4.53,15.63) v11(4.71,44.79) v11(4.63,43.2) v11(4.72,34.29) v11(4.66,33.84) v11(4.68,33.35) v11(4.71,27.21) v11(4.73,17.3) v11(4.64,16.78) v11(4.77,34.73) v11(4.87,35.2) v11(4.85,17.88) v11(4.93,15.02) v11(4.93,13.94) v11(4.98,35.69) v11(4.96,26.7) v11(5.02,17.55) v11(4.99,17.03) v11(4.96,16.52) v11(4.95,16) v11(4.94,14.46) v11(4.94,13.45) v11(4.96,13.05) v11(4.96,12.63) v11(4.96,11.92) v11(4.96,11.51) v11(4.96,11.04) v11(4.95,10.63) v11(4.96,10.11) v11(4.94,3.87) v11(5.13,44.38) v11(5.05,42.77) v11(5.09,40.67) v11(5.09,40.03) v11(5.09,38.64) v11(5.09,38) v11(5.09,37.37) v11(5.13,36.19) v11(5.12,18.72) v11(5.04,18.29) v11(5.08,8.89) v11(5.1,3.6) v11(5.1,3.31) v11(5.1,1.88) v11(5.1,1.52) v11(5.21,20.25) v11(5.2,19.22) v11(5.16,5.34) v11(5.29,36.68) v11(5.25,22.87) v11(5.24,22.33) v11(5.26,21.84) v11(5.26,21.35) v11(5.27,20.87) v11(5.24,19.67) v11(5.26,8.41) v11(5.29,7.98) v11(5.35,46.04) v11(5.35,27.59) v11(5.51,43.97) v11(5.44,42.33) v11(5.43,37.17) v11(5.51,20.47) v11(5.45,20.07) v11(5.44,8.89) v11(5.43,1.03) v11(5.61,45.59) v11(5.58,41.79) v11(5.6,41.26) v11(5.61,40.7) v11(5.6,40.07) v11(5.6,39.45) v11(5.6,38.85) v11(5.59,38.26) v11(5.56,37.71) v11(5.62,20.86) v11(5.69,22.87) v11(5.7,22.33) v11(5.7,21.88) v11(5.65,21.39) v11(5.72,8.41) v11(5.68,7.98) v11(5.82,34.42) v11(5.77,33.89) v11(5.77,33.36) v11(5.8,8.89) v11(5.79,3.59) v11(5.91,43.58) v11(5.91,34.94) v11(5.94,45.24) v11(6.02,16.35) v11(6.01,15.85) v11(6.01,15.31) v11(6.02,14.86) v11(6.01,14.41) v11(6.03,12.97) v11(6.02,12.48) v11(6,11.94) v11(6,11.49) v11(6,11.04) v11(6.01,10.63) v11(6.01,10.12) v11(6.04,35.46) v11(6.08,17.39) v11(6.04,16.88) v11(6.05,13.54) v11(6.2,35.94) v11(6.2,33.89) v11(6.18,33.37) v11(6.16,17.91) v11(6.31,43.14) v11(6.31,34.42) v11(6.26,18.5) v11(6.25,3.59) v11(6.34,46.09) v11(6.34,44.83) v11(6.39,36.49) v11(6.42,35) v11(6.41,19.28) v11(6.5,45.54) v11(6.44,18.83) v11(6.46,18.16) v11(6.45,17.6) v11(6.46,17.07) v11(6.46,16.51) v11(6.46,15.95) v11(6.46,15.39) v11(6.47,14.89) v11(6.44,14.43) v11(6.46,13.69) v11(6.48,13.2) v11(6.47,12.67) v11(6.48,12.08) v11(6.58,42.63) v11(6.59,36.94) v11(6.55,35.59) v11(6.59,19.74) v11(6.62,10.6) v11(6.66,44.5) v11(6.72,42.11) v11(6.72,41.51) v11(6.72,40.92) v11(6.72,40.36) v11(6.72,39.75) v11(6.72,39.12) v11(6.73,38.54) v11(6.73,37.95) v11(6.68,37.44) v11(6.64,36.13) v11(6.69,20.83) v11(6.73,20.29) v11(6.79,45.08) v11(6.73,36.63) v11(6.75,22.87) v11(6.74,22.36) v11(6.75,21.81) v11(6.74,21.37) v11(6.82,9.76) v11(6.75,3.84) v11(6.87,10.19) v11(6.9,3.57) v11(6.9,3.28) v11(6.9,2.99) v11(6.9,2.61) v11(6.9,2.26) v11(6.9,1.9) v11(6.9,1.55) v11(6.9,1.19) v11(7.01,44.11) v11(6.97,10.6) v11(7.1,44.7) v11(7.05,21.06) v11(7.2,22.87) v11(7.21,22.34) v11(7.17,21.64) v11(7.2,9.76) v11(7.23,1.03) v11(7.3,43.74) v11(7.31,33.91) v11(7.27,33.34) v11(7.33,10.6) v11(7.25,10.19) v11(7.43,44.24) v11(7.4,34.37) v11(7.33,5.53) v11(7.46,46.14) v11(7.51,34.91) v11(7.53,12.47) v11(7.53,12.06) v11(7.57,43.26) v11(7.62,19.3) v11(7.55,18.81) v11(7.54,18.26) v11(7.54,17.71) v11(7.54,17.15) v11(7.54,16.59) v11(7.54,16.03) v11(7.54,15.47) v11(7.54,14.89) v11(7.54,14.37) v11(7.53,13.86) v11(7.54,13.37) v11(7.54,12.94) v11(7.6,6.13) v11(7.59,3.59) v11(7.72,45.69) v11(7.64,35.46) v11(7.7,34.01) v11(7.69,33.35) v11(7.75,43.75) v11(7.8,36.21) v11(7.83,35.77) v11(7.78,35.15) v11(7.75,34.59) v11(7.75,19.8) v11(7.9,43.26) v11(7.84,42.72) v11(7.89,42.24) v11(7.87,41.66) v11(7.88,41.04) v11(7.88,40.44) v11(7.88,39.83) v11(7.88,39.22) v11(7.87,38.7) v11(7.87,38.16) v11(7.87,37.7) v11(7.89,37.18) v11(7.87,36.69) v11(7.93,13.39) v11(7.93,12.96) v11(7.94,20.3) v11(8.02,19.34) v11(8,18.79) v11(7.98,18.27) v11(7.98,17.71) v11(7.98,17.15) v11(7.98,16.59) v11(7.98,16.03) v11(7.98,15.48) v11(8,14.91) v11(7.96,14.33) v11(7.96,13.82) v11(8,12.48) v11(8,12.05) v11(7.96,11.69) v11(8,11.05) v11(8,10.61) v11(8,10.09) v11(8.04,45.28) v11(8.13,20.9) v11(8.11,19.84) v11(8.05,3.59) v11(8.16,8.9) v11(8.25,22.86) v11(8.24,22.36) v11(8.25,21.86) v11(8.25,21.5) v11(8.29,20.4) v11(8.31,8.41) v11(8.35,44.85) v11(8.34,7.98) v11(8.52,20.96) v11(8.51,8.9) v11(8.57,46.02) v11(8.62,45.51) v11(8.65,44.38) v11(8.71,22.86) v11(8.7,22.35) v11(8.71,21.86) v11(8.65,21.47) v11(8.72,7.98) v11(8.67,3.46) v11(8.7,1.9) v11(8.7,1.55) v11(8.7,1.19) v11(8.77,45) v11(8.82,34.08) v11(8.77,33.36) v11(8.77,8.41) v11(8.76,7.32) v11(8.91,35.62) v11(8.89,35.1) v11(8.85,34.64) v11(8.87,8.9) v11(8.85,6.56) v11(8.95,44.53) v11(8.94,44.09) v11(9,43.64) v11(9.03,42.68) v11(9.03,42.12) v11(9.03,41.53) v11(9.03,40.9) v11(9.03,40.29) v11(9.04,43.16) v11(9.04,39.59) v11(9.04,38.99) v11(9.04,38.38) v11(9.05,37.77) v11(9.05,37.19) v11(9.08,36.61) v11(9.04,36.04) v11(9.1,19.35) v11(9.05,18.82) v11(9.06,18.27) v11(9.06,17.71) v11(9.06,17.15) v11(9.06,16.59) v11(9.06,16.03) v11(9.06,15.48) v11(9.06,14.87) v11(9.08,14.25) v11(9.05,13.69) v11(9.06,13.17) v11(9.07,12.63) v11(9.06,12.11) v11(9.13,11.71) v11(9.06,11.05) v11(9.07,10.57) v11(9.07,10.11) v11(9.14,35.34) v11(9.15,34.85) v11(9.16,34.41) v11(9.17,33.9) v11(9.18,33.37) v11(9.24,19.88) v11(9.28,2.9) v11(9.28,2.52) v11(9.28,2.14) v11(9.28,1.76) v11(9.28,1.38) v11(9.28,0.99) v11(9.42,20.36) v11(9.66,46.03) v11(9.7,21.36) v11(9.64,20.9) v11(9.66,19.08) v11(9.66,17.94) v11(9.66,6.51) v11(9.74,45.53) v11(9.74,22.85) v11(9.76,22.36) v11(9.76,21.86) v11(9.79,13.36) v11(9.79,12.86) v11(9.79,7.65) v11(9.79,5.49) v11(9.92,45.08) v11(10.08,44.61) v11(10.04,18.19) v11(10.04,17.05) v11(10.14,44.07) v11(10.2,43.57) v11(10.16,43.03) v11(10.16,42.5) v11(10.2,41.84) v11(10.17,41.15) v11(10.17,40.59) v11(10.17,39.96) v11(10.17,39.35) v11(10.17,38.71) v11(10.17,38.08) v11(10.2,37.44) v11(10.22,36.78) v11(10.21,22.85) v11(10.21,22.37) v11(10.32,36.28) v11(10.25,35.81) v11(10.25,35.3) v11(10.26,34.86) v11(10.26,34.38) v11(10.27,33.9) v11(10.26,33.36) v11(10.3,13.36) v11(10.3,12.86) v11(10.38,44.34) v11(10.53,35.53) v11(10.58,44.85) v11(10.6,35.05) v11(10.73,45.41) v11(10.64,34.51) v11(10.67,33.94) v11(10.69,33.36) v11(10.7,22.86) v11(10.7,22.35) v11(10.72,21.82) v11(10.68,17.94) v11(10.8,45.98) v11(10.76,21.34) v11(10.81,18.7) v11(10.81,13.36) v11(10.81,12.86) v11(10.81,7.27) v11(10.81,6.25) v11(10.81,5.11) v11(10.96,20.78) v11(11.19,2.14) v11(11.19,1.76) v11(11.19,1.38) v11(11.19,0.99) v11(11.31,43.48) v11(11.29,42.93) v11(11.31,41.96) v11(11.31,41.46) v11(11.32,40.92) v11(11.31,40.39) v11(11.31,39.86) v11(11.31,39.35) v11(11.31,38.79) v11(11.31,38.28) v11(11.31,37.79) v11(11.24,20.25) v11(11.39,42.5) v11(11.35,37.3) v11(11.37,19.82) v11(11.44,44.05) v11(11.44,36.81) v11(11.49,19.31) v11(11.51,18.74) v11(11.51,18.18) v11(11.51,17.62) v11(11.51,17.06) v11(11.51,16.5) v11(11.52,15.94) v11(11.51,15.46) v11(11.51,14.97) v11(11.51,14.36) v11(11.51,13.75) v11(11.51,13.14) v11(11.51,12.53) v11(11.51,11.92) v11(11.62,44.54) v11(11.55,43.15) v11(11.54,36.3) v11(11.6,35.83) v11(11.67,35.28) v11(11.73,34.76) v11(11.67,10.6) v11(11.7,1.9) v11(11.67,1.55) v11(11.67,1.17) v11(11.76,45.01) v11(11.77,43.62) v11(11.77,34.28) v11(11.77,33.85) v11(11.78,33.35) v11(11.75,22.83) v11(11.77,22.38) v11(11.82,10.19) v11(11.78,3.5) v11(11.89,46.01) v11(11.86,45.52) v11(11.89,35.59) v11(11.85,21.67) v11(11.87,9.76) v11(12.03,35.1) v11(12,21.14) v11(12.03,10.6) v11(12.03,44.05) v11(12.11,34.62) v11(12.03,1.03) v11(12.17,34.08) v11(12.18,33.36) v11(12.22,22.82) v11(12.18,22.38) v11(12.23,21.85) v11(12.23,20.68) v11(12.24,21.5) v11(12.33,10.19) v11(12.25,9.76) v11(12.35,44.49) v11(12.42,40.63) v11(12.43,39.48) v11(12.42,38.91) v11(12.42,38.28) v11(12.34,21.07) v11(12.42,20.16) v11(12.38,10.6) v11(12.39,3.59) v11(12.48,41.84) v11(12.43,41.23) v11(12.43,40.06) v11(12.45,37.74) v11(12.52,37.24) v11(12.52,20.5) v11(12.51,19.65) v11(12.61,45.02) v11(12.58,42.37) v11(12.56,19.19) v11(12.57,18.74) v11(12.57,18.18) v11(12.57,17.62) v11(12.57,17.06) v11(12.57,16.5) v11(12.56,15.94) v11(12.56,15.46) v11(12.58,14.97) v11(12.58,14.36) v11(12.58,13.75) v11(12.58,13.14) v11(12.58,12.53) v11(12.58,12.12) v11(12.65,36.78) v11(12.71,19.95) v11(12.81,45.5) v11(12.77,42.91) v11(12.81,36.3) v11(12.83,19.45) v11(12.91,18.98) v11(12.85,3.59) v11(12.95,46.01) v11(12.97,35.86) v11(13.01,18.37) v11(13.03,17.76) v11(13.03,17.15) v11(13.03,16.55) v11(13.03,15.94) v11(13.03,15.33) v11(13.03,14.72) v11(13.03,14.11) v11(13.03,13.5) v11(13.03,12.89) v11(13.02,10.6) v11(13.03,10.09) v11(13.03,43.41) v11(13.11,35.46) v11(13.04,12.53) v11(13.05,12.14) v11(13.04,11.67) v11(13.03,11.06) v11(13.09,5.83) v11(13.17,34.98) v11(13.21,8.91) v11(13.14,5.26) v11(13.15,4.68) v11(13.32,43.88) v11(13.33,35.24) v11(13.24,34.52) v11(13.28,34.2) v11(13.26,33.83) v11(13.27,33.35) v11(13.29,22.88) v11(13.28,22.37) v11(13.32,21.66) v11(13.35,8.41) v11(13.38,7.98) v11(13.35,3.85) v11(13.51,34.81) v11(13.47,23.17) v11(13.51,3.59) v11(13.5,3.3) v11(13.5,2.99) v11(13.5,2.64) v11(13.5,2.28) v11(13.5,1.9) v11(13.47,1.55) v11(13.47,1.17) v11(13.59,41.37) v11(13.56,40.85) v11(13.56,40.33) v11(13.55,39.79) v11(13.57,39.28) v11(13.55,38.7) v11(13.57,38.18) v11(13.6,34.39) v11(13.6,20.97) v11(13.57,8.91) v11(13.64,44.32) v11(13.68,41.88) v11(13.64,37.6) v11(13.73,37.17) v11(13.65,33.89) v11(13.69,33.35) v11(13.69,22.88) v11(13.71,22.36) v11(13.7,21.77) v11(13.7,21.37) v11(13.73,20.4) v11(13.76,44.86) v11(13.8,8.41) v11(13.76,7.98) v11(13.79,5.24) v11(13.86,42.4) v11(13.87,36.7) v11(13.88,19.82) v11(13.93,8.91) v11(13.83,1.03) v11(13.96,45.46) v11(14,44.71) v11(14.01,19.21) v11(14.08,46.02) v11(14.08,42.82) v11(14.06,36.31) v11(14.08,18.6) v11(14.13,18) v11(14.13,17.39) v11(14.13,16.78) v11(14.13,16.17) v11(14.13,15.56) v11(14.13,14.95) v11(14.13,14.34) v11(14.13,13.73) v11(14.13,13.12) v11(14.13,12.51) v11(14.1,11.65) v11(14.08,11.23) v11(14.08,10.79) v11(14.08,10.33) v11(14.13,12.09) v11(14.18,4.07) v11(14.19,3.59) v11(14.27,35.87) v11(14.29,18.29) v11(14.35,45.03) v11(14.35,43.24) v11(14.41,17.71) v11(14.45,35.45) v11(14.49,17.17) v11(14.52,16.77) v11(14.53,16.16) v11(14.53,15.55) v11(14.53,14.94) v11(14.53,14.33) v11(14.53,13.72) v11(14.53,13.12) v11(14.53,12.51) v11(14.52,6.25) v11(14.62,35.04) v11(14.54,12.09) v11(14.57,4.07) v11(14.72,45.33) v11(14.71,43.69) v11(14.66,40.32) v11(14.67,39.82) v11(14.66,39.21) v11(14.66,38.7) v11(14.67,38.18) v11(14.71,34.36) v11(14.69,10.34) v11(14.65,3.59) v11(14.73,41.52) v11(14.75,37.66) v11(14.77,33.83) v11(14.77,33.35) v11(14.73,22.85) v11(14.76,22.34) v11(14.79,21.53) v11(14.85,34.71) v11(14.84,20.9) v11(14.87,9.94) v11(14.9,9.5) v11(14.94,42.04) v11(14.94,37.19) v11(15.03,34.14) v11(14.97,20.3) v11(15.06,45.63) v11(15.08,44.07) v11(15.09,19.61) v11(15.05,10.34) v11(15.12,9.17) v11(15.17,42.41) v11(15.19,36.66) v11(15.16,33.36) v11(15.17,22.85) v11(15.2,22.35) v11(15.2,21.77) v11(15.22,21.26) v11(15.21,20.7) v11(15.21,20.02) v11(15.23,19.13) v11(15.16,3.84) v11(15.23,46.05) v11(15.33,18.67) v11(15.33,9.93) v11(15.28,9.5) v11(15.31,3.55) v11(15.31,3.26) v11(15.3,2.97) v11(15.3,2.61) v11(15.3,2.26) v11(15.3,1.88) v11(15.27,1.52) v11(15.27,1.14) v11(15.36,40.48) v11(15.4,36.22) v11(15.4,10.34) v11(15.48,44.43) v11(15.44,42.72) v11(15.45,18.21) v11(15.52,17.75) v11(15.61,35.77) v11(15.56,17.2) v11(15.59,16.66) v11(15.63,16.1) v11(15.63,1.03) v11(15.65,15.49) v11(15.65,14.88) v11(15.65,14.27) v11(15.65,13.66) v11(15.65,13.05) v11(15.65,12.44) v11(15.68,12.07) v11(15.84,44.75) v11(15.86,43.12) v11(15.84,35.27) v11(15.85,17.3) v11(16,34.81) v11(15.99,16.75) v11(16.03,16.28) v11(16.03,15.67) v11(15.99,3.59) v11(16.07,45.19) v11(16.12,34.31) v11(16.06,15.06) v11(16.06,14.45) v11(16.06,13.84) v11(16.06,13.23) v11(16.06,12.62) v11(16.06,12.09) v11(16.04,11.71) v11(16.08,11.29) v11(16.1,10.81) v11(16.09,10.33) v11(16.04,4.07) v11(16.18,43.5) v11(16.23,33.85) v11(16.23,22.34) v11(16.14,4.47) v11(16.27,45.6) v11(16.32,45.05) v11(16.27,33.34) v11(16.23,22.86) v11(16.25,21.77) v11(16.26,21.22) v11(16.26,20.71) v11(16.26,20.14) v11(16.3,19.58) v11(16.28,8.92) v11(16.34,46.08) v11(16.42,40.21) v11(16.39,19) v11(16.39,8.41) v11(16.43,7.98) v11(16.42,4.07) v11(16.39,1.05) v11(16.53,43.81) v11(16.45,3.59) v11(16.57,18.44) v11(16.66,45.4) v11(16.64,8.92) v11(16.8,17.91) v11(16.81,7.98) v11(16.75,6.33) v11(16.85,8.41) v11(16.97,45.81) v11(16.95,44.15) v11(16.99,41.87) v11(16.94,41.22) v11(16.98,17.35) v11(16.99,8.92) v11(16.95,5.93) v11(16.94,3.86) v11(17.11,36.09) v11(17.11,16.77) v11(17.09,3.56) v11(17.09,3.27) v11(17.1,1.88) v11(17.07,1.52) v11(17.07,1.14) v11(17.22,46.3) v11(17.16,35.34) v11(17.16,34.7) v11(17.16,34.07) v11(17.16,16.16) v11(17.15,15.56) v11(17.15,14.95) v11(17.15,14.34) v11(17.15,13.73) v11(17.15,13.12) v11(17.15,12.51) v11(17.16,12.07) v11(17.18,11.71) v11(17.14,11.09) v11(17.15,10.65) v11(17.15,10.09) v11(17.35,44.53) v11(17.36,18.89) v11(17.41,17.94) v11(17.45,41.55) v11(17.5,38.93) v11(17.43,1.03) v11(17.68,44.92) v11(17.77,31.98) v11(17.77,3.59) v11(17.92,45.3) v11(17.92,10.19) v11(17.84,4.07) v11(18.01,44.04) v11(18.12,45.67) v11(18.05,11.46) v11(18.13,6.98) v11(18.22,4.07) v11(18.22,3.59) v11(18.3,46.07) v11(18.25,31.98) v11(18.35,40.01) v11(18.42,31.37) v11(18.43,9.55) v11(18.47,37.02) v11(18.8,3.78) v11(18.84,39.2) v11(18.88,18.9) v11(18.84,3.49) v11(18.89,3.21) v11(18.89,2.93) v11(18.88,2.62) v11(18.91,2.26) v11(18.91,1.91) v11(18.9,1.55) v11(18.9,1.17) v11(18.93,9.68) v11(19.43,39.39) v11(19.6,34.26) v11(19.57,16.79) v11(19.57,15.78) v11(19.64,30.5) v11(19.65,17.94) v11(19.77,32.89) v11(20.19,29.97) v11(20.18,18.38) v12(0.51,36.63) v12(0.51,35.49) v12(0.51,34.55) v12(0.51,33.87) v12(0.51,33.23) v12(0.51,32.53) v12(0.51,31.81) v12(1.15,33.68) v12(1.15,32.8) v12(1.66,36.86) v12(1.66,30.51) v12(1.66,18.5) v12(1.66,18.19) v12(1.66,17.89) v12(1.79,33.68) v12(1.79,32.8) v12(1.79,32.29) v12(1.79,31.27) v12(1.79,17.42) v12(1.79,17.11) v12(1.79,16.81) v12(1.82,3.23) v12(1.8,2.94) v12(1.8,2.56) v12(1.8,2.21) v12(1.8,1.85) v12(1.8,1.5) v12(1.8,1.11) v12(1.92,34.32) v12(1.85,3.51) v12(1.96,18.5) v12(1.96,18.19) v12(1.96,17.89) v12(2.04,41.94) v12(2.04,41.3) v12(2.04,40.16) v12(2.09,35.79) v12(2.1,17.42) v12(2.1,17.11) v12(2.1,16.81) v12(2.25,42.82) v12(2.3,42.4) v12(2.27,18.5) v12(2.27,18.19) v12(2.27,17.89) v12(2.42,31.27) v12(2.4,17.42) v12(2.4,17.11) v12(2.4,16.81) v12(2.49,3.61) v12(2.55,35.08) v12(2.55,34.32) v12(2.55,33.68) v12(2.55,32.8) v12(2.65,42.4) v12(2.68,41.3) v12(2.68,40.16) v12(2.68,39.53) v12(2.68,38.89) v12(2.68,36.73) v12(2.74,42.82) v12(2.78,6.38) v12(2.81,5.62) v12(2.92,3.61) v12(2.93,18.83) v12(2.93,18.32) v12(2.93,17.68) v12(2.99,14.02) v12(2.99,13.51) v12(2.99,13) v12(3.06,32.03) v12(3.06,30.51) v12(3.06,16.16) v12(3.06,15.27) v12(3.19,35.08) v12(3.19,33.68) v12(3.19,32.8) v12(3.19,31.27) v12(3.22,1.03) v12(3.31,36.73) v12(3.31,34.32) v12(3.41,13.48) v12(3.43,13.01) v12(3.42,12.53) v12(3.44,39.53) v12(3.44,18.83) v12(3.53,16.34) v12(3.47,15.74) v12(3.44,15.13) v12(3.43,14.02) v12(3.61,16.94) v12(3.57,10.62) v12(3.57,8.41) v12(3.57,7.52) v12(3.59,3.62) v12(3.59,3.33) v12(3.6,2.99) v12(3.6,2.61) v12(3.6,2.26) v12(3.6,1.9) v12(3.6,1.55) v12(3.59,1.17) v12(3.67,43.58) v12(3.69,30.51) v12(3.71,17.55) v12(3.72,10.18) v12(3.69,6.89) v12(3.82,40.92) v12(3.82,31.27) v12(3.83,18.15) v12(3.77,9.76) v12(3.92,10.62) v12(3.96,45.87) v12(3.95,36.73) v12(3.95,35.08) v12(3.95,34.32) v12(3.94,18.75) v12(4.1,43.72) v12(4.13,9.76) v12(4.2,39.4) v12(4.2,38.76) v12(4.2,38.13) v12(4.21,10.18) v12(4.27,45.87) v12(4.32,42.4) v12(4.33,33.96) v12(4.28,10.62) v12(4.33,7.9) v12(4.33,6.89) v12(4.29,3.61) v12(4.47,41.95) v12(4.52,41.54) v12(4.46,30.51) v12(4.48,23.11) v12(4.48,13.28) v12(4.49,12.63) v12(4.49,11.88) v12(4.57,45.87) v12(4.58,35.08) v12(4.6,16.47) v12(4.55,15.91) v12(4.68,42.4) v12(4.71,40.67) v12(4.72,40.02) v12(4.71,36.73) v12(4.69,34.4) v12(4.65,34.08) v12(4.65,16.94) v12(4.71,6.25) v12(4.72,3.61) v12(4.74,17.44) v12(4.88,45.87) v12(4.88,41.54) v12(4.84,38.76) v12(4.84,38.13) v12(4.87,18.04) v12(5.03,42.4) v12(4.97,41.95) v12(4.96,39.16) v12(4.98,33.11) v12(4.98,23.11) v12(4.97,18.64) v12(4.99,17.1) v12(4.95,16.53) v12(4.95,15.93) v12(4.96,13.23) v12(4.95,12.66) v12(4.97,11.92) v12(4.96,11.51) v12(4.96,11.04) v12(4.96,10.61) v12(4.96,10.11) v12(5.01,1.03) v12(5.07,34.17) v12(5.09,30.51) v12(5.1,18.31) v12(5.04,17.71) v12(5.09,8.84) v12(5.09,5.62) v12(5.18,45.87) v12(5.14,40.95) v12(5.18,36.01) v12(5.2,18.91) v12(5.33,43.72) v12(5.24,8.4) v12(5.29,7.98) v12(5.35,36.73) v12(5.42,34.17) v12(5.4,3.31) v12(5.4,1.9) v12(5.4,1.55) v12(5.4,1.17) v12(5.49,45.87) v12(5.47,35.08) v12(5.48,33.11) v12(5.45,8.84) v12(5.52,7.35) v12(5.6,40.03) v12(5.6,39.4) v12(5.6,38.76) v12(5.65,7.98) v12(5.75,43.58) v12(5.76,36) v12(5.78,34.4) v12(5.8,8.84) v12(5.74,8.4) v12(5.84,34.05) v12(5.98,36.73) v12(5.98,23.11) v12(6.01,16.61) v12(6.01,16.01) v12(6.01,15.4) v12(6.01,14.79) v12(6.01,13.57) v12(6.01,12.96) v12(6.01,12.35) v12(6.01,11.74) v12(6,11.05) v12(6.01,10.61) v12(6.01,10.14) v12(6.11,35.08) v12(6.1,17.83) v12(6.05,17.22) v12(6.11,4.98) v12(6.09,3.61) v12(6.18,34.4) v12(6.14,34.07) v12(6.17,18.43) v12(6.23,40.03) v12(6.23,39.4) v12(6.23,38.76) v12(6.23,5.49) v12(6.41,41.33) v12(6.4,36) v12(6.48,33.11) v12(6.48,23.11) v12(6.49,18.67) v12(6.49,18.02) v12(6.49,17.42) v12(6.49,16.81) v12(6.49,16.2) v12(6.49,15.59) v12(6.49,14.98) v12(6.49,14.37) v12(6.46,13.64) v12(6.49,13.15) v12(6.49,12.54) v12(6.49,11.93) v12(6.52,3.61) v12(6.54,43.27) v12(6.54,34.17) v12(6.62,10.62) v12(6.69,40.57) v12(6.75,42.4) v12(6.74,38.13) v12(6.74,37.62) v12(6.74,37.11) v12(6.74,36.73) v12(6.77,10.18) v12(6.82,9.76) v12(6.82,1.03) v12(6.9,43.27) v12(6.87,40.03) v12(6.87,39.4) v12(6.87,38.76) v12(6.87,35.08) v12(6.9,34.17) v12(6.98,33.11) v12(6.97,10.62) v12(7,9.17) v12(7,8.03) v12(7,7.01) v12(7,4.6) v12(7.1,42.4) v12(7.03,36) v12(7.17,9.76) v12(7.2,3.56) v12(7.2,3.28) v12(7.2,2.97) v12(7.2,2.59) v12(7.2,2.23) v12(7.2,1.88) v12(7.2,1.52) v12(7.2,1.14) v12(7.26,43.27) v12(7.28,34.45) v12(7.3,34.07) v12(7.33,10.62) v12(7.26,10.18) v12(7.38,36.73) v12(7.5,40.03) v12(7.5,39.4) v12(7.5,38.76) v12(7.5,35.08) v12(7.48,23.11) v12(7.53,18.63) v12(7.52,18.02) v12(7.52,17.41) v12(7.52,16.8) v12(7.52,16.19) v12(7.52,15.58) v12(7.52,14.97) v12(7.52,14.37) v12(7.52,13.76) v12(7.52,13.15) v12(7.52,12.54) v12(7.52,11.93) v12(7.67,36) v12(7.68,34.45) v12(7.65,34.08) v12(7.89,3.61) v12(8.01,36.73) v12(7.98,33.11) v12(7.98,23.11) v12(8.01,18.17) v12(8.01,17.57) v12(8.01,16.96) v12(8.01,16.35) v12(8.01,15.74) v12(8.01,15.13) v12(8.01,14.52) v12(8.01,13.91) v12(8.01,13.3) v12(8.01,12.69) v12(8.01,12.08) v12(8.01,11.06) v12(8.01,10.6) v12(8,10.1) v12(8.12,43.58) v12(8.11,41.51) v12(8.04,34.17) v12(8.17,40.62) v12(8.14,40.03) v12(8.14,39.4) v12(8.14,38.76) v12(8.14,8.84) v12(8.27,38.13) v12(8.27,37.62) v12(8.27,37.11) v12(8.3,36) v12(8.27,35.08) v12(8.29,8.4) v12(8.32,3.61) v12(8.42,45.87) v12(8.39,34.17) v12(8.34,7.98) v12(8.39,4.35) v12(8.48,33.11) v12(8.5,8.84) v12(8.52,8.54) v12(8.52,7.52) v12(8.52,6.38) v12(8.54,43.73) v12(8.72,45.87) v12(8.7,7.98) v12(8.64,1.03) v12(8.77,42.4) v12(8.77,40.03) v12(8.77,39.4) v12(8.77,38.76) v12(8.77,36.73) v12(8.77,34.42) v12(8.82,34.06) v12(8.79,8.4) v12(8.92,41.95) v12(8.9,35.08) v12(8.85,8.84) v12(8.92,3.49) v12(9.03,45.87) v12(8.97,41.54) v12(8.94,36) v12(8.98,23.11) v12(8.97,3.24) v12(9,1.9) v12(9,1.55) v12(9,1.17) v12(9.13,42.4) v12(9.05,18.18) v12(9.05,17.57) v12(9.05,16.96) v12(9.05,16.35) v12(9.05,15.74) v12(9.06,15.13) v12(9.05,14.56) v12(9.05,13.91) v12(9.05,13.3) v12(9.05,12.69) v12(9.05,10.6) v12(9.05,10.1) v12(9.18,34.42) v12(9.14,34.08) v12(9.33,41.54) v12(9.33,45.87) v12(9.42,41.95) v12(9.41,40.03) v12(9.41,39.4) v12(9.41,38.76) v12(9.41,36.73) v12(9.41,12.98) v12(9.48,42.4) v12(9.48,33.11) v12(9.48,23.11) v12(9.57,36) v12(9.54,34.17) v12(9.54,17.68) v12(9.54,17.05) v12(9.54,16.41) v12(9.54,15.65) v12(9.64,45.87) v12(9.71,40.57) v12(9.66,38.13) v12(9.66,37.62) v12(9.66,37.11) v12(9.66,35.08) v12(9.66,13.36) v12(9.78,43.73) v12(9.89,34.17) v12(9.92,12.98) v12(9.94,45.87) v12(9.98,33.11) v12(10.04,40.03) v12(10.04,39.4) v12(10.04,38.76) v12(10.04,36.73) v12(10.04,15.52) v12(10.2,43.58) v12(10.21,36) v12(10.17,17.68) v12(10.17,16.29) v12(10.3,35.08) v12(10.27,34.4) v12(10.33,34.05) v12(10.3,16.92) v12(10.3,13.36) v12(10.43,18.57) v12(10.55,12.98) v12(10.68,34.4) v12(10.63,34.07) v12(10.81,40.03) v12(10.81,39.4) v12(10.81,38.76) v12(10.81,36.73) v12(10.81,13.36) v12(10.85,35.98) v12(11,43.27) v12(10.98,33.11) v12(10.98,23.11) v12(11.06,35.08) v12(11.04,34.17) v12(11.06,17.43) v12(11.06,16.67) v12(11.06,15.9) v12(11.06,12.98) v12(11.2,42.4) v12(11.19,38.13) v12(11.19,37.62) v12(11.19,37.11) v12(11.24,40.64) v12(11.35,43.27) v12(11.39,34.17) v12(11.44,40.03) v12(11.44,39.4) v12(11.44,38.76) v12(11.44,36.73) v12(11.48,35.98) v12(11.48,33.11) v12(11.48,23.11) v12(11.52,18.5) v12(11.52,17.89) v12(11.52,17.28) v12(11.52,16.67) v12(11.52,16.06) v12(11.52,15.45) v12(11.52,14.84) v12(11.52,14.23) v12(11.52,13.62) v12(11.52,13.01) v12(11.55,42.4) v12(11.71,43.27) v12(11.7,35.08) v12(11.67,10.62) v12(11.8,34.45) v12(11.82,34.06) v12(11.8,10.18) v12(11.87,9.76) v12(12.03,10.62) v12(12.03,3.23) v12(12,1.95) v12(12,1.6) v12(12,1.22) v12(12.08,36.73) v12(12.12,35.98) v12(12.08,9.17) v12(12.08,8.03) v12(12.08,6.89) v12(12.08,5.62) v12(12.06,3.51) v12(12.2,40.03) v12(12.2,39.4) v12(12.2,38.76) v12(12.15,34.45) v12(12.15,34.08) v12(12.23,9.76) v12(12.3,10.18) v12(12.38,10.62) v12(12.46,35.08) v12(12.48,33.11) v12(12.48,23.11) v12(12.57,43.58) v12(12.56,34.19) v12(12.56,18.5) v12(12.56,17.89) v12(12.56,17.28) v12(12.56,16.67) v12(12.56,16.06) v12(12.56,15.45) v12(12.56,14.84) v12(12.56,14.23) v12(12.56,13.62) v12(12.56,13.01) v12(12.56,12.46) v12(12.57,11.93) v12(12.71,38.13) v12(12.71,37.62) v12(12.71,37.11) v12(12.69,3.61) v12(12.75,35.98) v12(12.86,45.87) v12(12.89,40.69) v12(12.84,40.03) v12(12.84,39.4) v12(12.84,38.76) v12(12.84,36.73) v12(12.91,34.19) v12(12.99,43.73) v12(12.98,33.11) v12(12.98,23.11) v12(13.09,35.08) v12(13.05,18.09) v12(13.05,17.48) v12(13.05,16.87) v12(13.05,16.26) v12(13.05,15.71) v12(13.05,15.04) v12(13.05,14.43) v12(13.05,13.82) v12(13.05,13.21) v12(13.05,12.6) v12(13.05,12.12) v12(13.04,11.64) v12(13.04,11.05) v12(13.04,10.58) v12(13.04,10.14) v12(13.12,3.61) v12(13.16,45.87) v12(13.22,42.4) v12(13.18,8.84) v12(13.27,34.42) v12(13.31,34.06) v12(13.33,8.4) v12(13.37,41.95) v12(13.42,41.54) v12(13.39,35.98) v12(13.38,7.98) v12(13.42,1.03) v12(13.47,45.87) v12(13.47,36.73) v12(13.53,8.84) v12(13.58,42.4) v12(13.6,40.03) v12(13.6,39.4) v12(13.6,38.76) v12(13.63,34.08) v12(13.6,4.98) v12(13.68,34.42) v12(13.77,45.87) v12(13.78,41.54) v12(13.82,8.4) v12(13.73,7.98) v12(13.8,3.56) v12(13.81,3.27) v12(13.8,2.97) v12(13.8,2.61) v12(13.8,2.26) v12(13.8,1.9) v12(13.8,1.55) v12(13.8,1.17) v12(13.93,42.4) v12(13.87,41.95) v12(13.85,35.08) v12(13.89,8.84) v12(13.89,6.67) v12(14.02,35.98) v12(13.98,33.11) v12(13.98,23.11) v12(14.08,45.87) v12(14.11,36.73) v12(14.06,34.19) v12(14.09,18.7) v12(14.08,18.09) v12(14.08,17.48) v12(14.08,16.87) v12(14.08,16.26) v12(14.08,15.65) v12(14.08,15.06) v12(14.08,14.43) v12(14.08,13.83) v12(14.08,13.22) v12(14.08,12.61) v12(14.09,12.12) v12(14.08,11.64) v12(14.08,11.25) v12(14.08,10.77) v12(14.08,10.33) v12(14.23,43.73) v12(14.24,40.67) v12(14.24,40.03) v12(14.24,39.4) v12(14.24,38.76) v12(14.24,38.13) v12(14.24,37.62) v12(14.24,37.11) v12(14.38,45.87) v12(14.41,34.19) v12(14.51,41.65) v12(14.49,35.08) v12(14.48,33.11) v12(14.48,23.11) v12(14.44,5.47) v12(14.49,3.61) v12(14.57,18.32) v12(14.57,17.71) v12(14.57,17.1) v12(14.57,16.49) v12(14.55,15.88) v12(14.55,15.27) v12(14.57,14.66) v12(14.57,14.05) v12(14.57,13.44) v12(14.57,12.83) v12(14.57,12.28) v12(14.57,11.73) v12(14.65,43.58) v12(14.66,35.98) v12(14.79,34.42) v12(14.74,10.37) v12(14.84,34.05) v12(14.85,9.92) v12(14.9,9.48) v12(14.92,3.61) v12(15.1,10.37) v12(15.12,9.05) v12(15.12,7.65) v12(15.15,34.42) v12(15.16,34.08) v12(15.21,1.02) v12(15.29,35.98) v12(15.25,35.08) v12(15.25,9.48) v12(15.35,9.92) v12(15.45,43.27) v12(15.48,33.11) v12(15.48,23.11) v12(15.45,10.37) v12(15.56,34.22) v12(15.61,18.93) v12(15.61,18.32) v12(15.61,17.71) v12(15.61,17.1) v12(15.61,16.49) v12(15.62,15.86) v12(15.62,15.25) v12(15.62,14.64) v12(15.62,14.03) v12(15.61,13.44) v12(15.62,12.83) v12(15.61,12.28) v12(15.61,11.75) v12(15.61,3.26) v12(15.6,2.97) v12(15.6,2.61) v12(15.6,2.26) v12(15.6,1.9) v12(15.6,1.55) v12(15.6,1.17) v12(15.8,43.27) v12(15.82,5.7) v12(15.89,36.1) v12(15.89,35.59) v12(15.89,35.08) v12(15.91,34.19) v12(15.92,14.23) v12(15.89,13.78) v12(15.98,33.11) v12(15.98,23.11) v12(16.09,18.93) v12(16.09,18.32) v12(16.09,17.71) v12(16.09,17.1) v12(16.09,16.49) v12(16.08,15.85) v12(16.08,15.24) v12(16.08,14.63) v12(16.09,14) v12(16.08,13.43) v12(16.08,12.81) v12(16.09,12.22) v12(16.08,11.64) v12(16.1,11.27) v12(16.1,10.81) v12(16.09,10.32) v12(16.16,43.27) v12(16.22,8.84) v12(16.27,31.53) v12(16.29,3.61) v12(16.33,34.04) v12(16.37,8.4) v12(16.43,7.98) v12(16.58,8.84) v12(16.65,35.08) v12(16.65,34.45) v12(16.65,7.01) v12(16.65,6.25) v12(16.65,5.36) v12(16.72,3.61) v12(16.78,41.97) v12(16.79,41.08) v12(16.78,7.98) v12(16.9,31.53) v12(16.87,8.4) v12(17.02,43.58) v12(17.03,33.81) v12(17.03,33.3) v12(16.94,8.84) v12(17,1.03) v12(17.13,18.92) v12(17.13,18.31) v12(17.13,17.71) v12(17.13,17.1) v12(17.13,16.49) v12(17.13,15.88) v12(17.13,15.27) v12(17.13,14.66) v12(17.13,14.05) v12(17.13,13.44) v12(17.13,12.83) v12(17.13,12.22) v12(17.13,10.62) v12(17.15,11.64) v12(17.13,11.06) v12(17.13,10.1) v12(17.29,45.86) v12(17.4,3.27) v12(17.4,1.9) v12(17.4,1.55) v12(17.4,1.17) v12(17.44,43.73) v12(17.6,45.86) v12(17.54,33.68) v12(17.54,33.05) v12(17.54,32.41) v12(17.54,31.78) v12(17.82,41.95) v12(17.77,18.14) v12(17.77,17.53) v12(17.77,16.92) v12(17.77,16.31) v12(17.77,15.7) v12(17.77,14.96) v12(17.81,6.26) v12(17.9,45.86) v12(17.87,41.54) v12(18.09,3.61) v12(18.21,45.86) v12(18.23,41.54) v12(18.17,36.35) v12(18.17,35.08) v12(18.17,34.32) v12(18.17,33.68) v12(18.17,33.05) v12(18.17,32.41) v12(18.17,31.78) v12(18.32,41.95) v12(18.3,16.92) v12(18.27,16.23) v12(18.27,15.62) v12(18.38,7.38) v12(18.51,45.86) v12(18.52,3.61) v12(18.68,43.73) v12(18.82,45.86) v12(18.81,36.35) v12(18.81,1.04) v12(18.93,33.05) v12(18.93,32.41) v12(18.93,31.78) v12(19.1,43.58) v12(19.19,3.18) v12(19.2,2.9) v12(19.2,2.61) v12(19.2,2.26) v12(19.2,1.9) v12(19.2,1.55) v12(19.2,1.17) v12(19.32,31.27) v12(19.32,30.51) v12(19.32,29.87) v12(19.57,36.35) v12(19.57,35.84) v12(19.57,35.21) v12(19.57,34.45) v12(19.57,33.81) v12(19.57,33.05) v12(19.57,32.41) v12(19.57,31.78) v12(20.13,39.71) v12(20.13,39.15) v12(20.13,38.59) v12(20.13,38.03) v12(20.13,37.47) v12(20.13,36.91) v12(20.13,36.35) v12(20.13,35.79) v12(20.13,35.23) v12(20.19,44.7) v12(20.18,44.09) v12(20.2,43.44) v12(20.18,41.75) v12(20.19,41) v12(20.2,40.29) v12(20.14,34.57) v12(20.13,33.99)
